VERSION 5.8 ;
BUSBITCHARS "[]" ;
DIVIDERCHAR "/" ;
UNITS
    DATABASE MICRONS 1000 ;
END UNITS

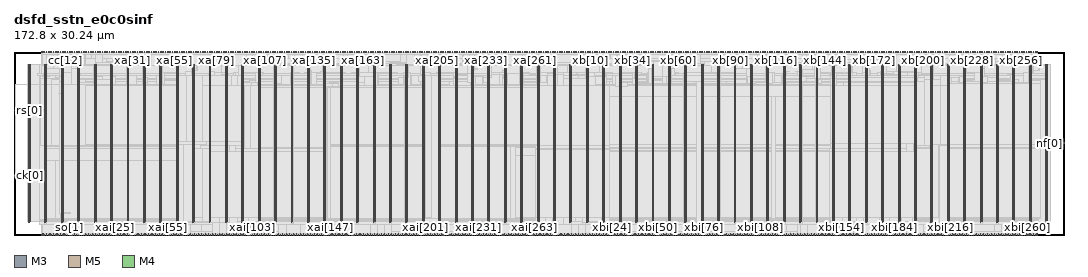
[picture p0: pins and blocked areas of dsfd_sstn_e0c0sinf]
MACRO dsfd_sstn_e0c0sinf
  FOREIGN dsfd_sstn_e0c0sinf 0 0 ;
  CLASS BLOCK ;
  SIZE 172.8 BY 30.24 ;
  PIN c0[0]
    DIRECTION INPUT ;
    USE SIGNAL ;
    PORT
      LAYER M3 ;
        RECT  4.464 30.096 4.482 30.24 ;
    END
  END c0[0]
  PIN c0[1]
    DIRECTION INPUT ;
    USE SIGNAL ;
    PORT
      LAYER M5 ;
        RECT  4.752 30.048 4.776 30.24 ;
    END
  END c0[1]
  PIN cc[0]
    DIRECTION OUTPUT ;
    USE SIGNAL ;
    PORT
      LAYER M3 ;
        RECT  5.04 30.096 5.058 30.24 ;
    END
  END cc[0]
  PIN cc[10]
    DIRECTION OUTPUT ;
    USE SIGNAL ;
    PORT
      LAYER M3 ;
        RECT  7.92 30.096 7.938 30.24 ;
    END
  END cc[10]
  PIN cc[11]
    DIRECTION OUTPUT ;
    USE SIGNAL ;
    PORT
      LAYER M5 ;
        RECT  8.208 30.048 8.232 30.24 ;
    END
  END cc[11]
  PIN cc[12]
    DIRECTION OUTPUT ;
    USE SIGNAL ;
    PORT
      LAYER M3 ;
        RECT  8.496 30.096 8.514 30.24 ;
    END
  END cc[12]
  PIN cc[13]
    DIRECTION OUTPUT ;
    USE SIGNAL ;
    PORT
      LAYER M5 ;
        RECT  8.784 30.048 8.808 30.24 ;
    END
  END cc[13]
  PIN cc[14]
    DIRECTION OUTPUT ;
    USE SIGNAL ;
    PORT
      LAYER M3 ;
        RECT  9.072 30.096 9.09 30.24 ;
    END
  END cc[14]
  PIN cc[1]
    DIRECTION OUTPUT ;
    USE SIGNAL ;
    PORT
      LAYER M5 ;
        RECT  5.328 30.048 5.352 30.24 ;
    END
  END cc[1]
  PIN cc[2]
    DIRECTION OUTPUT ;
    USE SIGNAL ;
    PORT
      LAYER M3 ;
        RECT  5.616 30.096 5.634 30.24 ;
    END
  END cc[2]
  PIN cc[3]
    DIRECTION OUTPUT ;
    USE SIGNAL ;
    PORT
      LAYER M5 ;
        RECT  5.904 30.048 5.928 30.24 ;
    END
  END cc[3]
  PIN cc[4]
    DIRECTION OUTPUT ;
    USE SIGNAL ;
    PORT
      LAYER M3 ;
        RECT  6.192 30.096 6.21 30.24 ;
    END
  END cc[4]
  PIN cc[5]
    DIRECTION OUTPUT ;
    USE SIGNAL ;
    PORT
      LAYER M5 ;
        RECT  6.48 30.048 6.504 30.24 ;
    END
  END cc[5]
  PIN cc[6]
    DIRECTION OUTPUT ;
    USE SIGNAL ;
    PORT
      LAYER M3 ;
        RECT  6.768 30.096 6.786 30.24 ;
    END
  END cc[6]
  PIN cc[7]
    DIRECTION OUTPUT ;
    USE SIGNAL ;
    PORT
      LAYER M5 ;
        RECT  7.056 30.048 7.08 30.24 ;
    END
  END cc[7]
  PIN cc[8]
    DIRECTION OUTPUT ;
    USE SIGNAL ;
    PORT
      LAYER M3 ;
        RECT  7.344 30.096 7.362 30.24 ;
    END
  END cc[8]
  PIN cc[9]
    DIRECTION OUTPUT ;
    USE SIGNAL ;
    PORT
      LAYER M5 ;
        RECT  7.632 30.048 7.656 30.24 ;
    END
  END cc[9]
  PIN cci[0]
    DIRECTION INPUT ;
    USE SIGNAL ;
    PORT
      LAYER M3 ;
        RECT  4.464 0 4.482 0.144 ;
    END
  END cci[0]
  PIN cci[10]
    DIRECTION INPUT ;
    USE SIGNAL ;
    PORT
      LAYER M3 ;
        RECT  7.344 0 7.362 0.144 ;
    END
  END cci[10]
  PIN cci[11]
    DIRECTION INPUT ;
    USE SIGNAL ;
    PORT
      LAYER M5 ;
        RECT  7.632 0 7.656 0.192 ;
    END
  END cci[11]
  PIN cci[12]
    DIRECTION INPUT ;
    USE SIGNAL ;
    PORT
      LAYER M3 ;
        RECT  7.92 0 7.938 0.144 ;
    END
  END cci[12]
  PIN cci[13]
    DIRECTION INPUT ;
    USE SIGNAL ;
    PORT
      LAYER M5 ;
        RECT  8.208 0 8.232 0.192 ;
    END
  END cci[13]
  PIN cci[14]
    DIRECTION INPUT ;
    USE SIGNAL ;
    PORT
      LAYER M3 ;
        RECT  8.532 0 8.55 0.144 ;
    END
  END cci[14]
  PIN cci[1]
    DIRECTION INPUT ;
    USE SIGNAL ;
    PORT
      LAYER M5 ;
        RECT  4.752 0 4.776 0.192 ;
    END
  END cci[1]
  PIN cci[2]
    DIRECTION INPUT ;
    USE SIGNAL ;
    PORT
      LAYER M3 ;
        RECT  5.04 0 5.058 0.144 ;
    END
  END cci[2]
  PIN cci[3]
    DIRECTION INPUT ;
    USE SIGNAL ;
    PORT
      LAYER M5 ;
        RECT  5.328 0 5.352 0.192 ;
    END
  END cci[3]
  PIN cci[4]
    DIRECTION INPUT ;
    USE SIGNAL ;
    PORT
      LAYER M3 ;
        RECT  5.616 0 5.634 0.144 ;
    END
  END cci[4]
  PIN cci[5]
    DIRECTION INPUT ;
    USE SIGNAL ;
    PORT
      LAYER M5 ;
        RECT  5.904 0 5.928 0.192 ;
    END
  END cci[5]
  PIN cci[6]
    DIRECTION INPUT ;
    USE SIGNAL ;
    PORT
      LAYER M3 ;
        RECT  6.192 0 6.21 0.144 ;
    END
  END cci[6]
  PIN cci[7]
    DIRECTION INPUT ;
    USE SIGNAL ;
    PORT
      LAYER M5 ;
        RECT  6.48 0 6.504 0.192 ;
    END
  END cci[7]
  PIN cci[8]
    DIRECTION INPUT ;
    USE SIGNAL ;
    PORT
      LAYER M3 ;
        RECT  6.768 0 6.786 0.144 ;
    END
  END cci[8]
  PIN cci[9]
    DIRECTION INPUT ;
    USE SIGNAL ;
    PORT
      LAYER M5 ;
        RECT  7.056 0 7.08 0.192 ;
    END
  END cci[9]
  PIN ck[0]
    DIRECTION INPUT ;
    USE SIGNAL ;
    PORT
      LAYER M4 ;
        RECT  0 9.744 0.192 9.768 ;
    END
    PORT
      LAYER M4 ;
        RECT  0.156 9.744 0.275 9.768 ;
    END
  END ck[0]
  PIN e0[0]
    DIRECTION INPUT ;
    USE SIGNAL ;
    PORT
      LAYER M5 ;
        RECT  9.36 30.048 9.384 30.24 ;
    END
  END e0[0]
  PIN e0[1]
    DIRECTION INPUT ;
    USE SIGNAL ;
    PORT
      LAYER M3 ;
        RECT  9.648 30.096 9.666 30.24 ;
    END
  END e0[1]
  PIN nf[0]
    DIRECTION INPUT ;
    USE SIGNAL ;
    PORT
      LAYER M4 ;
        RECT  172.608 15.12 172.8 15.144 ;
    END
    PORT
      LAYER M4 ;
        RECT  170.104 15.12 172.62 15.144 ;
    END
  END nf[0]
  PIN rs[0]
    DIRECTION INPUT ;
    USE SIGNAL ;
    PORT
      LAYER M4 ;
        RECT  0 20.544 0.192 20.568 ;
    END
    PORT
      LAYER M4 ;
        RECT  0.156 20.544 2.408 20.568 ;
    END
  END rs[0]
  PIN si[0]
    DIRECTION INPUT ;
    USE SIGNAL ;
    PORT
      LAYER M5 ;
        RECT  9.936 30.048 9.96 30.24 ;
    END
  END si[0]
  PIN si[1]
    DIRECTION INPUT ;
    USE SIGNAL ;
    PORT
      LAYER M3 ;
        RECT  10.224 30.096 10.242 30.24 ;
    END
  END si[1]
  PIN so[0]
    DIRECTION OUTPUT ;
    USE SIGNAL ;
    PORT
      LAYER M5 ;
        RECT  8.784 0 8.808 0.192 ;
    END
  END so[0]
  PIN so[1]
    DIRECTION OUTPUT ;
    USE SIGNAL ;
    PORT
      LAYER M3 ;
        RECT  9.108 0 9.126 0.144 ;
    END
  END so[1]
  PIN xa[0]
    DIRECTION OUTPUT ;
    USE SIGNAL ;
    PORT
      LAYER M5 ;
        RECT  10.512 30.048 10.536 30.24 ;
    END
  END xa[0]
  PIN xa[100]
    DIRECTION OUTPUT ;
    USE SIGNAL ;
    PORT
      LAYER M5 ;
        RECT  39.312 30.048 39.336 30.24 ;
    END
  END xa[100]
  PIN xa[101]
    DIRECTION OUTPUT ;
    USE SIGNAL ;
    PORT
      LAYER M3 ;
        RECT  39.6 30.096 39.618 30.24 ;
    END
  END xa[101]
  PIN xa[102]
    DIRECTION OUTPUT ;
    USE SIGNAL ;
    PORT
      LAYER M5 ;
        RECT  39.888 30.048 39.912 30.24 ;
    END
  END xa[102]
  PIN xa[103]
    DIRECTION OUTPUT ;
    USE SIGNAL ;
    PORT
      LAYER M3 ;
        RECT  40.176 30.096 40.194 30.24 ;
    END
  END xa[103]
  PIN xa[104]
    DIRECTION OUTPUT ;
    USE SIGNAL ;
    PORT
      LAYER M5 ;
        RECT  40.464 30.048 40.488 30.24 ;
    END
  END xa[104]
  PIN xa[105]
    DIRECTION OUTPUT ;
    USE SIGNAL ;
    PORT
      LAYER M3 ;
        RECT  40.752 30.096 40.77 30.24 ;
    END
  END xa[105]
  PIN xa[106]
    DIRECTION OUTPUT ;
    USE SIGNAL ;
    PORT
      LAYER M5 ;
        RECT  41.04 30.048 41.064 30.24 ;
    END
  END xa[106]
  PIN xa[107]
    DIRECTION OUTPUT ;
    USE SIGNAL ;
    PORT
      LAYER M3 ;
        RECT  41.328 30.096 41.346 30.24 ;
    END
  END xa[107]
  PIN xa[108]
    DIRECTION OUTPUT ;
    USE SIGNAL ;
    PORT
      LAYER M5 ;
        RECT  41.616 30.048 41.64 30.24 ;
    END
  END xa[108]
  PIN xa[109]
    DIRECTION OUTPUT ;
    USE SIGNAL ;
    PORT
      LAYER M3 ;
        RECT  41.904 30.096 41.922 30.24 ;
    END
  END xa[109]
  PIN xa[10]
    DIRECTION OUTPUT ;
    USE SIGNAL ;
    PORT
      LAYER M5 ;
        RECT  13.392 30.048 13.416 30.24 ;
    END
  END xa[10]
  PIN xa[110]
    DIRECTION OUTPUT ;
    USE SIGNAL ;
    PORT
      LAYER M5 ;
        RECT  42.192 30.048 42.216 30.24 ;
    END
  END xa[110]
  PIN xa[111]
    DIRECTION OUTPUT ;
    USE SIGNAL ;
    PORT
      LAYER M3 ;
        RECT  42.48 30.096 42.498 30.24 ;
    END
  END xa[111]
  PIN xa[112]
    DIRECTION OUTPUT ;
    USE SIGNAL ;
    PORT
      LAYER M5 ;
        RECT  42.768 30.048 42.792 30.24 ;
    END
  END xa[112]
  PIN xa[113]
    DIRECTION OUTPUT ;
    USE SIGNAL ;
    PORT
      LAYER M3 ;
        RECT  43.056 30.096 43.074 30.24 ;
    END
  END xa[113]
  PIN xa[114]
    DIRECTION OUTPUT ;
    USE SIGNAL ;
    PORT
      LAYER M5 ;
        RECT  43.344 30.048 43.368 30.24 ;
    END
  END xa[114]
  PIN xa[115]
    DIRECTION OUTPUT ;
    USE SIGNAL ;
    PORT
      LAYER M3 ;
        RECT  43.632 30.096 43.65 30.24 ;
    END
  END xa[115]
  PIN xa[116]
    DIRECTION OUTPUT ;
    USE SIGNAL ;
    PORT
      LAYER M5 ;
        RECT  43.92 30.048 43.944 30.24 ;
    END
  END xa[116]
  PIN xa[117]
    DIRECTION OUTPUT ;
    USE SIGNAL ;
    PORT
      LAYER M3 ;
        RECT  44.208 30.096 44.226 30.24 ;
    END
  END xa[117]
  PIN xa[118]
    DIRECTION OUTPUT ;
    USE SIGNAL ;
    PORT
      LAYER M5 ;
        RECT  44.496 30.048 44.52 30.24 ;
    END
  END xa[118]
  PIN xa[119]
    DIRECTION OUTPUT ;
    USE SIGNAL ;
    PORT
      LAYER M3 ;
        RECT  44.784 30.096 44.802 30.24 ;
    END
  END xa[119]
  PIN xa[11]
    DIRECTION OUTPUT ;
    USE SIGNAL ;
    PORT
      LAYER M3 ;
        RECT  13.68 30.096 13.698 30.24 ;
    END
  END xa[11]
  PIN xa[120]
    DIRECTION OUTPUT ;
    USE SIGNAL ;
    PORT
      LAYER M5 ;
        RECT  45.072 30.048 45.096 30.24 ;
    END
  END xa[120]
  PIN xa[121]
    DIRECTION OUTPUT ;
    USE SIGNAL ;
    PORT
      LAYER M3 ;
        RECT  45.36 30.096 45.378 30.24 ;
    END
  END xa[121]
  PIN xa[122]
    DIRECTION OUTPUT ;
    USE SIGNAL ;
    PORT
      LAYER M5 ;
        RECT  45.648 30.048 45.672 30.24 ;
    END
  END xa[122]
  PIN xa[123]
    DIRECTION OUTPUT ;
    USE SIGNAL ;
    PORT
      LAYER M3 ;
        RECT  45.936 30.096 45.954 30.24 ;
    END
  END xa[123]
  PIN xa[124]
    DIRECTION OUTPUT ;
    USE SIGNAL ;
    PORT
      LAYER M5 ;
        RECT  46.224 30.048 46.248 30.24 ;
    END
  END xa[124]
  PIN xa[125]
    DIRECTION OUTPUT ;
    USE SIGNAL ;
    PORT
      LAYER M3 ;
        RECT  46.512 30.096 46.53 30.24 ;
    END
  END xa[125]
  PIN xa[126]
    DIRECTION OUTPUT ;
    USE SIGNAL ;
    PORT
      LAYER M5 ;
        RECT  46.8 30.048 46.824 30.24 ;
    END
  END xa[126]
  PIN xa[127]
    DIRECTION OUTPUT ;
    USE SIGNAL ;
    PORT
      LAYER M3 ;
        RECT  47.088 30.096 47.106 30.24 ;
    END
  END xa[127]
  PIN xa[128]
    DIRECTION OUTPUT ;
    USE SIGNAL ;
    PORT
      LAYER M5 ;
        RECT  47.376 30.048 47.4 30.24 ;
    END
  END xa[128]
  PIN xa[129]
    DIRECTION OUTPUT ;
    USE SIGNAL ;
    PORT
      LAYER M3 ;
        RECT  47.664 30.096 47.682 30.24 ;
    END
  END xa[129]
  PIN xa[12]
    DIRECTION OUTPUT ;
    USE SIGNAL ;
    PORT
      LAYER M5 ;
        RECT  13.968 30.048 13.992 30.24 ;
    END
  END xa[12]
  PIN xa[130]
    DIRECTION OUTPUT ;
    USE SIGNAL ;
    PORT
      LAYER M5 ;
        RECT  47.952 30.048 47.976 30.24 ;
    END
  END xa[130]
  PIN xa[131]
    DIRECTION OUTPUT ;
    USE SIGNAL ;
    PORT
      LAYER M3 ;
        RECT  48.24 30.096 48.258 30.24 ;
    END
  END xa[131]
  PIN xa[132]
    DIRECTION OUTPUT ;
    USE SIGNAL ;
    PORT
      LAYER M5 ;
        RECT  48.528 30.048 48.552 30.24 ;
    END
  END xa[132]
  PIN xa[133]
    DIRECTION OUTPUT ;
    USE SIGNAL ;
    PORT
      LAYER M3 ;
        RECT  48.816 30.096 48.834 30.24 ;
    END
  END xa[133]
  PIN xa[134]
    DIRECTION OUTPUT ;
    USE SIGNAL ;
    PORT
      LAYER M5 ;
        RECT  49.104 30.048 49.128 30.24 ;
    END
  END xa[134]
  PIN xa[135]
    DIRECTION OUTPUT ;
    USE SIGNAL ;
    PORT
      LAYER M3 ;
        RECT  49.392 30.096 49.41 30.24 ;
    END
  END xa[135]
  PIN xa[136]
    DIRECTION OUTPUT ;
    USE SIGNAL ;
    PORT
      LAYER M5 ;
        RECT  49.68 30.048 49.704 30.24 ;
    END
  END xa[136]
  PIN xa[137]
    DIRECTION OUTPUT ;
    USE SIGNAL ;
    PORT
      LAYER M3 ;
        RECT  49.968 30.096 49.986 30.24 ;
    END
  END xa[137]
  PIN xa[138]
    DIRECTION OUTPUT ;
    USE SIGNAL ;
    PORT
      LAYER M5 ;
        RECT  50.256 30.048 50.28 30.24 ;
    END
  END xa[138]
  PIN xa[139]
    DIRECTION OUTPUT ;
    USE SIGNAL ;
    PORT
      LAYER M3 ;
        RECT  50.544 30.096 50.562 30.24 ;
    END
  END xa[139]
  PIN xa[13]
    DIRECTION OUTPUT ;
    USE SIGNAL ;
    PORT
      LAYER M3 ;
        RECT  14.256 30.096 14.274 30.24 ;
    END
  END xa[13]
  PIN xa[140]
    DIRECTION OUTPUT ;
    USE SIGNAL ;
    PORT
      LAYER M5 ;
        RECT  50.832 30.048 50.856 30.24 ;
    END
  END xa[140]
  PIN xa[141]
    DIRECTION OUTPUT ;
    USE SIGNAL ;
    PORT
      LAYER M3 ;
        RECT  51.12 30.096 51.138 30.24 ;
    END
  END xa[141]
  PIN xa[142]
    DIRECTION OUTPUT ;
    USE SIGNAL ;
    PORT
      LAYER M5 ;
        RECT  51.408 30.048 51.432 30.24 ;
    END
  END xa[142]
  PIN xa[143]
    DIRECTION OUTPUT ;
    USE SIGNAL ;
    PORT
      LAYER M3 ;
        RECT  51.696 30.096 51.714 30.24 ;
    END
  END xa[143]
  PIN xa[144]
    DIRECTION OUTPUT ;
    USE SIGNAL ;
    PORT
      LAYER M5 ;
        RECT  51.984 30.048 52.008 30.24 ;
    END
  END xa[144]
  PIN xa[145]
    DIRECTION OUTPUT ;
    USE SIGNAL ;
    PORT
      LAYER M3 ;
        RECT  52.272 30.096 52.29 30.24 ;
    END
  END xa[145]
  PIN xa[146]
    DIRECTION OUTPUT ;
    USE SIGNAL ;
    PORT
      LAYER M5 ;
        RECT  52.56 30.048 52.584 30.24 ;
    END
  END xa[146]
  PIN xa[147]
    DIRECTION OUTPUT ;
    USE SIGNAL ;
    PORT
      LAYER M3 ;
        RECT  52.848 30.096 52.866 30.24 ;
    END
  END xa[147]
  PIN xa[148]
    DIRECTION OUTPUT ;
    USE SIGNAL ;
    PORT
      LAYER M5 ;
        RECT  53.136 30.048 53.16 30.24 ;
    END
  END xa[148]
  PIN xa[149]
    DIRECTION OUTPUT ;
    USE SIGNAL ;
    PORT
      LAYER M3 ;
        RECT  53.424 30.096 53.442 30.24 ;
    END
  END xa[149]
  PIN xa[14]
    DIRECTION OUTPUT ;
    USE SIGNAL ;
    PORT
      LAYER M5 ;
        RECT  14.544 30.048 14.568 30.24 ;
    END
  END xa[14]
  PIN xa[150]
    DIRECTION OUTPUT ;
    USE SIGNAL ;
    PORT
      LAYER M5 ;
        RECT  53.712 30.048 53.736 30.24 ;
    END
  END xa[150]
  PIN xa[151]
    DIRECTION OUTPUT ;
    USE SIGNAL ;
    PORT
      LAYER M3 ;
        RECT  54 30.096 54.018 30.24 ;
    END
  END xa[151]
  PIN xa[152]
    DIRECTION OUTPUT ;
    USE SIGNAL ;
    PORT
      LAYER M5 ;
        RECT  54.288 30.048 54.312 30.24 ;
    END
  END xa[152]
  PIN xa[153]
    DIRECTION OUTPUT ;
    USE SIGNAL ;
    PORT
      LAYER M3 ;
        RECT  54.576 30.096 54.594 30.24 ;
    END
  END xa[153]
  PIN xa[154]
    DIRECTION OUTPUT ;
    USE SIGNAL ;
    PORT
      LAYER M5 ;
        RECT  54.864 30.048 54.888 30.24 ;
    END
  END xa[154]
  PIN xa[155]
    DIRECTION OUTPUT ;
    USE SIGNAL ;
    PORT
      LAYER M3 ;
        RECT  55.152 30.096 55.17 30.24 ;
    END
  END xa[155]
  PIN xa[156]
    DIRECTION OUTPUT ;
    USE SIGNAL ;
    PORT
      LAYER M5 ;
        RECT  55.44 30.048 55.464 30.24 ;
    END
  END xa[156]
  PIN xa[157]
    DIRECTION OUTPUT ;
    USE SIGNAL ;
    PORT
      LAYER M3 ;
        RECT  55.728 30.096 55.746 30.24 ;
    END
  END xa[157]
  PIN xa[158]
    DIRECTION OUTPUT ;
    USE SIGNAL ;
    PORT
      LAYER M5 ;
        RECT  56.016 30.048 56.04 30.24 ;
    END
  END xa[158]
  PIN xa[159]
    DIRECTION OUTPUT ;
    USE SIGNAL ;
    PORT
      LAYER M3 ;
        RECT  56.304 30.096 56.322 30.24 ;
    END
  END xa[159]
  PIN xa[15]
    DIRECTION OUTPUT ;
    USE SIGNAL ;
    PORT
      LAYER M3 ;
        RECT  14.832 30.096 14.85 30.24 ;
    END
  END xa[15]
  PIN xa[160]
    DIRECTION OUTPUT ;
    USE SIGNAL ;
    PORT
      LAYER M5 ;
        RECT  56.592 30.048 56.616 30.24 ;
    END
  END xa[160]
  PIN xa[161]
    DIRECTION OUTPUT ;
    USE SIGNAL ;
    PORT
      LAYER M3 ;
        RECT  56.88 30.096 56.898 30.24 ;
    END
  END xa[161]
  PIN xa[162]
    DIRECTION OUTPUT ;
    USE SIGNAL ;
    PORT
      LAYER M5 ;
        RECT  57.168 30.048 57.192 30.24 ;
    END
  END xa[162]
  PIN xa[163]
    DIRECTION OUTPUT ;
    USE SIGNAL ;
    PORT
      LAYER M3 ;
        RECT  57.456 30.096 57.474 30.24 ;
    END
  END xa[163]
  PIN xa[164]
    DIRECTION OUTPUT ;
    USE SIGNAL ;
    PORT
      LAYER M5 ;
        RECT  57.744 30.048 57.768 30.24 ;
    END
  END xa[164]
  PIN xa[165]
    DIRECTION OUTPUT ;
    USE SIGNAL ;
    PORT
      LAYER M3 ;
        RECT  58.032 30.096 58.05 30.24 ;
    END
  END xa[165]
  PIN xa[166]
    DIRECTION OUTPUT ;
    USE SIGNAL ;
    PORT
      LAYER M5 ;
        RECT  58.32 30.048 58.344 30.24 ;
    END
  END xa[166]
  PIN xa[167]
    DIRECTION OUTPUT ;
    USE SIGNAL ;
    PORT
      LAYER M3 ;
        RECT  58.608 30.096 58.626 30.24 ;
    END
  END xa[167]
  PIN xa[168]
    DIRECTION OUTPUT ;
    USE SIGNAL ;
    PORT
      LAYER M5 ;
        RECT  58.896 30.048 58.92 30.24 ;
    END
  END xa[168]
  PIN xa[169]
    DIRECTION OUTPUT ;
    USE SIGNAL ;
    PORT
      LAYER M3 ;
        RECT  59.184 30.096 59.202 30.24 ;
    END
  END xa[169]
  PIN xa[16]
    DIRECTION OUTPUT ;
    USE SIGNAL ;
    PORT
      LAYER M5 ;
        RECT  15.12 30.048 15.144 30.24 ;
    END
  END xa[16]
  PIN xa[170]
    DIRECTION OUTPUT ;
    USE SIGNAL ;
    PORT
      LAYER M5 ;
        RECT  59.472 30.048 59.496 30.24 ;
    END
  END xa[170]
  PIN xa[171]
    DIRECTION OUTPUT ;
    USE SIGNAL ;
    PORT
      LAYER M3 ;
        RECT  59.76 30.096 59.778 30.24 ;
    END
  END xa[171]
  PIN xa[172]
    DIRECTION OUTPUT ;
    USE SIGNAL ;
    PORT
      LAYER M5 ;
        RECT  60.048 30.048 60.072 30.24 ;
    END
  END xa[172]
  PIN xa[173]
    DIRECTION OUTPUT ;
    USE SIGNAL ;
    PORT
      LAYER M3 ;
        RECT  60.336 30.096 60.354 30.24 ;
    END
  END xa[173]
  PIN xa[174]
    DIRECTION OUTPUT ;
    USE SIGNAL ;
    PORT
      LAYER M5 ;
        RECT  60.624 30.048 60.648 30.24 ;
    END
  END xa[174]
  PIN xa[175]
    DIRECTION OUTPUT ;
    USE SIGNAL ;
    PORT
      LAYER M3 ;
        RECT  60.912 30.096 60.93 30.24 ;
    END
  END xa[175]
  PIN xa[176]
    DIRECTION OUTPUT ;
    USE SIGNAL ;
    PORT
      LAYER M5 ;
        RECT  61.2 30.048 61.224 30.24 ;
    END
  END xa[176]
  PIN xa[177]
    DIRECTION OUTPUT ;
    USE SIGNAL ;
    PORT
      LAYER M3 ;
        RECT  61.488 30.096 61.506 30.24 ;
    END
  END xa[177]
  PIN xa[178]
    DIRECTION OUTPUT ;
    USE SIGNAL ;
    PORT
      LAYER M5 ;
        RECT  61.776 30.048 61.8 30.24 ;
    END
  END xa[178]
  PIN xa[179]
    DIRECTION OUTPUT ;
    USE SIGNAL ;
    PORT
      LAYER M3 ;
        RECT  62.064 30.096 62.082 30.24 ;
    END
  END xa[179]
  PIN xa[17]
    DIRECTION OUTPUT ;
    USE SIGNAL ;
    PORT
      LAYER M3 ;
        RECT  15.408 30.096 15.426 30.24 ;
    END
  END xa[17]
  PIN xa[180]
    DIRECTION OUTPUT ;
    USE SIGNAL ;
    PORT
      LAYER M5 ;
        RECT  62.352 30.048 62.376 30.24 ;
    END
  END xa[180]
  PIN xa[181]
    DIRECTION OUTPUT ;
    USE SIGNAL ;
    PORT
      LAYER M3 ;
        RECT  62.64 30.096 62.658 30.24 ;
    END
  END xa[181]
  PIN xa[182]
    DIRECTION OUTPUT ;
    USE SIGNAL ;
    PORT
      LAYER M5 ;
        RECT  62.928 30.048 62.952 30.24 ;
    END
  END xa[182]
  PIN xa[183]
    DIRECTION OUTPUT ;
    USE SIGNAL ;
    PORT
      LAYER M3 ;
        RECT  63.216 30.096 63.234 30.24 ;
    END
  END xa[183]
  PIN xa[184]
    DIRECTION OUTPUT ;
    USE SIGNAL ;
    PORT
      LAYER M5 ;
        RECT  63.504 30.048 63.528 30.24 ;
    END
  END xa[184]
  PIN xa[185]
    DIRECTION OUTPUT ;
    USE SIGNAL ;
    PORT
      LAYER M3 ;
        RECT  63.792 30.096 63.81 30.24 ;
    END
  END xa[185]
  PIN xa[186]
    DIRECTION OUTPUT ;
    USE SIGNAL ;
    PORT
      LAYER M5 ;
        RECT  64.08 30.048 64.104 30.24 ;
    END
  END xa[186]
  PIN xa[187]
    DIRECTION OUTPUT ;
    USE SIGNAL ;
    PORT
      LAYER M3 ;
        RECT  64.368 30.096 64.386 30.24 ;
    END
  END xa[187]
  PIN xa[188]
    DIRECTION OUTPUT ;
    USE SIGNAL ;
    PORT
      LAYER M5 ;
        RECT  64.656 30.048 64.68 30.24 ;
    END
  END xa[188]
  PIN xa[189]
    DIRECTION OUTPUT ;
    USE SIGNAL ;
    PORT
      LAYER M3 ;
        RECT  64.944 30.096 64.962 30.24 ;
    END
  END xa[189]
  PIN xa[18]
    DIRECTION OUTPUT ;
    USE SIGNAL ;
    PORT
      LAYER M5 ;
        RECT  15.696 30.048 15.72 30.24 ;
    END
  END xa[18]
  PIN xa[190]
    DIRECTION OUTPUT ;
    USE SIGNAL ;
    PORT
      LAYER M5 ;
        RECT  65.232 30.048 65.256 30.24 ;
    END
  END xa[190]
  PIN xa[191]
    DIRECTION OUTPUT ;
    USE SIGNAL ;
    PORT
      LAYER M3 ;
        RECT  65.52 30.096 65.538 30.24 ;
    END
  END xa[191]
  PIN xa[192]
    DIRECTION OUTPUT ;
    USE SIGNAL ;
    PORT
      LAYER M5 ;
        RECT  65.808 30.048 65.832 30.24 ;
    END
  END xa[192]
  PIN xa[193]
    DIRECTION OUTPUT ;
    USE SIGNAL ;
    PORT
      LAYER M3 ;
        RECT  66.096 30.096 66.114 30.24 ;
    END
  END xa[193]
  PIN xa[194]
    DIRECTION OUTPUT ;
    USE SIGNAL ;
    PORT
      LAYER M5 ;
        RECT  66.384 30.048 66.408 30.24 ;
    END
  END xa[194]
  PIN xa[195]
    DIRECTION OUTPUT ;
    USE SIGNAL ;
    PORT
      LAYER M3 ;
        RECT  66.672 30.096 66.69 30.24 ;
    END
  END xa[195]
  PIN xa[196]
    DIRECTION OUTPUT ;
    USE SIGNAL ;
    PORT
      LAYER M5 ;
        RECT  66.96 30.048 66.984 30.24 ;
    END
  END xa[196]
  PIN xa[197]
    DIRECTION OUTPUT ;
    USE SIGNAL ;
    PORT
      LAYER M3 ;
        RECT  67.248 30.096 67.266 30.24 ;
    END
  END xa[197]
  PIN xa[198]
    DIRECTION OUTPUT ;
    USE SIGNAL ;
    PORT
      LAYER M5 ;
        RECT  67.536 30.048 67.56 30.24 ;
    END
  END xa[198]
  PIN xa[199]
    DIRECTION OUTPUT ;
    USE SIGNAL ;
    PORT
      LAYER M3 ;
        RECT  67.824 30.096 67.842 30.24 ;
    END
  END xa[199]
  PIN xa[19]
    DIRECTION OUTPUT ;
    USE SIGNAL ;
    PORT
      LAYER M3 ;
        RECT  15.984 30.096 16.002 30.24 ;
    END
  END xa[19]
  PIN xa[1]
    DIRECTION OUTPUT ;
    USE SIGNAL ;
    PORT
      LAYER M3 ;
        RECT  10.8 30.096 10.818 30.24 ;
    END
  END xa[1]
  PIN xa[200]
    DIRECTION OUTPUT ;
    USE SIGNAL ;
    PORT
      LAYER M5 ;
        RECT  68.112 30.048 68.136 30.24 ;
    END
  END xa[200]
  PIN xa[201]
    DIRECTION OUTPUT ;
    USE SIGNAL ;
    PORT
      LAYER M3 ;
        RECT  68.4 30.096 68.418 30.24 ;
    END
  END xa[201]
  PIN xa[202]
    DIRECTION OUTPUT ;
    USE SIGNAL ;
    PORT
      LAYER M5 ;
        RECT  68.688 30.048 68.712 30.24 ;
    END
  END xa[202]
  PIN xa[203]
    DIRECTION OUTPUT ;
    USE SIGNAL ;
    PORT
      LAYER M3 ;
        RECT  68.976 30.096 68.994 30.24 ;
    END
  END xa[203]
  PIN xa[204]
    DIRECTION OUTPUT ;
    USE SIGNAL ;
    PORT
      LAYER M5 ;
        RECT  69.264 30.048 69.288 30.24 ;
    END
  END xa[204]
  PIN xa[205]
    DIRECTION OUTPUT ;
    USE SIGNAL ;
    PORT
      LAYER M3 ;
        RECT  69.552 30.096 69.57 30.24 ;
    END
  END xa[205]
  PIN xa[206]
    DIRECTION OUTPUT ;
    USE SIGNAL ;
    PORT
      LAYER M5 ;
        RECT  69.84 30.048 69.864 30.24 ;
    END
  END xa[206]
  PIN xa[207]
    DIRECTION OUTPUT ;
    USE SIGNAL ;
    PORT
      LAYER M3 ;
        RECT  70.128 30.096 70.146 30.24 ;
    END
  END xa[207]
  PIN xa[208]
    DIRECTION OUTPUT ;
    USE SIGNAL ;
    PORT
      LAYER M5 ;
        RECT  70.416 30.048 70.44 30.24 ;
    END
  END xa[208]
  PIN xa[209]
    DIRECTION OUTPUT ;
    USE SIGNAL ;
    PORT
      LAYER M3 ;
        RECT  70.704 30.096 70.722 30.24 ;
    END
  END xa[209]
  PIN xa[20]
    DIRECTION OUTPUT ;
    USE SIGNAL ;
    PORT
      LAYER M5 ;
        RECT  16.272 30.048 16.296 30.24 ;
    END
  END xa[20]
  PIN xa[210]
    DIRECTION OUTPUT ;
    USE SIGNAL ;
    PORT
      LAYER M5 ;
        RECT  70.992 30.048 71.016 30.24 ;
    END
  END xa[210]
  PIN xa[211]
    DIRECTION OUTPUT ;
    USE SIGNAL ;
    PORT
      LAYER M3 ;
        RECT  71.28 30.096 71.298 30.24 ;
    END
  END xa[211]
  PIN xa[212]
    DIRECTION OUTPUT ;
    USE SIGNAL ;
    PORT
      LAYER M5 ;
        RECT  71.568 30.048 71.592 30.24 ;
    END
  END xa[212]
  PIN xa[213]
    DIRECTION OUTPUT ;
    USE SIGNAL ;
    PORT
      LAYER M3 ;
        RECT  71.856 30.096 71.874 30.24 ;
    END
  END xa[213]
  PIN xa[214]
    DIRECTION OUTPUT ;
    USE SIGNAL ;
    PORT
      LAYER M5 ;
        RECT  72.144 30.048 72.168 30.24 ;
    END
  END xa[214]
  PIN xa[215]
    DIRECTION OUTPUT ;
    USE SIGNAL ;
    PORT
      LAYER M3 ;
        RECT  72.432 30.096 72.45 30.24 ;
    END
  END xa[215]
  PIN xa[216]
    DIRECTION OUTPUT ;
    USE SIGNAL ;
    PORT
      LAYER M5 ;
        RECT  72.72 30.048 72.744 30.24 ;
    END
  END xa[216]
  PIN xa[217]
    DIRECTION OUTPUT ;
    USE SIGNAL ;
    PORT
      LAYER M3 ;
        RECT  73.008 30.096 73.026 30.24 ;
    END
  END xa[217]
  PIN xa[218]
    DIRECTION OUTPUT ;
    USE SIGNAL ;
    PORT
      LAYER M5 ;
        RECT  73.296 30.048 73.32 30.24 ;
    END
  END xa[218]
  PIN xa[219]
    DIRECTION OUTPUT ;
    USE SIGNAL ;
    PORT
      LAYER M3 ;
        RECT  73.584 30.096 73.602 30.24 ;
    END
  END xa[219]
  PIN xa[21]
    DIRECTION OUTPUT ;
    USE SIGNAL ;
    PORT
      LAYER M3 ;
        RECT  16.56 30.096 16.578 30.24 ;
    END
  END xa[21]
  PIN xa[220]
    DIRECTION OUTPUT ;
    USE SIGNAL ;
    PORT
      LAYER M5 ;
        RECT  73.872 30.048 73.896 30.24 ;
    END
  END xa[220]
  PIN xa[221]
    DIRECTION OUTPUT ;
    USE SIGNAL ;
    PORT
      LAYER M3 ;
        RECT  74.16 30.096 74.178 30.24 ;
    END
  END xa[221]
  PIN xa[222]
    DIRECTION OUTPUT ;
    USE SIGNAL ;
    PORT
      LAYER M5 ;
        RECT  74.448 30.048 74.472 30.24 ;
    END
  END xa[222]
  PIN xa[223]
    DIRECTION OUTPUT ;
    USE SIGNAL ;
    PORT
      LAYER M3 ;
        RECT  74.736 30.096 74.754 30.24 ;
    END
  END xa[223]
  PIN xa[224]
    DIRECTION OUTPUT ;
    USE SIGNAL ;
    PORT
      LAYER M5 ;
        RECT  75.024 30.048 75.048 30.24 ;
    END
  END xa[224]
  PIN xa[225]
    DIRECTION OUTPUT ;
    USE SIGNAL ;
    PORT
      LAYER M3 ;
        RECT  75.312 30.096 75.33 30.24 ;
    END
  END xa[225]
  PIN xa[226]
    DIRECTION OUTPUT ;
    USE SIGNAL ;
    PORT
      LAYER M5 ;
        RECT  75.6 30.048 75.624 30.24 ;
    END
  END xa[226]
  PIN xa[227]
    DIRECTION OUTPUT ;
    USE SIGNAL ;
    PORT
      LAYER M3 ;
        RECT  75.888 30.096 75.906 30.24 ;
    END
  END xa[227]
  PIN xa[228]
    DIRECTION OUTPUT ;
    USE SIGNAL ;
    PORT
      LAYER M5 ;
        RECT  76.176 30.048 76.2 30.24 ;
    END
  END xa[228]
  PIN xa[229]
    DIRECTION OUTPUT ;
    USE SIGNAL ;
    PORT
      LAYER M3 ;
        RECT  76.464 30.096 76.482 30.24 ;
    END
  END xa[229]
  PIN xa[22]
    DIRECTION OUTPUT ;
    USE SIGNAL ;
    PORT
      LAYER M5 ;
        RECT  16.848 30.048 16.872 30.24 ;
    END
  END xa[22]
  PIN xa[230]
    DIRECTION OUTPUT ;
    USE SIGNAL ;
    PORT
      LAYER M5 ;
        RECT  76.752 30.048 76.776 30.24 ;
    END
  END xa[230]
  PIN xa[231]
    DIRECTION OUTPUT ;
    USE SIGNAL ;
    PORT
      LAYER M3 ;
        RECT  77.04 30.096 77.058 30.24 ;
    END
  END xa[231]
  PIN xa[232]
    DIRECTION OUTPUT ;
    USE SIGNAL ;
    PORT
      LAYER M5 ;
        RECT  77.328 30.048 77.352 30.24 ;
    END
  END xa[232]
  PIN xa[233]
    DIRECTION OUTPUT ;
    USE SIGNAL ;
    PORT
      LAYER M3 ;
        RECT  77.616 30.096 77.634 30.24 ;
    END
  END xa[233]
  PIN xa[234]
    DIRECTION OUTPUT ;
    USE SIGNAL ;
    PORT
      LAYER M5 ;
        RECT  77.904 30.048 77.928 30.24 ;
    END
  END xa[234]
  PIN xa[235]
    DIRECTION OUTPUT ;
    USE SIGNAL ;
    PORT
      LAYER M3 ;
        RECT  78.192 30.096 78.21 30.24 ;
    END
  END xa[235]
  PIN xa[236]
    DIRECTION OUTPUT ;
    USE SIGNAL ;
    PORT
      LAYER M5 ;
        RECT  78.48 30.048 78.504 30.24 ;
    END
  END xa[236]
  PIN xa[237]
    DIRECTION OUTPUT ;
    USE SIGNAL ;
    PORT
      LAYER M3 ;
        RECT  78.768 30.096 78.786 30.24 ;
    END
  END xa[237]
  PIN xa[238]
    DIRECTION OUTPUT ;
    USE SIGNAL ;
    PORT
      LAYER M5 ;
        RECT  79.056 30.048 79.08 30.24 ;
    END
  END xa[238]
  PIN xa[239]
    DIRECTION OUTPUT ;
    USE SIGNAL ;
    PORT
      LAYER M3 ;
        RECT  79.344 30.096 79.362 30.24 ;
    END
  END xa[239]
  PIN xa[23]
    DIRECTION OUTPUT ;
    USE SIGNAL ;
    PORT
      LAYER M3 ;
        RECT  17.136 30.096 17.154 30.24 ;
    END
  END xa[23]
  PIN xa[240]
    DIRECTION OUTPUT ;
    USE SIGNAL ;
    PORT
      LAYER M5 ;
        RECT  79.632 30.048 79.656 30.24 ;
    END
  END xa[240]
  PIN xa[241]
    DIRECTION OUTPUT ;
    USE SIGNAL ;
    PORT
      LAYER M3 ;
        RECT  79.92 30.096 79.938 30.24 ;
    END
  END xa[241]
  PIN xa[242]
    DIRECTION OUTPUT ;
    USE SIGNAL ;
    PORT
      LAYER M5 ;
        RECT  80.208 30.048 80.232 30.24 ;
    END
  END xa[242]
  PIN xa[243]
    DIRECTION OUTPUT ;
    USE SIGNAL ;
    PORT
      LAYER M3 ;
        RECT  80.496 30.096 80.514 30.24 ;
    END
  END xa[243]
  PIN xa[244]
    DIRECTION OUTPUT ;
    USE SIGNAL ;
    PORT
      LAYER M5 ;
        RECT  80.784 30.048 80.808 30.24 ;
    END
  END xa[244]
  PIN xa[245]
    DIRECTION OUTPUT ;
    USE SIGNAL ;
    PORT
      LAYER M3 ;
        RECT  81.072 30.096 81.09 30.24 ;
    END
  END xa[245]
  PIN xa[246]
    DIRECTION OUTPUT ;
    USE SIGNAL ;
    PORT
      LAYER M5 ;
        RECT  81.36 30.048 81.384 30.24 ;
    END
  END xa[246]
  PIN xa[247]
    DIRECTION OUTPUT ;
    USE SIGNAL ;
    PORT
      LAYER M3 ;
        RECT  81.648 30.096 81.666 30.24 ;
    END
  END xa[247]
  PIN xa[248]
    DIRECTION OUTPUT ;
    USE SIGNAL ;
    PORT
      LAYER M5 ;
        RECT  81.936 30.048 81.96 30.24 ;
    END
  END xa[248]
  PIN xa[249]
    DIRECTION OUTPUT ;
    USE SIGNAL ;
    PORT
      LAYER M3 ;
        RECT  82.224 30.096 82.242 30.24 ;
    END
  END xa[249]
  PIN xa[24]
    DIRECTION OUTPUT ;
    USE SIGNAL ;
    PORT
      LAYER M5 ;
        RECT  17.424 30.048 17.448 30.24 ;
    END
  END xa[24]
  PIN xa[250]
    DIRECTION OUTPUT ;
    USE SIGNAL ;
    PORT
      LAYER M5 ;
        RECT  82.512 30.048 82.536 30.24 ;
    END
  END xa[250]
  PIN xa[251]
    DIRECTION OUTPUT ;
    USE SIGNAL ;
    PORT
      LAYER M3 ;
        RECT  82.8 30.096 82.818 30.24 ;
    END
  END xa[251]
  PIN xa[252]
    DIRECTION OUTPUT ;
    USE SIGNAL ;
    PORT
      LAYER M5 ;
        RECT  83.088 30.048 83.112 30.24 ;
    END
  END xa[252]
  PIN xa[253]
    DIRECTION OUTPUT ;
    USE SIGNAL ;
    PORT
      LAYER M3 ;
        RECT  83.376 30.096 83.394 30.24 ;
    END
  END xa[253]
  PIN xa[254]
    DIRECTION OUTPUT ;
    USE SIGNAL ;
    PORT
      LAYER M5 ;
        RECT  83.664 30.048 83.688 30.24 ;
    END
  END xa[254]
  PIN xa[255]
    DIRECTION OUTPUT ;
    USE SIGNAL ;
    PORT
      LAYER M3 ;
        RECT  83.952 30.096 83.97 30.24 ;
    END
  END xa[255]
  PIN xa[256]
    DIRECTION OUTPUT ;
    USE SIGNAL ;
    PORT
      LAYER M5 ;
        RECT  84.24 30.048 84.264 30.24 ;
    END
  END xa[256]
  PIN xa[257]
    DIRECTION OUTPUT ;
    USE SIGNAL ;
    PORT
      LAYER M3 ;
        RECT  84.528 30.096 84.546 30.24 ;
    END
  END xa[257]
  PIN xa[258]
    DIRECTION OUTPUT ;
    USE SIGNAL ;
    PORT
      LAYER M5 ;
        RECT  84.816 30.048 84.84 30.24 ;
    END
  END xa[258]
  PIN xa[259]
    DIRECTION OUTPUT ;
    USE SIGNAL ;
    PORT
      LAYER M3 ;
        RECT  85.104 30.096 85.122 30.24 ;
    END
  END xa[259]
  PIN xa[25]
    DIRECTION OUTPUT ;
    USE SIGNAL ;
    PORT
      LAYER M3 ;
        RECT  17.712 30.096 17.73 30.24 ;
    END
  END xa[25]
  PIN xa[260]
    DIRECTION OUTPUT ;
    USE SIGNAL ;
    PORT
      LAYER M5 ;
        RECT  85.392 30.048 85.416 30.24 ;
    END
  END xa[260]
  PIN xa[261]
    DIRECTION OUTPUT ;
    USE SIGNAL ;
    PORT
      LAYER M3 ;
        RECT  85.68 30.096 85.698 30.24 ;
    END
  END xa[261]
  PIN xa[262]
    DIRECTION OUTPUT ;
    USE SIGNAL ;
    PORT
      LAYER M5 ;
        RECT  85.968 30.048 85.992 30.24 ;
    END
  END xa[262]
  PIN xa[263]
    DIRECTION OUTPUT ;
    USE SIGNAL ;
    PORT
      LAYER M3 ;
        RECT  86.256 30.096 86.274 30.24 ;
    END
  END xa[263]
  PIN xa[264]
    DIRECTION OUTPUT ;
    USE SIGNAL ;
    PORT
      LAYER M5 ;
        RECT  86.544 30.048 86.568 30.24 ;
    END
  END xa[264]
  PIN xa[265]
    DIRECTION OUTPUT ;
    USE SIGNAL ;
    PORT
      LAYER M3 ;
        RECT  86.832 30.096 86.85 30.24 ;
    END
  END xa[265]
  PIN xa[266]
    DIRECTION OUTPUT ;
    USE SIGNAL ;
    PORT
      LAYER M5 ;
        RECT  87.12 30.048 87.144 30.24 ;
    END
  END xa[266]
  PIN xa[267]
    DIRECTION OUTPUT ;
    USE SIGNAL ;
    PORT
      LAYER M3 ;
        RECT  87.408 30.096 87.426 30.24 ;
    END
  END xa[267]
  PIN xa[268]
    DIRECTION OUTPUT ;
    USE SIGNAL ;
    PORT
      LAYER M5 ;
        RECT  87.696 30.048 87.72 30.24 ;
    END
  END xa[268]
  PIN xa[269]
    DIRECTION OUTPUT ;
    USE SIGNAL ;
    PORT
      LAYER M3 ;
        RECT  87.984 30.096 88.002 30.24 ;
    END
  END xa[269]
  PIN xa[26]
    DIRECTION OUTPUT ;
    USE SIGNAL ;
    PORT
      LAYER M5 ;
        RECT  18 30.048 18.024 30.24 ;
    END
  END xa[26]
  PIN xa[270]
    DIRECTION OUTPUT ;
    USE SIGNAL ;
    PORT
      LAYER M5 ;
        RECT  88.272 30.048 88.296 30.24 ;
    END
  END xa[270]
  PIN xa[271]
    DIRECTION OUTPUT ;
    USE SIGNAL ;
    PORT
      LAYER M3 ;
        RECT  88.56 30.096 88.578 30.24 ;
    END
  END xa[271]
  PIN xa[272]
    DIRECTION OUTPUT ;
    USE SIGNAL ;
    PORT
      LAYER M5 ;
        RECT  88.848 30.048 88.872 30.24 ;
    END
  END xa[272]
  PIN xa[273]
    DIRECTION OUTPUT ;
    USE SIGNAL ;
    PORT
      LAYER M3 ;
        RECT  89.136 30.096 89.154 30.24 ;
    END
  END xa[273]
  PIN xa[274]
    DIRECTION OUTPUT ;
    USE SIGNAL ;
    PORT
      LAYER M5 ;
        RECT  89.424 30.048 89.448 30.24 ;
    END
  END xa[274]
  PIN xa[275]
    DIRECTION OUTPUT ;
    USE SIGNAL ;
    PORT
      LAYER M3 ;
        RECT  89.712 30.096 89.73 30.24 ;
    END
  END xa[275]
  PIN xa[276]
    DIRECTION OUTPUT ;
    USE SIGNAL ;
    PORT
      LAYER M5 ;
        RECT  90 30.048 90.024 30.24 ;
    END
  END xa[276]
  PIN xa[277]
    DIRECTION OUTPUT ;
    USE SIGNAL ;
    PORT
      LAYER M3 ;
        RECT  90.288 30.096 90.306 30.24 ;
    END
  END xa[277]
  PIN xa[278]
    DIRECTION OUTPUT ;
    USE SIGNAL ;
    PORT
      LAYER M5 ;
        RECT  90.576 30.048 90.6 30.24 ;
    END
  END xa[278]
  PIN xa[279]
    DIRECTION OUTPUT ;
    USE SIGNAL ;
    PORT
      LAYER M3 ;
        RECT  90.864 30.096 90.882 30.24 ;
    END
  END xa[279]
  PIN xa[27]
    DIRECTION OUTPUT ;
    USE SIGNAL ;
    PORT
      LAYER M3 ;
        RECT  18.288 30.096 18.306 30.24 ;
    END
  END xa[27]
  PIN xa[280]
    DIRECTION OUTPUT ;
    USE SIGNAL ;
    PORT
      LAYER M5 ;
        RECT  91.152 30.048 91.176 30.24 ;
    END
  END xa[280]
  PIN xa[281]
    DIRECTION OUTPUT ;
    USE SIGNAL ;
    PORT
      LAYER M3 ;
        RECT  91.44 30.096 91.458 30.24 ;
    END
  END xa[281]
  PIN xa[282]
    DIRECTION OUTPUT ;
    USE SIGNAL ;
    PORT
      LAYER M5 ;
        RECT  91.728 30.048 91.752 30.24 ;
    END
  END xa[282]
  PIN xa[28]
    DIRECTION OUTPUT ;
    USE SIGNAL ;
    PORT
      LAYER M5 ;
        RECT  18.576 30.048 18.6 30.24 ;
    END
  END xa[28]
  PIN xa[29]
    DIRECTION OUTPUT ;
    USE SIGNAL ;
    PORT
      LAYER M3 ;
        RECT  18.864 30.096 18.882 30.24 ;
    END
  END xa[29]
  PIN xa[2]
    DIRECTION OUTPUT ;
    USE SIGNAL ;
    PORT
      LAYER M5 ;
        RECT  11.088 30.048 11.112 30.24 ;
    END
  END xa[2]
  PIN xa[30]
    DIRECTION OUTPUT ;
    USE SIGNAL ;
    PORT
      LAYER M5 ;
        RECT  19.152 30.048 19.176 30.24 ;
    END
  END xa[30]
  PIN xa[31]
    DIRECTION OUTPUT ;
    USE SIGNAL ;
    PORT
      LAYER M3 ;
        RECT  19.44 30.096 19.458 30.24 ;
    END
  END xa[31]
  PIN xa[32]
    DIRECTION OUTPUT ;
    USE SIGNAL ;
    PORT
      LAYER M5 ;
        RECT  19.728 30.048 19.752 30.24 ;
    END
  END xa[32]
  PIN xa[33]
    DIRECTION OUTPUT ;
    USE SIGNAL ;
    PORT
      LAYER M3 ;
        RECT  20.016 30.096 20.034 30.24 ;
    END
  END xa[33]
  PIN xa[34]
    DIRECTION OUTPUT ;
    USE SIGNAL ;
    PORT
      LAYER M5 ;
        RECT  20.304 30.048 20.328 30.24 ;
    END
  END xa[34]
  PIN xa[35]
    DIRECTION OUTPUT ;
    USE SIGNAL ;
    PORT
      LAYER M3 ;
        RECT  20.592 30.096 20.61 30.24 ;
    END
  END xa[35]
  PIN xa[36]
    DIRECTION OUTPUT ;
    USE SIGNAL ;
    PORT
      LAYER M5 ;
        RECT  20.88 30.048 20.904 30.24 ;
    END
  END xa[36]
  PIN xa[37]
    DIRECTION OUTPUT ;
    USE SIGNAL ;
    PORT
      LAYER M3 ;
        RECT  21.168 30.096 21.186 30.24 ;
    END
  END xa[37]
  PIN xa[38]
    DIRECTION OUTPUT ;
    USE SIGNAL ;
    PORT
      LAYER M5 ;
        RECT  21.456 30.048 21.48 30.24 ;
    END
  END xa[38]
  PIN xa[39]
    DIRECTION OUTPUT ;
    USE SIGNAL ;
    PORT
      LAYER M3 ;
        RECT  21.744 30.096 21.762 30.24 ;
    END
  END xa[39]
  PIN xa[3]
    DIRECTION OUTPUT ;
    USE SIGNAL ;
    PORT
      LAYER M3 ;
        RECT  11.376 30.096 11.394 30.24 ;
    END
  END xa[3]
  PIN xa[40]
    DIRECTION OUTPUT ;
    USE SIGNAL ;
    PORT
      LAYER M5 ;
        RECT  22.032 30.048 22.056 30.24 ;
    END
  END xa[40]
  PIN xa[41]
    DIRECTION OUTPUT ;
    USE SIGNAL ;
    PORT
      LAYER M3 ;
        RECT  22.32 30.096 22.338 30.24 ;
    END
  END xa[41]
  PIN xa[42]
    DIRECTION OUTPUT ;
    USE SIGNAL ;
    PORT
      LAYER M5 ;
        RECT  22.608 30.048 22.632 30.24 ;
    END
  END xa[42]
  PIN xa[43]
    DIRECTION OUTPUT ;
    USE SIGNAL ;
    PORT
      LAYER M3 ;
        RECT  22.896 30.096 22.914 30.24 ;
    END
  END xa[43]
  PIN xa[44]
    DIRECTION OUTPUT ;
    USE SIGNAL ;
    PORT
      LAYER M5 ;
        RECT  23.184 30.048 23.208 30.24 ;
    END
  END xa[44]
  PIN xa[45]
    DIRECTION OUTPUT ;
    USE SIGNAL ;
    PORT
      LAYER M3 ;
        RECT  23.472 30.096 23.49 30.24 ;
    END
  END xa[45]
  PIN xa[46]
    DIRECTION OUTPUT ;
    USE SIGNAL ;
    PORT
      LAYER M5 ;
        RECT  23.76 30.048 23.784 30.24 ;
    END
  END xa[46]
  PIN xa[47]
    DIRECTION OUTPUT ;
    USE SIGNAL ;
    PORT
      LAYER M3 ;
        RECT  24.048 30.096 24.066 30.24 ;
    END
  END xa[47]
  PIN xa[48]
    DIRECTION OUTPUT ;
    USE SIGNAL ;
    PORT
      LAYER M5 ;
        RECT  24.336 30.048 24.36 30.24 ;
    END
  END xa[48]
  PIN xa[49]
    DIRECTION OUTPUT ;
    USE SIGNAL ;
    PORT
      LAYER M3 ;
        RECT  24.624 30.096 24.642 30.24 ;
    END
  END xa[49]
  PIN xa[4]
    DIRECTION OUTPUT ;
    USE SIGNAL ;
    PORT
      LAYER M5 ;
        RECT  11.664 30.048 11.688 30.24 ;
    END
  END xa[4]
  PIN xa[50]
    DIRECTION OUTPUT ;
    USE SIGNAL ;
    PORT
      LAYER M5 ;
        RECT  24.912 30.048 24.936 30.24 ;
    END
  END xa[50]
  PIN xa[51]
    DIRECTION OUTPUT ;
    USE SIGNAL ;
    PORT
      LAYER M3 ;
        RECT  25.2 30.096 25.218 30.24 ;
    END
  END xa[51]
  PIN xa[52]
    DIRECTION OUTPUT ;
    USE SIGNAL ;
    PORT
      LAYER M5 ;
        RECT  25.488 30.048 25.512 30.24 ;
    END
  END xa[52]
  PIN xa[53]
    DIRECTION OUTPUT ;
    USE SIGNAL ;
    PORT
      LAYER M3 ;
        RECT  25.776 30.096 25.794 30.24 ;
    END
  END xa[53]
  PIN xa[54]
    DIRECTION OUTPUT ;
    USE SIGNAL ;
    PORT
      LAYER M5 ;
        RECT  26.064 30.048 26.088 30.24 ;
    END
  END xa[54]
  PIN xa[55]
    DIRECTION OUTPUT ;
    USE SIGNAL ;
    PORT
      LAYER M3 ;
        RECT  26.352 30.096 26.37 30.24 ;
    END
  END xa[55]
  PIN xa[56]
    DIRECTION OUTPUT ;
    USE SIGNAL ;
    PORT
      LAYER M5 ;
        RECT  26.64 30.048 26.664 30.24 ;
    END
  END xa[56]
  PIN xa[57]
    DIRECTION OUTPUT ;
    USE SIGNAL ;
    PORT
      LAYER M3 ;
        RECT  26.928 30.096 26.946 30.24 ;
    END
  END xa[57]
  PIN xa[58]
    DIRECTION OUTPUT ;
    USE SIGNAL ;
    PORT
      LAYER M5 ;
        RECT  27.216 30.048 27.24 30.24 ;
    END
  END xa[58]
  PIN xa[59]
    DIRECTION OUTPUT ;
    USE SIGNAL ;
    PORT
      LAYER M3 ;
        RECT  27.504 30.096 27.522 30.24 ;
    END
  END xa[59]
  PIN xa[5]
    DIRECTION OUTPUT ;
    USE SIGNAL ;
    PORT
      LAYER M3 ;
        RECT  11.952 30.096 11.97 30.24 ;
    END
  END xa[5]
  PIN xa[60]
    DIRECTION OUTPUT ;
    USE SIGNAL ;
    PORT
      LAYER M5 ;
        RECT  27.792 30.048 27.816 30.24 ;
    END
  END xa[60]
  PIN xa[61]
    DIRECTION OUTPUT ;
    USE SIGNAL ;
    PORT
      LAYER M3 ;
        RECT  28.08 30.096 28.098 30.24 ;
    END
  END xa[61]
  PIN xa[62]
    DIRECTION OUTPUT ;
    USE SIGNAL ;
    PORT
      LAYER M5 ;
        RECT  28.368 30.048 28.392 30.24 ;
    END
  END xa[62]
  PIN xa[63]
    DIRECTION OUTPUT ;
    USE SIGNAL ;
    PORT
      LAYER M3 ;
        RECT  28.656 30.096 28.674 30.24 ;
    END
  END xa[63]
  PIN xa[64]
    DIRECTION OUTPUT ;
    USE SIGNAL ;
    PORT
      LAYER M5 ;
        RECT  28.944 30.048 28.968 30.24 ;
    END
  END xa[64]
  PIN xa[65]
    DIRECTION OUTPUT ;
    USE SIGNAL ;
    PORT
      LAYER M3 ;
        RECT  29.232 30.096 29.25 30.24 ;
    END
  END xa[65]
  PIN xa[66]
    DIRECTION OUTPUT ;
    USE SIGNAL ;
    PORT
      LAYER M5 ;
        RECT  29.52 30.048 29.544 30.24 ;
    END
  END xa[66]
  PIN xa[67]
    DIRECTION OUTPUT ;
    USE SIGNAL ;
    PORT
      LAYER M3 ;
        RECT  29.808 30.096 29.826 30.24 ;
    END
  END xa[67]
  PIN xa[68]
    DIRECTION OUTPUT ;
    USE SIGNAL ;
    PORT
      LAYER M5 ;
        RECT  30.096 30.048 30.12 30.24 ;
    END
  END xa[68]
  PIN xa[69]
    DIRECTION OUTPUT ;
    USE SIGNAL ;
    PORT
      LAYER M3 ;
        RECT  30.384 30.096 30.402 30.24 ;
    END
  END xa[69]
  PIN xa[6]
    DIRECTION OUTPUT ;
    USE SIGNAL ;
    PORT
      LAYER M5 ;
        RECT  12.24 30.048 12.264 30.24 ;
    END
  END xa[6]
  PIN xa[70]
    DIRECTION OUTPUT ;
    USE SIGNAL ;
    PORT
      LAYER M5 ;
        RECT  30.672 30.048 30.696 30.24 ;
    END
  END xa[70]
  PIN xa[71]
    DIRECTION OUTPUT ;
    USE SIGNAL ;
    PORT
      LAYER M3 ;
        RECT  30.96 30.096 30.978 30.24 ;
    END
  END xa[71]
  PIN xa[72]
    DIRECTION OUTPUT ;
    USE SIGNAL ;
    PORT
      LAYER M5 ;
        RECT  31.248 30.048 31.272 30.24 ;
    END
  END xa[72]
  PIN xa[73]
    DIRECTION OUTPUT ;
    USE SIGNAL ;
    PORT
      LAYER M3 ;
        RECT  31.536 30.096 31.554 30.24 ;
    END
  END xa[73]
  PIN xa[74]
    DIRECTION OUTPUT ;
    USE SIGNAL ;
    PORT
      LAYER M5 ;
        RECT  31.824 30.048 31.848 30.24 ;
    END
  END xa[74]
  PIN xa[75]
    DIRECTION OUTPUT ;
    USE SIGNAL ;
    PORT
      LAYER M3 ;
        RECT  32.112 30.096 32.13 30.24 ;
    END
  END xa[75]
  PIN xa[76]
    DIRECTION OUTPUT ;
    USE SIGNAL ;
    PORT
      LAYER M5 ;
        RECT  32.4 30.048 32.424 30.24 ;
    END
  END xa[76]
  PIN xa[77]
    DIRECTION OUTPUT ;
    USE SIGNAL ;
    PORT
      LAYER M3 ;
        RECT  32.688 30.096 32.706 30.24 ;
    END
  END xa[77]
  PIN xa[78]
    DIRECTION OUTPUT ;
    USE SIGNAL ;
    PORT
      LAYER M5 ;
        RECT  32.976 30.048 33 30.24 ;
    END
  END xa[78]
  PIN xa[79]
    DIRECTION OUTPUT ;
    USE SIGNAL ;
    PORT
      LAYER M3 ;
        RECT  33.264 30.096 33.282 30.24 ;
    END
  END xa[79]
  PIN xa[7]
    DIRECTION OUTPUT ;
    USE SIGNAL ;
    PORT
      LAYER M3 ;
        RECT  12.528 30.096 12.546 30.24 ;
    END
  END xa[7]
  PIN xa[80]
    DIRECTION OUTPUT ;
    USE SIGNAL ;
    PORT
      LAYER M5 ;
        RECT  33.552 30.048 33.576 30.24 ;
    END
  END xa[80]
  PIN xa[81]
    DIRECTION OUTPUT ;
    USE SIGNAL ;
    PORT
      LAYER M3 ;
        RECT  33.84 30.096 33.858 30.24 ;
    END
  END xa[81]
  PIN xa[82]
    DIRECTION OUTPUT ;
    USE SIGNAL ;
    PORT
      LAYER M5 ;
        RECT  34.128 30.048 34.152 30.24 ;
    END
  END xa[82]
  PIN xa[83]
    DIRECTION OUTPUT ;
    USE SIGNAL ;
    PORT
      LAYER M3 ;
        RECT  34.416 30.096 34.434 30.24 ;
    END
  END xa[83]
  PIN xa[84]
    DIRECTION OUTPUT ;
    USE SIGNAL ;
    PORT
      LAYER M5 ;
        RECT  34.704 30.048 34.728 30.24 ;
    END
  END xa[84]
  PIN xa[85]
    DIRECTION OUTPUT ;
    USE SIGNAL ;
    PORT
      LAYER M3 ;
        RECT  34.992 30.096 35.01 30.24 ;
    END
  END xa[85]
  PIN xa[86]
    DIRECTION OUTPUT ;
    USE SIGNAL ;
    PORT
      LAYER M5 ;
        RECT  35.28 30.048 35.304 30.24 ;
    END
  END xa[86]
  PIN xa[87]
    DIRECTION OUTPUT ;
    USE SIGNAL ;
    PORT
      LAYER M3 ;
        RECT  35.568 30.096 35.586 30.24 ;
    END
  END xa[87]
  PIN xa[88]
    DIRECTION OUTPUT ;
    USE SIGNAL ;
    PORT
      LAYER M5 ;
        RECT  35.856 30.048 35.88 30.24 ;
    END
  END xa[88]
  PIN xa[89]
    DIRECTION OUTPUT ;
    USE SIGNAL ;
    PORT
      LAYER M3 ;
        RECT  36.144 30.096 36.162 30.24 ;
    END
  END xa[89]
  PIN xa[8]
    DIRECTION OUTPUT ;
    USE SIGNAL ;
    PORT
      LAYER M5 ;
        RECT  12.816 30.048 12.84 30.24 ;
    END
  END xa[8]
  PIN xa[90]
    DIRECTION OUTPUT ;
    USE SIGNAL ;
    PORT
      LAYER M5 ;
        RECT  36.432 30.048 36.456 30.24 ;
    END
  END xa[90]
  PIN xa[91]
    DIRECTION OUTPUT ;
    USE SIGNAL ;
    PORT
      LAYER M3 ;
        RECT  36.72 30.096 36.738 30.24 ;
    END
  END xa[91]
  PIN xa[92]
    DIRECTION OUTPUT ;
    USE SIGNAL ;
    PORT
      LAYER M5 ;
        RECT  37.008 30.048 37.032 30.24 ;
    END
  END xa[92]
  PIN xa[93]
    DIRECTION OUTPUT ;
    USE SIGNAL ;
    PORT
      LAYER M3 ;
        RECT  37.296 30.096 37.314 30.24 ;
    END
  END xa[93]
  PIN xa[94]
    DIRECTION OUTPUT ;
    USE SIGNAL ;
    PORT
      LAYER M5 ;
        RECT  37.584 30.048 37.608 30.24 ;
    END
  END xa[94]
  PIN xa[95]
    DIRECTION OUTPUT ;
    USE SIGNAL ;
    PORT
      LAYER M3 ;
        RECT  37.872 30.096 37.89 30.24 ;
    END
  END xa[95]
  PIN xa[96]
    DIRECTION OUTPUT ;
    USE SIGNAL ;
    PORT
      LAYER M5 ;
        RECT  38.16 30.048 38.184 30.24 ;
    END
  END xa[96]
  PIN xa[97]
    DIRECTION OUTPUT ;
    USE SIGNAL ;
    PORT
      LAYER M3 ;
        RECT  38.448 30.096 38.466 30.24 ;
    END
  END xa[97]
  PIN xa[98]
    DIRECTION OUTPUT ;
    USE SIGNAL ;
    PORT
      LAYER M5 ;
        RECT  38.736 30.048 38.76 30.24 ;
    END
  END xa[98]
  PIN xa[99]
    DIRECTION OUTPUT ;
    USE SIGNAL ;
    PORT
      LAYER M3 ;
        RECT  39.024 30.096 39.042 30.24 ;
    END
  END xa[99]
  PIN xa[9]
    DIRECTION OUTPUT ;
    USE SIGNAL ;
    PORT
      LAYER M3 ;
        RECT  13.104 30.096 13.122 30.24 ;
    END
  END xa[9]
  PIN xai[0]
    DIRECTION INPUT ;
    USE SIGNAL ;
    PORT
      LAYER M5 ;
        RECT  9.36 0 9.384 0.192 ;
    END
  END xai[0]
  PIN xai[100]
    DIRECTION INPUT ;
    USE SIGNAL ;
    PORT
      LAYER M5 ;
        RECT  38.4 0 38.424 0.192 ;
    END
  END xai[100]
  PIN xai[101]
    DIRECTION INPUT ;
    USE SIGNAL ;
    PORT
      LAYER M3 ;
        RECT  38.664 0 38.682 0.144 ;
    END
  END xai[101]
  PIN xai[102]
    DIRECTION INPUT ;
    USE SIGNAL ;
    PORT
      LAYER M5 ;
        RECT  38.976 0 39 0.192 ;
    END
  END xai[102]
  PIN xai[103]
    DIRECTION INPUT ;
    USE SIGNAL ;
    PORT
      LAYER M3 ;
        RECT  39.276 0 39.294 0.144 ;
    END
  END xai[103]
  PIN xai[104]
    DIRECTION INPUT ;
    USE SIGNAL ;
    PORT
      LAYER M5 ;
        RECT  39.552 0 39.576 0.192 ;
    END
  END xai[104]
  PIN xai[105]
    DIRECTION INPUT ;
    USE SIGNAL ;
    PORT
      LAYER M3 ;
        RECT  39.852 0 39.87 0.144 ;
    END
  END xai[105]
  PIN xai[106]
    DIRECTION INPUT ;
    USE SIGNAL ;
    PORT
      LAYER M5 ;
        RECT  40.128 0 40.152 0.192 ;
    END
  END xai[106]
  PIN xai[107]
    DIRECTION INPUT ;
    USE SIGNAL ;
    PORT
      LAYER M3 ;
        RECT  40.428 0 40.446 0.144 ;
    END
  END xai[107]
  PIN xai[108]
    DIRECTION INPUT ;
    USE SIGNAL ;
    PORT
      LAYER M5 ;
        RECT  40.704 0 40.728 0.192 ;
    END
  END xai[108]
  PIN xai[109]
    DIRECTION INPUT ;
    USE SIGNAL ;
    PORT
      LAYER M3 ;
        RECT  41.004 0 41.022 0.144 ;
    END
  END xai[109]
  PIN xai[10]
    DIRECTION INPUT ;
    USE SIGNAL ;
    PORT
      LAYER M5 ;
        RECT  12.288 0 12.312 0.192 ;
    END
  END xai[10]
  PIN xai[110]
    DIRECTION INPUT ;
    USE SIGNAL ;
    PORT
      LAYER M5 ;
        RECT  41.28 0 41.304 0.192 ;
    END
  END xai[110]
  PIN xai[111]
    DIRECTION INPUT ;
    USE SIGNAL ;
    PORT
      LAYER M3 ;
        RECT  41.58 0 41.598 0.144 ;
    END
  END xai[111]
  PIN xai[112]
    DIRECTION INPUT ;
    USE SIGNAL ;
    PORT
      LAYER M5 ;
        RECT  41.856 0 41.88 0.192 ;
    END
  END xai[112]
  PIN xai[113]
    DIRECTION INPUT ;
    USE SIGNAL ;
    PORT
      LAYER M3 ;
        RECT  42.156 0 42.174 0.144 ;
    END
  END xai[113]
  PIN xai[114]
    DIRECTION INPUT ;
    USE SIGNAL ;
    PORT
      LAYER M5 ;
        RECT  42.432 0 42.456 0.192 ;
    END
  END xai[114]
  PIN xai[115]
    DIRECTION INPUT ;
    USE SIGNAL ;
    PORT
      LAYER M3 ;
        RECT  42.732 0 42.75 0.144 ;
    END
  END xai[115]
  PIN xai[116]
    DIRECTION INPUT ;
    USE SIGNAL ;
    PORT
      LAYER M5 ;
        RECT  43.008 0 43.032 0.192 ;
    END
  END xai[116]
  PIN xai[117]
    DIRECTION INPUT ;
    USE SIGNAL ;
    PORT
      LAYER M3 ;
        RECT  43.308 0 43.326 0.144 ;
    END
  END xai[117]
  PIN xai[118]
    DIRECTION INPUT ;
    USE SIGNAL ;
    PORT
      LAYER M5 ;
        RECT  43.584 0 43.608 0.192 ;
    END
  END xai[118]
  PIN xai[119]
    DIRECTION INPUT ;
    USE SIGNAL ;
    PORT
      LAYER M3 ;
        RECT  43.884 0 43.902 0.144 ;
    END
  END xai[119]
  PIN xai[11]
    DIRECTION INPUT ;
    USE SIGNAL ;
    PORT
      LAYER M3 ;
        RECT  12.564 0 12.582 0.144 ;
    END
  END xai[11]
  PIN xai[120]
    DIRECTION INPUT ;
    USE SIGNAL ;
    PORT
      LAYER M5 ;
        RECT  44.208 0 44.232 0.192 ;
    END
  END xai[120]
  PIN xai[121]
    DIRECTION INPUT ;
    USE SIGNAL ;
    PORT
      LAYER M3 ;
        RECT  44.496 0 44.514 0.144 ;
    END
  END xai[121]
  PIN xai[122]
    DIRECTION INPUT ;
    USE SIGNAL ;
    PORT
      LAYER M5 ;
        RECT  44.784 0 44.808 0.192 ;
    END
  END xai[122]
  PIN xai[123]
    DIRECTION INPUT ;
    USE SIGNAL ;
    PORT
      LAYER M3 ;
        RECT  45.072 0 45.09 0.144 ;
    END
  END xai[123]
  PIN xai[124]
    DIRECTION INPUT ;
    USE SIGNAL ;
    PORT
      LAYER M5 ;
        RECT  45.36 0 45.384 0.192 ;
    END
  END xai[124]
  PIN xai[125]
    DIRECTION INPUT ;
    USE SIGNAL ;
    PORT
      LAYER M3 ;
        RECT  45.648 0 45.666 0.144 ;
    END
  END xai[125]
  PIN xai[126]
    DIRECTION INPUT ;
    USE SIGNAL ;
    PORT
      LAYER M5 ;
        RECT  45.936 0 45.96 0.192 ;
    END
  END xai[126]
  PIN xai[127]
    DIRECTION INPUT ;
    USE SIGNAL ;
    PORT
      LAYER M3 ;
        RECT  46.224 0 46.242 0.144 ;
    END
  END xai[127]
  PIN xai[128]
    DIRECTION INPUT ;
    USE SIGNAL ;
    PORT
      LAYER M5 ;
        RECT  46.512 0 46.536 0.192 ;
    END
  END xai[128]
  PIN xai[129]
    DIRECTION INPUT ;
    USE SIGNAL ;
    PORT
      LAYER M3 ;
        RECT  46.8 0 46.818 0.144 ;
    END
  END xai[129]
  PIN xai[12]
    DIRECTION INPUT ;
    USE SIGNAL ;
    PORT
      LAYER M5 ;
        RECT  12.864 0 12.888 0.192 ;
    END
  END xai[12]
  PIN xai[130]
    DIRECTION INPUT ;
    USE SIGNAL ;
    PORT
      LAYER M5 ;
        RECT  47.088 0 47.112 0.192 ;
    END
  END xai[130]
  PIN xai[131]
    DIRECTION INPUT ;
    USE SIGNAL ;
    PORT
      LAYER M3 ;
        RECT  47.376 0 47.394 0.144 ;
    END
  END xai[131]
  PIN xai[132]
    DIRECTION INPUT ;
    USE SIGNAL ;
    PORT
      LAYER M5 ;
        RECT  47.664 0 47.688 0.192 ;
    END
  END xai[132]
  PIN xai[133]
    DIRECTION INPUT ;
    USE SIGNAL ;
    PORT
      LAYER M3 ;
        RECT  47.952 0 47.97 0.144 ;
    END
  END xai[133]
  PIN xai[134]
    DIRECTION INPUT ;
    USE SIGNAL ;
    PORT
      LAYER M5 ;
        RECT  48.24 0 48.264 0.192 ;
    END
  END xai[134]
  PIN xai[135]
    DIRECTION INPUT ;
    USE SIGNAL ;
    PORT
      LAYER M3 ;
        RECT  48.528 0 48.546 0.144 ;
    END
  END xai[135]
  PIN xai[136]
    DIRECTION INPUT ;
    USE SIGNAL ;
    PORT
      LAYER M5 ;
        RECT  48.816 0 48.84 0.192 ;
    END
  END xai[136]
  PIN xai[137]
    DIRECTION INPUT ;
    USE SIGNAL ;
    PORT
      LAYER M3 ;
        RECT  49.104 0 49.122 0.144 ;
    END
  END xai[137]
  PIN xai[138]
    DIRECTION INPUT ;
    USE SIGNAL ;
    PORT
      LAYER M5 ;
        RECT  49.392 0 49.416 0.192 ;
    END
  END xai[138]
  PIN xai[139]
    DIRECTION INPUT ;
    USE SIGNAL ;
    PORT
      LAYER M3 ;
        RECT  49.716 0 49.734 0.144 ;
    END
  END xai[139]
  PIN xai[13]
    DIRECTION INPUT ;
    USE SIGNAL ;
    PORT
      LAYER M3 ;
        RECT  13.14 0 13.158 0.144 ;
    END
  END xai[13]
  PIN xai[140]
    DIRECTION INPUT ;
    USE SIGNAL ;
    PORT
      LAYER M5 ;
        RECT  49.968 0 49.992 0.192 ;
    END
  END xai[140]
  PIN xai[141]
    DIRECTION INPUT ;
    USE SIGNAL ;
    PORT
      LAYER M3 ;
        RECT  50.292 0 50.31 0.144 ;
    END
  END xai[141]
  PIN xai[142]
    DIRECTION INPUT ;
    USE SIGNAL ;
    PORT
      LAYER M5 ;
        RECT  50.592 0 50.616 0.192 ;
    END
  END xai[142]
  PIN xai[143]
    DIRECTION INPUT ;
    USE SIGNAL ;
    PORT
      LAYER M3 ;
        RECT  50.868 0 50.886 0.144 ;
    END
  END xai[143]
  PIN xai[144]
    DIRECTION INPUT ;
    USE SIGNAL ;
    PORT
      LAYER M5 ;
        RECT  51.168 0 51.192 0.192 ;
    END
  END xai[144]
  PIN xai[145]
    DIRECTION INPUT ;
    USE SIGNAL ;
    PORT
      LAYER M3 ;
        RECT  51.444 0 51.462 0.144 ;
    END
  END xai[145]
  PIN xai[146]
    DIRECTION INPUT ;
    USE SIGNAL ;
    PORT
      LAYER M5 ;
        RECT  51.744 0 51.768 0.192 ;
    END
  END xai[146]
  PIN xai[147]
    DIRECTION INPUT ;
    USE SIGNAL ;
    PORT
      LAYER M3 ;
        RECT  52.02 0 52.038 0.144 ;
    END
  END xai[147]
  PIN xai[148]
    DIRECTION INPUT ;
    USE SIGNAL ;
    PORT
      LAYER M5 ;
        RECT  52.32 0 52.344 0.192 ;
    END
  END xai[148]
  PIN xai[149]
    DIRECTION INPUT ;
    USE SIGNAL ;
    PORT
      LAYER M3 ;
        RECT  52.596 0 52.614 0.144 ;
    END
  END xai[149]
  PIN xai[14]
    DIRECTION INPUT ;
    USE SIGNAL ;
    PORT
      LAYER M5 ;
        RECT  13.44 0 13.464 0.192 ;
    END
  END xai[14]
  PIN xai[150]
    DIRECTION INPUT ;
    USE SIGNAL ;
    PORT
      LAYER M5 ;
        RECT  52.896 0 52.92 0.192 ;
    END
  END xai[150]
  PIN xai[151]
    DIRECTION INPUT ;
    USE SIGNAL ;
    PORT
      LAYER M3 ;
        RECT  53.172 0 53.19 0.144 ;
    END
  END xai[151]
  PIN xai[152]
    DIRECTION INPUT ;
    USE SIGNAL ;
    PORT
      LAYER M5 ;
        RECT  53.472 0 53.496 0.192 ;
    END
  END xai[152]
  PIN xai[153]
    DIRECTION INPUT ;
    USE SIGNAL ;
    PORT
      LAYER M3 ;
        RECT  53.748 0 53.766 0.144 ;
    END
  END xai[153]
  PIN xai[154]
    DIRECTION INPUT ;
    USE SIGNAL ;
    PORT
      LAYER M5 ;
        RECT  54.048 0 54.072 0.192 ;
    END
  END xai[154]
  PIN xai[155]
    DIRECTION INPUT ;
    USE SIGNAL ;
    PORT
      LAYER M3 ;
        RECT  54.36 0 54.378 0.144 ;
    END
  END xai[155]
  PIN xai[156]
    DIRECTION INPUT ;
    USE SIGNAL ;
    PORT
      LAYER M5 ;
        RECT  54.624 0 54.648 0.192 ;
    END
  END xai[156]
  PIN xai[157]
    DIRECTION INPUT ;
    USE SIGNAL ;
    PORT
      LAYER M3 ;
        RECT  54.936 0 54.954 0.144 ;
    END
  END xai[157]
  PIN xai[158]
    DIRECTION INPUT ;
    USE SIGNAL ;
    PORT
      LAYER M5 ;
        RECT  55.2 0 55.224 0.192 ;
    END
  END xai[158]
  PIN xai[159]
    DIRECTION INPUT ;
    USE SIGNAL ;
    PORT
      LAYER M3 ;
        RECT  55.512 0 55.53 0.144 ;
    END
  END xai[159]
  PIN xai[15]
    DIRECTION INPUT ;
    USE SIGNAL ;
    PORT
      LAYER M3 ;
        RECT  13.752 0 13.77 0.144 ;
    END
  END xai[15]
  PIN xai[160]
    DIRECTION INPUT ;
    USE SIGNAL ;
    PORT
      LAYER M5 ;
        RECT  55.776 0 55.8 0.192 ;
    END
  END xai[160]
  PIN xai[161]
    DIRECTION INPUT ;
    USE SIGNAL ;
    PORT
      LAYER M3 ;
        RECT  56.088 0 56.106 0.144 ;
    END
  END xai[161]
  PIN xai[162]
    DIRECTION INPUT ;
    USE SIGNAL ;
    PORT
      LAYER M5 ;
        RECT  56.352 0 56.376 0.192 ;
    END
  END xai[162]
  PIN xai[163]
    DIRECTION INPUT ;
    USE SIGNAL ;
    PORT
      LAYER M3 ;
        RECT  56.664 0 56.682 0.144 ;
    END
  END xai[163]
  PIN xai[164]
    DIRECTION INPUT ;
    USE SIGNAL ;
    PORT
      LAYER M5 ;
        RECT  56.928 0 56.952 0.192 ;
    END
  END xai[164]
  PIN xai[165]
    DIRECTION INPUT ;
    USE SIGNAL ;
    PORT
      LAYER M3 ;
        RECT  57.24 0 57.258 0.144 ;
    END
  END xai[165]
  PIN xai[166]
    DIRECTION INPUT ;
    USE SIGNAL ;
    PORT
      LAYER M5 ;
        RECT  57.552 0 57.576 0.192 ;
    END
  END xai[166]
  PIN xai[167]
    DIRECTION INPUT ;
    USE SIGNAL ;
    PORT
      LAYER M3 ;
        RECT  57.816 0 57.834 0.144 ;
    END
  END xai[167]
  PIN xai[168]
    DIRECTION INPUT ;
    USE SIGNAL ;
    PORT
      LAYER M5 ;
        RECT  58.128 0 58.152 0.192 ;
    END
  END xai[168]
  PIN xai[169]
    DIRECTION INPUT ;
    USE SIGNAL ;
    PORT
      LAYER M3 ;
        RECT  58.392 0 58.41 0.144 ;
    END
  END xai[169]
  PIN xai[16]
    DIRECTION INPUT ;
    USE SIGNAL ;
    PORT
      LAYER M5 ;
        RECT  14.016 0 14.04 0.192 ;
    END
  END xai[16]
  PIN xai[170]
    DIRECTION INPUT ;
    USE SIGNAL ;
    PORT
      LAYER M5 ;
        RECT  58.704 0 58.728 0.192 ;
    END
  END xai[170]
  PIN xai[171]
    DIRECTION INPUT ;
    USE SIGNAL ;
    PORT
      LAYER M3 ;
        RECT  58.968 0 58.986 0.144 ;
    END
  END xai[171]
  PIN xai[172]
    DIRECTION INPUT ;
    USE SIGNAL ;
    PORT
      LAYER M5 ;
        RECT  59.28 0 59.304 0.192 ;
    END
  END xai[172]
  PIN xai[173]
    DIRECTION INPUT ;
    USE SIGNAL ;
    PORT
      LAYER M3 ;
        RECT  59.58 0 59.598 0.144 ;
    END
  END xai[173]
  PIN xai[174]
    DIRECTION INPUT ;
    USE SIGNAL ;
    PORT
      LAYER M5 ;
        RECT  59.856 0 59.88 0.192 ;
    END
  END xai[174]
  PIN xai[175]
    DIRECTION INPUT ;
    USE SIGNAL ;
    PORT
      LAYER M3 ;
        RECT  60.156 0 60.174 0.144 ;
    END
  END xai[175]
  PIN xai[176]
    DIRECTION INPUT ;
    USE SIGNAL ;
    PORT
      LAYER M5 ;
        RECT  60.432 0 60.456 0.192 ;
    END
  END xai[176]
  PIN xai[177]
    DIRECTION INPUT ;
    USE SIGNAL ;
    PORT
      LAYER M3 ;
        RECT  60.732 0 60.75 0.144 ;
    END
  END xai[177]
  PIN xai[178]
    DIRECTION INPUT ;
    USE SIGNAL ;
    PORT
      LAYER M5 ;
        RECT  61.008 0 61.032 0.192 ;
    END
  END xai[178]
  PIN xai[179]
    DIRECTION INPUT ;
    USE SIGNAL ;
    PORT
      LAYER M3 ;
        RECT  61.308 0 61.326 0.144 ;
    END
  END xai[179]
  PIN xai[17]
    DIRECTION INPUT ;
    USE SIGNAL ;
    PORT
      LAYER M3 ;
        RECT  14.328 0 14.346 0.144 ;
    END
  END xai[17]
  PIN xai[180]
    DIRECTION INPUT ;
    USE SIGNAL ;
    PORT
      LAYER M5 ;
        RECT  61.584 0 61.608 0.192 ;
    END
  END xai[180]
  PIN xai[181]
    DIRECTION INPUT ;
    USE SIGNAL ;
    PORT
      LAYER M3 ;
        RECT  61.884 0 61.902 0.144 ;
    END
  END xai[181]
  PIN xai[182]
    DIRECTION INPUT ;
    USE SIGNAL ;
    PORT
      LAYER M5 ;
        RECT  62.16 0 62.184 0.192 ;
    END
  END xai[182]
  PIN xai[183]
    DIRECTION INPUT ;
    USE SIGNAL ;
    PORT
      LAYER M3 ;
        RECT  62.46 0 62.478 0.144 ;
    END
  END xai[183]
  PIN xai[184]
    DIRECTION INPUT ;
    USE SIGNAL ;
    PORT
      LAYER M5 ;
        RECT  62.736 0 62.76 0.192 ;
    END
  END xai[184]
  PIN xai[185]
    DIRECTION INPUT ;
    USE SIGNAL ;
    PORT
      LAYER M3 ;
        RECT  63.036 0 63.054 0.144 ;
    END
  END xai[185]
  PIN xai[186]
    DIRECTION INPUT ;
    USE SIGNAL ;
    PORT
      LAYER M5 ;
        RECT  63.312 0 63.336 0.192 ;
    END
  END xai[186]
  PIN xai[187]
    DIRECTION INPUT ;
    USE SIGNAL ;
    PORT
      LAYER M3 ;
        RECT  63.612 0 63.63 0.144 ;
    END
  END xai[187]
  PIN xai[188]
    DIRECTION INPUT ;
    USE SIGNAL ;
    PORT
      LAYER M5 ;
        RECT  63.888 0 63.912 0.192 ;
    END
  END xai[188]
  PIN xai[189]
    DIRECTION INPUT ;
    USE SIGNAL ;
    PORT
      LAYER M3 ;
        RECT  64.188 0 64.206 0.144 ;
    END
  END xai[189]
  PIN xai[18]
    DIRECTION INPUT ;
    USE SIGNAL ;
    PORT
      LAYER M5 ;
        RECT  14.592 0 14.616 0.192 ;
    END
  END xai[18]
  PIN xai[190]
    DIRECTION INPUT ;
    USE SIGNAL ;
    PORT
      LAYER M5 ;
        RECT  64.512 0 64.536 0.192 ;
    END
  END xai[190]
  PIN xai[191]
    DIRECTION INPUT ;
    USE SIGNAL ;
    PORT
      LAYER M3 ;
        RECT  64.8 0 64.818 0.144 ;
    END
  END xai[191]
  PIN xai[192]
    DIRECTION INPUT ;
    USE SIGNAL ;
    PORT
      LAYER M5 ;
        RECT  65.088 0 65.112 0.192 ;
    END
  END xai[192]
  PIN xai[193]
    DIRECTION INPUT ;
    USE SIGNAL ;
    PORT
      LAYER M3 ;
        RECT  65.376 0 65.394 0.144 ;
    END
  END xai[193]
  PIN xai[194]
    DIRECTION INPUT ;
    USE SIGNAL ;
    PORT
      LAYER M5 ;
        RECT  65.664 0 65.688 0.192 ;
    END
  END xai[194]
  PIN xai[195]
    DIRECTION INPUT ;
    USE SIGNAL ;
    PORT
      LAYER M3 ;
        RECT  65.952 0 65.97 0.144 ;
    END
  END xai[195]
  PIN xai[196]
    DIRECTION INPUT ;
    USE SIGNAL ;
    PORT
      LAYER M5 ;
        RECT  66.24 0 66.264 0.192 ;
    END
  END xai[196]
  PIN xai[197]
    DIRECTION INPUT ;
    USE SIGNAL ;
    PORT
      LAYER M3 ;
        RECT  66.528 0 66.546 0.144 ;
    END
  END xai[197]
  PIN xai[198]
    DIRECTION INPUT ;
    USE SIGNAL ;
    PORT
      LAYER M5 ;
        RECT  66.816 0 66.84 0.192 ;
    END
  END xai[198]
  PIN xai[199]
    DIRECTION INPUT ;
    USE SIGNAL ;
    PORT
      LAYER M3 ;
        RECT  67.104 0 67.122 0.144 ;
    END
  END xai[199]
  PIN xai[19]
    DIRECTION INPUT ;
    USE SIGNAL ;
    PORT
      LAYER M3 ;
        RECT  14.904 0 14.922 0.144 ;
    END
  END xai[19]
  PIN xai[1]
    DIRECTION INPUT ;
    USE SIGNAL ;
    PORT
      LAYER M3 ;
        RECT  9.684 0 9.702 0.144 ;
    END
  END xai[1]
  PIN xai[200]
    DIRECTION INPUT ;
    USE SIGNAL ;
    PORT
      LAYER M5 ;
        RECT  67.392 0 67.416 0.192 ;
    END
  END xai[200]
  PIN xai[201]
    DIRECTION INPUT ;
    USE SIGNAL ;
    PORT
      LAYER M3 ;
        RECT  67.68 0 67.698 0.144 ;
    END
  END xai[201]
  PIN xai[202]
    DIRECTION INPUT ;
    USE SIGNAL ;
    PORT
      LAYER M5 ;
        RECT  67.968 0 67.992 0.192 ;
    END
  END xai[202]
  PIN xai[203]
    DIRECTION INPUT ;
    USE SIGNAL ;
    PORT
      LAYER M3 ;
        RECT  68.256 0 68.274 0.144 ;
    END
  END xai[203]
  PIN xai[204]
    DIRECTION INPUT ;
    USE SIGNAL ;
    PORT
      LAYER M5 ;
        RECT  68.544 0 68.568 0.192 ;
    END
  END xai[204]
  PIN xai[205]
    DIRECTION INPUT ;
    USE SIGNAL ;
    PORT
      LAYER M3 ;
        RECT  68.832 0 68.85 0.144 ;
    END
  END xai[205]
  PIN xai[206]
    DIRECTION INPUT ;
    USE SIGNAL ;
    PORT
      LAYER M5 ;
        RECT  69.12 0 69.144 0.192 ;
    END
  END xai[206]
  PIN xai[207]
    DIRECTION INPUT ;
    USE SIGNAL ;
    PORT
      LAYER M3 ;
        RECT  69.408 0 69.426 0.144 ;
    END
  END xai[207]
  PIN xai[208]
    DIRECTION INPUT ;
    USE SIGNAL ;
    PORT
      LAYER M5 ;
        RECT  69.696 0 69.72 0.192 ;
    END
  END xai[208]
  PIN xai[209]
    DIRECTION INPUT ;
    USE SIGNAL ;
    PORT
      LAYER M3 ;
        RECT  70.02 0 70.038 0.144 ;
    END
  END xai[209]
  PIN xai[20]
    DIRECTION INPUT ;
    USE SIGNAL ;
    PORT
      LAYER M5 ;
        RECT  15.168 0 15.192 0.192 ;
    END
  END xai[20]
  PIN xai[210]
    DIRECTION INPUT ;
    USE SIGNAL ;
    PORT
      LAYER M5 ;
        RECT  70.272 0 70.296 0.192 ;
    END
  END xai[210]
  PIN xai[211]
    DIRECTION INPUT ;
    USE SIGNAL ;
    PORT
      LAYER M3 ;
        RECT  70.596 0 70.614 0.144 ;
    END
  END xai[211]
  PIN xai[212]
    DIRECTION INPUT ;
    USE SIGNAL ;
    PORT
      LAYER M5 ;
        RECT  70.848 0 70.872 0.192 ;
    END
  END xai[212]
  PIN xai[213]
    DIRECTION INPUT ;
    USE SIGNAL ;
    PORT
      LAYER M3 ;
        RECT  71.172 0 71.19 0.144 ;
    END
  END xai[213]
  PIN xai[214]
    DIRECTION INPUT ;
    USE SIGNAL ;
    PORT
      LAYER M5 ;
        RECT  71.472 0 71.496 0.192 ;
    END
  END xai[214]
  PIN xai[215]
    DIRECTION INPUT ;
    USE SIGNAL ;
    PORT
      LAYER M3 ;
        RECT  71.748 0 71.766 0.144 ;
    END
  END xai[215]
  PIN xai[216]
    DIRECTION INPUT ;
    USE SIGNAL ;
    PORT
      LAYER M5 ;
        RECT  72.048 0 72.072 0.192 ;
    END
  END xai[216]
  PIN xai[217]
    DIRECTION INPUT ;
    USE SIGNAL ;
    PORT
      LAYER M3 ;
        RECT  72.324 0 72.342 0.144 ;
    END
  END xai[217]
  PIN xai[218]
    DIRECTION INPUT ;
    USE SIGNAL ;
    PORT
      LAYER M5 ;
        RECT  72.624 0 72.648 0.192 ;
    END
  END xai[218]
  PIN xai[219]
    DIRECTION INPUT ;
    USE SIGNAL ;
    PORT
      LAYER M3 ;
        RECT  72.9 0 72.918 0.144 ;
    END
  END xai[219]
  PIN xai[21]
    DIRECTION INPUT ;
    USE SIGNAL ;
    PORT
      LAYER M3 ;
        RECT  15.48 0 15.498 0.144 ;
    END
  END xai[21]
  PIN xai[220]
    DIRECTION INPUT ;
    USE SIGNAL ;
    PORT
      LAYER M5 ;
        RECT  73.2 0 73.224 0.192 ;
    END
  END xai[220]
  PIN xai[221]
    DIRECTION INPUT ;
    USE SIGNAL ;
    PORT
      LAYER M3 ;
        RECT  73.476 0 73.494 0.144 ;
    END
  END xai[221]
  PIN xai[222]
    DIRECTION INPUT ;
    USE SIGNAL ;
    PORT
      LAYER M5 ;
        RECT  73.776 0 73.8 0.192 ;
    END
  END xai[222]
  PIN xai[223]
    DIRECTION INPUT ;
    USE SIGNAL ;
    PORT
      LAYER M3 ;
        RECT  74.052 0 74.07 0.144 ;
    END
  END xai[223]
  PIN xai[224]
    DIRECTION INPUT ;
    USE SIGNAL ;
    PORT
      LAYER M5 ;
        RECT  74.352 0 74.376 0.192 ;
    END
  END xai[224]
  PIN xai[225]
    DIRECTION INPUT ;
    USE SIGNAL ;
    PORT
      LAYER M3 ;
        RECT  74.628 0 74.646 0.144 ;
    END
  END xai[225]
  PIN xai[226]
    DIRECTION INPUT ;
    USE SIGNAL ;
    PORT
      LAYER M5 ;
        RECT  74.928 0 74.952 0.192 ;
    END
  END xai[226]
  PIN xai[227]
    DIRECTION INPUT ;
    USE SIGNAL ;
    PORT
      LAYER M3 ;
        RECT  75.24 0 75.258 0.144 ;
    END
  END xai[227]
  PIN xai[228]
    DIRECTION INPUT ;
    USE SIGNAL ;
    PORT
      LAYER M5 ;
        RECT  75.504 0 75.528 0.192 ;
    END
  END xai[228]
  PIN xai[229]
    DIRECTION INPUT ;
    USE SIGNAL ;
    PORT
      LAYER M3 ;
        RECT  75.816 0 75.834 0.144 ;
    END
  END xai[229]
  PIN xai[22]
    DIRECTION INPUT ;
    USE SIGNAL ;
    PORT
      LAYER M5 ;
        RECT  15.744 0 15.768 0.192 ;
    END
  END xai[22]
  PIN xai[230]
    DIRECTION INPUT ;
    USE SIGNAL ;
    PORT
      LAYER M5 ;
        RECT  76.08 0 76.104 0.192 ;
    END
  END xai[230]
  PIN xai[231]
    DIRECTION INPUT ;
    USE SIGNAL ;
    PORT
      LAYER M3 ;
        RECT  76.392 0 76.41 0.144 ;
    END
  END xai[231]
  PIN xai[232]
    DIRECTION INPUT ;
    USE SIGNAL ;
    PORT
      LAYER M5 ;
        RECT  76.656 0 76.68 0.192 ;
    END
  END xai[232]
  PIN xai[233]
    DIRECTION INPUT ;
    USE SIGNAL ;
    PORT
      LAYER M3 ;
        RECT  76.968 0 76.986 0.144 ;
    END
  END xai[233]
  PIN xai[234]
    DIRECTION INPUT ;
    USE SIGNAL ;
    PORT
      LAYER M5 ;
        RECT  77.232 0 77.256 0.192 ;
    END
  END xai[234]
  PIN xai[235]
    DIRECTION INPUT ;
    USE SIGNAL ;
    PORT
      LAYER M3 ;
        RECT  77.544 0 77.562 0.144 ;
    END
  END xai[235]
  PIN xai[236]
    DIRECTION INPUT ;
    USE SIGNAL ;
    PORT
      LAYER M5 ;
        RECT  77.808 0 77.832 0.192 ;
    END
  END xai[236]
  PIN xai[237]
    DIRECTION INPUT ;
    USE SIGNAL ;
    PORT
      LAYER M3 ;
        RECT  78.12 0 78.138 0.144 ;
    END
  END xai[237]
  PIN xai[238]
    DIRECTION INPUT ;
    USE SIGNAL ;
    PORT
      LAYER M5 ;
        RECT  78.432 0 78.456 0.192 ;
    END
  END xai[238]
  PIN xai[239]
    DIRECTION INPUT ;
    USE SIGNAL ;
    PORT
      LAYER M3 ;
        RECT  78.696 0 78.714 0.144 ;
    END
  END xai[239]
  PIN xai[23]
    DIRECTION INPUT ;
    USE SIGNAL ;
    PORT
      LAYER M3 ;
        RECT  16.056 0 16.074 0.144 ;
    END
  END xai[23]
  PIN xai[240]
    DIRECTION INPUT ;
    USE SIGNAL ;
    PORT
      LAYER M5 ;
        RECT  79.008 0 79.032 0.192 ;
    END
  END xai[240]
  PIN xai[241]
    DIRECTION INPUT ;
    USE SIGNAL ;
    PORT
      LAYER M3 ;
        RECT  79.272 0 79.29 0.144 ;
    END
  END xai[241]
  PIN xai[242]
    DIRECTION INPUT ;
    USE SIGNAL ;
    PORT
      LAYER M5 ;
        RECT  79.584 0 79.608 0.192 ;
    END
  END xai[242]
  PIN xai[243]
    DIRECTION INPUT ;
    USE SIGNAL ;
    PORT
      LAYER M3 ;
        RECT  79.848 0 79.866 0.144 ;
    END
  END xai[243]
  PIN xai[244]
    DIRECTION INPUT ;
    USE SIGNAL ;
    PORT
      LAYER M5 ;
        RECT  80.16 0 80.184 0.192 ;
    END
  END xai[244]
  PIN xai[245]
    DIRECTION INPUT ;
    USE SIGNAL ;
    PORT
      LAYER M3 ;
        RECT  80.46 0 80.478 0.144 ;
    END
  END xai[245]
  PIN xai[246]
    DIRECTION INPUT ;
    USE SIGNAL ;
    PORT
      LAYER M5 ;
        RECT  80.736 0 80.76 0.192 ;
    END
  END xai[246]
  PIN xai[247]
    DIRECTION INPUT ;
    USE SIGNAL ;
    PORT
      LAYER M3 ;
        RECT  81.036 0 81.054 0.144 ;
    END
  END xai[247]
  PIN xai[248]
    DIRECTION INPUT ;
    USE SIGNAL ;
    PORT
      LAYER M5 ;
        RECT  81.312 0 81.336 0.192 ;
    END
  END xai[248]
  PIN xai[249]
    DIRECTION INPUT ;
    USE SIGNAL ;
    PORT
      LAYER M3 ;
        RECT  81.612 0 81.63 0.144 ;
    END
  END xai[249]
  PIN xai[24]
    DIRECTION INPUT ;
    USE SIGNAL ;
    PORT
      LAYER M5 ;
        RECT  16.368 0 16.392 0.192 ;
    END
  END xai[24]
  PIN xai[250]
    DIRECTION INPUT ;
    USE SIGNAL ;
    PORT
      LAYER M5 ;
        RECT  81.888 0 81.912 0.192 ;
    END
  END xai[250]
  PIN xai[251]
    DIRECTION INPUT ;
    USE SIGNAL ;
    PORT
      LAYER M3 ;
        RECT  82.188 0 82.206 0.144 ;
    END
  END xai[251]
  PIN xai[252]
    DIRECTION INPUT ;
    USE SIGNAL ;
    PORT
      LAYER M5 ;
        RECT  82.464 0 82.488 0.192 ;
    END
  END xai[252]
  PIN xai[253]
    DIRECTION INPUT ;
    USE SIGNAL ;
    PORT
      LAYER M3 ;
        RECT  82.764 0 82.782 0.144 ;
    END
  END xai[253]
  PIN xai[254]
    DIRECTION INPUT ;
    USE SIGNAL ;
    PORT
      LAYER M5 ;
        RECT  83.04 0 83.064 0.192 ;
    END
  END xai[254]
  PIN xai[255]
    DIRECTION INPUT ;
    USE SIGNAL ;
    PORT
      LAYER M3 ;
        RECT  83.34 0 83.358 0.144 ;
    END
  END xai[255]
  PIN xai[256]
    DIRECTION INPUT ;
    USE SIGNAL ;
    PORT
      LAYER M5 ;
        RECT  83.616 0 83.64 0.192 ;
    END
  END xai[256]
  PIN xai[257]
    DIRECTION INPUT ;
    USE SIGNAL ;
    PORT
      LAYER M3 ;
        RECT  83.916 0 83.934 0.144 ;
    END
  END xai[257]
  PIN xai[258]
    DIRECTION INPUT ;
    USE SIGNAL ;
    PORT
      LAYER M5 ;
        RECT  84.192 0 84.216 0.192 ;
    END
  END xai[258]
  PIN xai[259]
    DIRECTION INPUT ;
    USE SIGNAL ;
    PORT
      LAYER M3 ;
        RECT  84.492 0 84.51 0.144 ;
    END
  END xai[259]
  PIN xai[25]
    DIRECTION INPUT ;
    USE SIGNAL ;
    PORT
      LAYER M3 ;
        RECT  16.632 0 16.65 0.144 ;
    END
  END xai[25]
  PIN xai[260]
    DIRECTION INPUT ;
    USE SIGNAL ;
    PORT
      LAYER M5 ;
        RECT  84.816 0 84.84 0.192 ;
    END
  END xai[260]
  PIN xai[261]
    DIRECTION INPUT ;
    USE SIGNAL ;
    PORT
      LAYER M3 ;
        RECT  85.068 0 85.086 0.144 ;
    END
  END xai[261]
  PIN xai[262]
    DIRECTION INPUT ;
    USE SIGNAL ;
    PORT
      LAYER M5 ;
        RECT  85.392 0 85.416 0.192 ;
    END
  END xai[262]
  PIN xai[263]
    DIRECTION INPUT ;
    USE SIGNAL ;
    PORT
      LAYER M3 ;
        RECT  85.68 0 85.698 0.144 ;
    END
  END xai[263]
  PIN xai[264]
    DIRECTION INPUT ;
    USE SIGNAL ;
    PORT
      LAYER M5 ;
        RECT  85.968 0 85.992 0.192 ;
    END
  END xai[264]
  PIN xai[265]
    DIRECTION INPUT ;
    USE SIGNAL ;
    PORT
      LAYER M3 ;
        RECT  86.256 0 86.274 0.144 ;
    END
  END xai[265]
  PIN xai[266]
    DIRECTION INPUT ;
    USE SIGNAL ;
    PORT
      LAYER M5 ;
        RECT  86.544 0 86.568 0.192 ;
    END
  END xai[266]
  PIN xai[267]
    DIRECTION INPUT ;
    USE SIGNAL ;
    PORT
      LAYER M3 ;
        RECT  86.832 0 86.85 0.144 ;
    END
  END xai[267]
  PIN xai[268]
    DIRECTION INPUT ;
    USE SIGNAL ;
    PORT
      LAYER M5 ;
        RECT  87.12 0 87.144 0.192 ;
    END
  END xai[268]
  PIN xai[269]
    DIRECTION INPUT ;
    USE SIGNAL ;
    PORT
      LAYER M3 ;
        RECT  87.408 0 87.426 0.144 ;
    END
  END xai[269]
  PIN xai[26]
    DIRECTION INPUT ;
    USE SIGNAL ;
    PORT
      LAYER M5 ;
        RECT  16.944 0 16.968 0.192 ;
    END
  END xai[26]
  PIN xai[270]
    DIRECTION INPUT ;
    USE SIGNAL ;
    PORT
      LAYER M5 ;
        RECT  87.696 0 87.72 0.192 ;
    END
  END xai[270]
  PIN xai[271]
    DIRECTION INPUT ;
    USE SIGNAL ;
    PORT
      LAYER M3 ;
        RECT  87.984 0 88.002 0.144 ;
    END
  END xai[271]
  PIN xai[272]
    DIRECTION INPUT ;
    USE SIGNAL ;
    PORT
      LAYER M5 ;
        RECT  88.272 0 88.296 0.192 ;
    END
  END xai[272]
  PIN xai[273]
    DIRECTION INPUT ;
    USE SIGNAL ;
    PORT
      LAYER M3 ;
        RECT  88.56 0 88.578 0.144 ;
    END
  END xai[273]
  PIN xai[274]
    DIRECTION INPUT ;
    USE SIGNAL ;
    PORT
      LAYER M5 ;
        RECT  88.848 0 88.872 0.192 ;
    END
  END xai[274]
  PIN xai[275]
    DIRECTION INPUT ;
    USE SIGNAL ;
    PORT
      LAYER M3 ;
        RECT  89.136 0 89.154 0.144 ;
    END
  END xai[275]
  PIN xai[276]
    DIRECTION INPUT ;
    USE SIGNAL ;
    PORT
      LAYER M5 ;
        RECT  89.424 0 89.448 0.192 ;
    END
  END xai[276]
  PIN xai[277]
    DIRECTION INPUT ;
    USE SIGNAL ;
    PORT
      LAYER M3 ;
        RECT  89.712 0 89.73 0.144 ;
    END
  END xai[277]
  PIN xai[278]
    DIRECTION INPUT ;
    USE SIGNAL ;
    PORT
      LAYER M5 ;
        RECT  90 0 90.024 0.192 ;
    END
  END xai[278]
  PIN xai[279]
    DIRECTION INPUT ;
    USE SIGNAL ;
    PORT
      LAYER M3 ;
        RECT  90.324 0 90.342 0.144 ;
    END
  END xai[279]
  PIN xai[27]
    DIRECTION INPUT ;
    USE SIGNAL ;
    PORT
      LAYER M3 ;
        RECT  17.208 0 17.226 0.144 ;
    END
  END xai[27]
  PIN xai[280]
    DIRECTION INPUT ;
    USE SIGNAL ;
    PORT
      LAYER M5 ;
        RECT  90.576 0 90.6 0.192 ;
    END
  END xai[280]
  PIN xai[281]
    DIRECTION INPUT ;
    USE SIGNAL ;
    PORT
      LAYER M3 ;
        RECT  90.9 0 90.918 0.144 ;
    END
  END xai[281]
  PIN xai[282]
    DIRECTION INPUT ;
    USE SIGNAL ;
    PORT
      LAYER M5 ;
        RECT  91.152 0 91.176 0.192 ;
    END
  END xai[282]
  PIN xai[28]
    DIRECTION INPUT ;
    USE SIGNAL ;
    PORT
      LAYER M5 ;
        RECT  17.52 0 17.544 0.192 ;
    END
  END xai[28]
  PIN xai[29]
    DIRECTION INPUT ;
    USE SIGNAL ;
    PORT
      LAYER M3 ;
        RECT  17.784 0 17.802 0.144 ;
    END
  END xai[29]
  PIN xai[2]
    DIRECTION INPUT ;
    USE SIGNAL ;
    PORT
      LAYER M5 ;
        RECT  9.984 0 10.008 0.192 ;
    END
  END xai[2]
  PIN xai[30]
    DIRECTION INPUT ;
    USE SIGNAL ;
    PORT
      LAYER M5 ;
        RECT  18.096 0 18.12 0.192 ;
    END
  END xai[30]
  PIN xai[31]
    DIRECTION INPUT ;
    USE SIGNAL ;
    PORT
      LAYER M3 ;
        RECT  18.36 0 18.378 0.144 ;
    END
  END xai[31]
  PIN xai[32]
    DIRECTION INPUT ;
    USE SIGNAL ;
    PORT
      LAYER M5 ;
        RECT  18.672 0 18.696 0.192 ;
    END
  END xai[32]
  PIN xai[33]
    DIRECTION INPUT ;
    USE SIGNAL ;
    PORT
      LAYER M3 ;
        RECT  18.972 0 18.99 0.144 ;
    END
  END xai[33]
  PIN xai[34]
    DIRECTION INPUT ;
    USE SIGNAL ;
    PORT
      LAYER M5 ;
        RECT  19.248 0 19.272 0.192 ;
    END
  END xai[34]
  PIN xai[35]
    DIRECTION INPUT ;
    USE SIGNAL ;
    PORT
      LAYER M3 ;
        RECT  19.548 0 19.566 0.144 ;
    END
  END xai[35]
  PIN xai[36]
    DIRECTION INPUT ;
    USE SIGNAL ;
    PORT
      LAYER M5 ;
        RECT  19.824 0 19.848 0.192 ;
    END
  END xai[36]
  PIN xai[37]
    DIRECTION INPUT ;
    USE SIGNAL ;
    PORT
      LAYER M3 ;
        RECT  20.124 0 20.142 0.144 ;
    END
  END xai[37]
  PIN xai[38]
    DIRECTION INPUT ;
    USE SIGNAL ;
    PORT
      LAYER M5 ;
        RECT  20.4 0 20.424 0.192 ;
    END
  END xai[38]
  PIN xai[39]
    DIRECTION INPUT ;
    USE SIGNAL ;
    PORT
      LAYER M3 ;
        RECT  20.7 0 20.718 0.144 ;
    END
  END xai[39]
  PIN xai[3]
    DIRECTION INPUT ;
    USE SIGNAL ;
    PORT
      LAYER M3 ;
        RECT  10.26 0 10.278 0.144 ;
    END
  END xai[3]
  PIN xai[40]
    DIRECTION INPUT ;
    USE SIGNAL ;
    PORT
      LAYER M5 ;
        RECT  20.976 0 21 0.192 ;
    END
  END xai[40]
  PIN xai[41]
    DIRECTION INPUT ;
    USE SIGNAL ;
    PORT
      LAYER M3 ;
        RECT  21.276 0 21.294 0.144 ;
    END
  END xai[41]
  PIN xai[42]
    DIRECTION INPUT ;
    USE SIGNAL ;
    PORT
      LAYER M5 ;
        RECT  21.552 0 21.576 0.192 ;
    END
  END xai[42]
  PIN xai[43]
    DIRECTION INPUT ;
    USE SIGNAL ;
    PORT
      LAYER M3 ;
        RECT  21.852 0 21.87 0.144 ;
    END
  END xai[43]
  PIN xai[44]
    DIRECTION INPUT ;
    USE SIGNAL ;
    PORT
      LAYER M5 ;
        RECT  22.128 0 22.152 0.192 ;
    END
  END xai[44]
  PIN xai[45]
    DIRECTION INPUT ;
    USE SIGNAL ;
    PORT
      LAYER M3 ;
        RECT  22.428 0 22.446 0.144 ;
    END
  END xai[45]
  PIN xai[46]
    DIRECTION INPUT ;
    USE SIGNAL ;
    PORT
      LAYER M5 ;
        RECT  22.704 0 22.728 0.192 ;
    END
  END xai[46]
  PIN xai[47]
    DIRECTION INPUT ;
    USE SIGNAL ;
    PORT
      LAYER M3 ;
        RECT  23.004 0 23.022 0.144 ;
    END
  END xai[47]
  PIN xai[48]
    DIRECTION INPUT ;
    USE SIGNAL ;
    PORT
      LAYER M5 ;
        RECT  23.328 0 23.352 0.192 ;
    END
  END xai[48]
  PIN xai[49]
    DIRECTION INPUT ;
    USE SIGNAL ;
    PORT
      LAYER M3 ;
        RECT  23.616 0 23.634 0.144 ;
    END
  END xai[49]
  PIN xai[4]
    DIRECTION INPUT ;
    USE SIGNAL ;
    PORT
      LAYER M5 ;
        RECT  10.56 0 10.584 0.192 ;
    END
  END xai[4]
  PIN xai[50]
    DIRECTION INPUT ;
    USE SIGNAL ;
    PORT
      LAYER M5 ;
        RECT  23.904 0 23.928 0.192 ;
    END
  END xai[50]
  PIN xai[51]
    DIRECTION INPUT ;
    USE SIGNAL ;
    PORT
      LAYER M3 ;
        RECT  24.192 0 24.21 0.144 ;
    END
  END xai[51]
  PIN xai[52]
    DIRECTION INPUT ;
    USE SIGNAL ;
    PORT
      LAYER M5 ;
        RECT  24.48 0 24.504 0.192 ;
    END
  END xai[52]
  PIN xai[53]
    DIRECTION INPUT ;
    USE SIGNAL ;
    PORT
      LAYER M3 ;
        RECT  24.768 0 24.786 0.144 ;
    END
  END xai[53]
  PIN xai[54]
    DIRECTION INPUT ;
    USE SIGNAL ;
    PORT
      LAYER M5 ;
        RECT  25.056 0 25.08 0.192 ;
    END
  END xai[54]
  PIN xai[55]
    DIRECTION INPUT ;
    USE SIGNAL ;
    PORT
      LAYER M3 ;
        RECT  25.344 0 25.362 0.144 ;
    END
  END xai[55]
  PIN xai[56]
    DIRECTION INPUT ;
    USE SIGNAL ;
    PORT
      LAYER M5 ;
        RECT  25.632 0 25.656 0.192 ;
    END
  END xai[56]
  PIN xai[57]
    DIRECTION INPUT ;
    USE SIGNAL ;
    PORT
      LAYER M3 ;
        RECT  25.92 0 25.938 0.144 ;
    END
  END xai[57]
  PIN xai[58]
    DIRECTION INPUT ;
    USE SIGNAL ;
    PORT
      LAYER M5 ;
        RECT  26.208 0 26.232 0.192 ;
    END
  END xai[58]
  PIN xai[59]
    DIRECTION INPUT ;
    USE SIGNAL ;
    PORT
      LAYER M3 ;
        RECT  26.496 0 26.514 0.144 ;
    END
  END xai[59]
  PIN xai[5]
    DIRECTION INPUT ;
    USE SIGNAL ;
    PORT
      LAYER M3 ;
        RECT  10.836 0 10.854 0.144 ;
    END
  END xai[5]
  PIN xai[60]
    DIRECTION INPUT ;
    USE SIGNAL ;
    PORT
      LAYER M5 ;
        RECT  26.784 0 26.808 0.192 ;
    END
  END xai[60]
  PIN xai[61]
    DIRECTION INPUT ;
    USE SIGNAL ;
    PORT
      LAYER M3 ;
        RECT  27.072 0 27.09 0.144 ;
    END
  END xai[61]
  PIN xai[62]
    DIRECTION INPUT ;
    USE SIGNAL ;
    PORT
      LAYER M5 ;
        RECT  27.36 0 27.384 0.192 ;
    END
  END xai[62]
  PIN xai[63]
    DIRECTION INPUT ;
    USE SIGNAL ;
    PORT
      LAYER M3 ;
        RECT  27.648 0 27.666 0.144 ;
    END
  END xai[63]
  PIN xai[64]
    DIRECTION INPUT ;
    USE SIGNAL ;
    PORT
      LAYER M5 ;
        RECT  27.936 0 27.96 0.192 ;
    END
  END xai[64]
  PIN xai[65]
    DIRECTION INPUT ;
    USE SIGNAL ;
    PORT
      LAYER M3 ;
        RECT  28.224 0 28.242 0.144 ;
    END
  END xai[65]
  PIN xai[66]
    DIRECTION INPUT ;
    USE SIGNAL ;
    PORT
      LAYER M5 ;
        RECT  28.512 0 28.536 0.192 ;
    END
  END xai[66]
  PIN xai[67]
    DIRECTION INPUT ;
    USE SIGNAL ;
    PORT
      LAYER M3 ;
        RECT  28.836 0 28.854 0.144 ;
    END
  END xai[67]
  PIN xai[68]
    DIRECTION INPUT ;
    USE SIGNAL ;
    PORT
      LAYER M5 ;
        RECT  29.088 0 29.112 0.192 ;
    END
  END xai[68]
  PIN xai[69]
    DIRECTION INPUT ;
    USE SIGNAL ;
    PORT
      LAYER M3 ;
        RECT  29.412 0 29.43 0.144 ;
    END
  END xai[69]
  PIN xai[6]
    DIRECTION INPUT ;
    USE SIGNAL ;
    PORT
      LAYER M5 ;
        RECT  11.136 0 11.16 0.192 ;
    END
  END xai[6]
  PIN xai[70]
    DIRECTION INPUT ;
    USE SIGNAL ;
    PORT
      LAYER M5 ;
        RECT  29.664 0 29.688 0.192 ;
    END
  END xai[70]
  PIN xai[71]
    DIRECTION INPUT ;
    USE SIGNAL ;
    PORT
      LAYER M3 ;
        RECT  29.988 0 30.006 0.144 ;
    END
  END xai[71]
  PIN xai[72]
    DIRECTION INPUT ;
    USE SIGNAL ;
    PORT
      LAYER M5 ;
        RECT  30.288 0 30.312 0.192 ;
    END
  END xai[72]
  PIN xai[73]
    DIRECTION INPUT ;
    USE SIGNAL ;
    PORT
      LAYER M3 ;
        RECT  30.564 0 30.582 0.144 ;
    END
  END xai[73]
  PIN xai[74]
    DIRECTION INPUT ;
    USE SIGNAL ;
    PORT
      LAYER M5 ;
        RECT  30.864 0 30.888 0.192 ;
    END
  END xai[74]
  PIN xai[75]
    DIRECTION INPUT ;
    USE SIGNAL ;
    PORT
      LAYER M3 ;
        RECT  31.14 0 31.158 0.144 ;
    END
  END xai[75]
  PIN xai[76]
    DIRECTION INPUT ;
    USE SIGNAL ;
    PORT
      LAYER M5 ;
        RECT  31.44 0 31.464 0.192 ;
    END
  END xai[76]
  PIN xai[77]
    DIRECTION INPUT ;
    USE SIGNAL ;
    PORT
      LAYER M3 ;
        RECT  31.716 0 31.734 0.144 ;
    END
  END xai[77]
  PIN xai[78]
    DIRECTION INPUT ;
    USE SIGNAL ;
    PORT
      LAYER M5 ;
        RECT  32.016 0 32.04 0.192 ;
    END
  END xai[78]
  PIN xai[79]
    DIRECTION INPUT ;
    USE SIGNAL ;
    PORT
      LAYER M3 ;
        RECT  32.292 0 32.31 0.144 ;
    END
  END xai[79]
  PIN xai[7]
    DIRECTION INPUT ;
    USE SIGNAL ;
    PORT
      LAYER M3 ;
        RECT  11.412 0 11.43 0.144 ;
    END
  END xai[7]
  PIN xai[80]
    DIRECTION INPUT ;
    USE SIGNAL ;
    PORT
      LAYER M5 ;
        RECT  32.592 0 32.616 0.192 ;
    END
  END xai[80]
  PIN xai[81]
    DIRECTION INPUT ;
    USE SIGNAL ;
    PORT
      LAYER M3 ;
        RECT  32.868 0 32.886 0.144 ;
    END
  END xai[81]
  PIN xai[82]
    DIRECTION INPUT ;
    USE SIGNAL ;
    PORT
      LAYER M5 ;
        RECT  33.168 0 33.192 0.192 ;
    END
  END xai[82]
  PIN xai[83]
    DIRECTION INPUT ;
    USE SIGNAL ;
    PORT
      LAYER M3 ;
        RECT  33.444 0 33.462 0.144 ;
    END
  END xai[83]
  PIN xai[84]
    DIRECTION INPUT ;
    USE SIGNAL ;
    PORT
      LAYER M5 ;
        RECT  33.744 0 33.768 0.192 ;
    END
  END xai[84]
  PIN xai[85]
    DIRECTION INPUT ;
    USE SIGNAL ;
    PORT
      LAYER M3 ;
        RECT  34.056 0 34.074 0.144 ;
    END
  END xai[85]
  PIN xai[86]
    DIRECTION INPUT ;
    USE SIGNAL ;
    PORT
      LAYER M5 ;
        RECT  34.32 0 34.344 0.192 ;
    END
  END xai[86]
  PIN xai[87]
    DIRECTION INPUT ;
    USE SIGNAL ;
    PORT
      LAYER M3 ;
        RECT  34.632 0 34.65 0.144 ;
    END
  END xai[87]
  PIN xai[88]
    DIRECTION INPUT ;
    USE SIGNAL ;
    PORT
      LAYER M5 ;
        RECT  34.896 0 34.92 0.192 ;
    END
  END xai[88]
  PIN xai[89]
    DIRECTION INPUT ;
    USE SIGNAL ;
    PORT
      LAYER M3 ;
        RECT  35.208 0 35.226 0.144 ;
    END
  END xai[89]
  PIN xai[8]
    DIRECTION INPUT ;
    USE SIGNAL ;
    PORT
      LAYER M5 ;
        RECT  11.712 0 11.736 0.192 ;
    END
  END xai[8]
  PIN xai[90]
    DIRECTION INPUT ;
    USE SIGNAL ;
    PORT
      LAYER M5 ;
        RECT  35.472 0 35.496 0.192 ;
    END
  END xai[90]
  PIN xai[91]
    DIRECTION INPUT ;
    USE SIGNAL ;
    PORT
      LAYER M3 ;
        RECT  35.784 0 35.802 0.144 ;
    END
  END xai[91]
  PIN xai[92]
    DIRECTION INPUT ;
    USE SIGNAL ;
    PORT
      LAYER M5 ;
        RECT  36.048 0 36.072 0.192 ;
    END
  END xai[92]
  PIN xai[93]
    DIRECTION INPUT ;
    USE SIGNAL ;
    PORT
      LAYER M3 ;
        RECT  36.36 0 36.378 0.144 ;
    END
  END xai[93]
  PIN xai[94]
    DIRECTION INPUT ;
    USE SIGNAL ;
    PORT
      LAYER M5 ;
        RECT  36.624 0 36.648 0.192 ;
    END
  END xai[94]
  PIN xai[95]
    DIRECTION INPUT ;
    USE SIGNAL ;
    PORT
      LAYER M3 ;
        RECT  36.936 0 36.954 0.144 ;
    END
  END xai[95]
  PIN xai[96]
    DIRECTION INPUT ;
    USE SIGNAL ;
    PORT
      LAYER M5 ;
        RECT  37.248 0 37.272 0.192 ;
    END
  END xai[96]
  PIN xai[97]
    DIRECTION INPUT ;
    USE SIGNAL ;
    PORT
      LAYER M3 ;
        RECT  37.512 0 37.53 0.144 ;
    END
  END xai[97]
  PIN xai[98]
    DIRECTION INPUT ;
    USE SIGNAL ;
    PORT
      LAYER M5 ;
        RECT  37.824 0 37.848 0.192 ;
    END
  END xai[98]
  PIN xai[99]
    DIRECTION INPUT ;
    USE SIGNAL ;
    PORT
      LAYER M3 ;
        RECT  38.088 0 38.106 0.144 ;
    END
  END xai[99]
  PIN xai[9]
    DIRECTION INPUT ;
    USE SIGNAL ;
    PORT
      LAYER M3 ;
        RECT  11.988 0 12.006 0.144 ;
    END
  END xai[9]
  PIN xb[0]
    DIRECTION OUTPUT ;
    USE SIGNAL ;
    PORT
      LAYER M3 ;
        RECT  92.016 30.096 92.034 30.24 ;
    END
  END xb[0]
  PIN xb[100]
    DIRECTION OUTPUT ;
    USE SIGNAL ;
    PORT
      LAYER M3 ;
        RECT  120.816 30.096 120.834 30.24 ;
    END
  END xb[100]
  PIN xb[101]
    DIRECTION OUTPUT ;
    USE SIGNAL ;
    PORT
      LAYER M5 ;
        RECT  121.104 30.048 121.128 30.24 ;
    END
  END xb[101]
  PIN xb[102]
    DIRECTION OUTPUT ;
    USE SIGNAL ;
    PORT
      LAYER M3 ;
        RECT  121.392 30.096 121.41 30.24 ;
    END
  END xb[102]
  PIN xb[103]
    DIRECTION OUTPUT ;
    USE SIGNAL ;
    PORT
      LAYER M5 ;
        RECT  121.68 30.048 121.704 30.24 ;
    END
  END xb[103]
  PIN xb[104]
    DIRECTION OUTPUT ;
    USE SIGNAL ;
    PORT
      LAYER M3 ;
        RECT  121.968 30.096 121.986 30.24 ;
    END
  END xb[104]
  PIN xb[105]
    DIRECTION OUTPUT ;
    USE SIGNAL ;
    PORT
      LAYER M5 ;
        RECT  122.256 30.048 122.28 30.24 ;
    END
  END xb[105]
  PIN xb[106]
    DIRECTION OUTPUT ;
    USE SIGNAL ;
    PORT
      LAYER M3 ;
        RECT  122.544 30.096 122.562 30.24 ;
    END
  END xb[106]
  PIN xb[107]
    DIRECTION OUTPUT ;
    USE SIGNAL ;
    PORT
      LAYER M5 ;
        RECT  122.832 30.048 122.856 30.24 ;
    END
  END xb[107]
  PIN xb[108]
    DIRECTION OUTPUT ;
    USE SIGNAL ;
    PORT
      LAYER M3 ;
        RECT  123.12 30.096 123.138 30.24 ;
    END
  END xb[108]
  PIN xb[109]
    DIRECTION OUTPUT ;
    USE SIGNAL ;
    PORT
      LAYER M5 ;
        RECT  123.408 30.048 123.432 30.24 ;
    END
  END xb[109]
  PIN xb[10]
    DIRECTION OUTPUT ;
    USE SIGNAL ;
    PORT
      LAYER M3 ;
        RECT  94.896 30.096 94.914 30.24 ;
    END
  END xb[10]
  PIN xb[110]
    DIRECTION OUTPUT ;
    USE SIGNAL ;
    PORT
      LAYER M3 ;
        RECT  123.696 30.096 123.714 30.24 ;
    END
  END xb[110]
  PIN xb[111]
    DIRECTION OUTPUT ;
    USE SIGNAL ;
    PORT
      LAYER M5 ;
        RECT  123.984 30.048 124.008 30.24 ;
    END
  END xb[111]
  PIN xb[112]
    DIRECTION OUTPUT ;
    USE SIGNAL ;
    PORT
      LAYER M3 ;
        RECT  124.272 30.096 124.29 30.24 ;
    END
  END xb[112]
  PIN xb[113]
    DIRECTION OUTPUT ;
    USE SIGNAL ;
    PORT
      LAYER M5 ;
        RECT  124.56 30.048 124.584 30.24 ;
    END
  END xb[113]
  PIN xb[114]
    DIRECTION OUTPUT ;
    USE SIGNAL ;
    PORT
      LAYER M3 ;
        RECT  124.848 30.096 124.866 30.24 ;
    END
  END xb[114]
  PIN xb[115]
    DIRECTION OUTPUT ;
    USE SIGNAL ;
    PORT
      LAYER M5 ;
        RECT  125.136 30.048 125.16 30.24 ;
    END
  END xb[115]
  PIN xb[116]
    DIRECTION OUTPUT ;
    USE SIGNAL ;
    PORT
      LAYER M3 ;
        RECT  125.424 30.096 125.442 30.24 ;
    END
  END xb[116]
  PIN xb[117]
    DIRECTION OUTPUT ;
    USE SIGNAL ;
    PORT
      LAYER M5 ;
        RECT  125.712 30.048 125.736 30.24 ;
    END
  END xb[117]
  PIN xb[118]
    DIRECTION OUTPUT ;
    USE SIGNAL ;
    PORT
      LAYER M3 ;
        RECT  126 30.096 126.018 30.24 ;
    END
  END xb[118]
  PIN xb[119]
    DIRECTION OUTPUT ;
    USE SIGNAL ;
    PORT
      LAYER M5 ;
        RECT  126.288 30.048 126.312 30.24 ;
    END
  END xb[119]
  PIN xb[11]
    DIRECTION OUTPUT ;
    USE SIGNAL ;
    PORT
      LAYER M5 ;
        RECT  95.184 30.048 95.208 30.24 ;
    END
  END xb[11]
  PIN xb[120]
    DIRECTION OUTPUT ;
    USE SIGNAL ;
    PORT
      LAYER M3 ;
        RECT  126.576 30.096 126.594 30.24 ;
    END
  END xb[120]
  PIN xb[121]
    DIRECTION OUTPUT ;
    USE SIGNAL ;
    PORT
      LAYER M5 ;
        RECT  126.864 30.048 126.888 30.24 ;
    END
  END xb[121]
  PIN xb[122]
    DIRECTION OUTPUT ;
    USE SIGNAL ;
    PORT
      LAYER M3 ;
        RECT  127.152 30.096 127.17 30.24 ;
    END
  END xb[122]
  PIN xb[123]
    DIRECTION OUTPUT ;
    USE SIGNAL ;
    PORT
      LAYER M5 ;
        RECT  127.44 30.048 127.464 30.24 ;
    END
  END xb[123]
  PIN xb[124]
    DIRECTION OUTPUT ;
    USE SIGNAL ;
    PORT
      LAYER M3 ;
        RECT  127.728 30.096 127.746 30.24 ;
    END
  END xb[124]
  PIN xb[125]
    DIRECTION OUTPUT ;
    USE SIGNAL ;
    PORT
      LAYER M5 ;
        RECT  128.016 30.048 128.04 30.24 ;
    END
  END xb[125]
  PIN xb[126]
    DIRECTION OUTPUT ;
    USE SIGNAL ;
    PORT
      LAYER M3 ;
        RECT  128.304 30.096 128.322 30.24 ;
    END
  END xb[126]
  PIN xb[127]
    DIRECTION OUTPUT ;
    USE SIGNAL ;
    PORT
      LAYER M5 ;
        RECT  128.592 30.048 128.616 30.24 ;
    END
  END xb[127]
  PIN xb[128]
    DIRECTION OUTPUT ;
    USE SIGNAL ;
    PORT
      LAYER M3 ;
        RECT  128.88 30.096 128.898 30.24 ;
    END
  END xb[128]
  PIN xb[129]
    DIRECTION OUTPUT ;
    USE SIGNAL ;
    PORT
      LAYER M5 ;
        RECT  129.168 30.048 129.192 30.24 ;
    END
  END xb[129]
  PIN xb[12]
    DIRECTION OUTPUT ;
    USE SIGNAL ;
    PORT
      LAYER M3 ;
        RECT  95.472 30.096 95.49 30.24 ;
    END
  END xb[12]
  PIN xb[130]
    DIRECTION OUTPUT ;
    USE SIGNAL ;
    PORT
      LAYER M3 ;
        RECT  129.456 30.096 129.474 30.24 ;
    END
  END xb[130]
  PIN xb[131]
    DIRECTION OUTPUT ;
    USE SIGNAL ;
    PORT
      LAYER M5 ;
        RECT  129.744 30.048 129.768 30.24 ;
    END
  END xb[131]
  PIN xb[132]
    DIRECTION OUTPUT ;
    USE SIGNAL ;
    PORT
      LAYER M3 ;
        RECT  130.032 30.096 130.05 30.24 ;
    END
  END xb[132]
  PIN xb[133]
    DIRECTION OUTPUT ;
    USE SIGNAL ;
    PORT
      LAYER M5 ;
        RECT  130.32 30.048 130.344 30.24 ;
    END
  END xb[133]
  PIN xb[134]
    DIRECTION OUTPUT ;
    USE SIGNAL ;
    PORT
      LAYER M3 ;
        RECT  130.608 30.096 130.626 30.24 ;
    END
  END xb[134]
  PIN xb[135]
    DIRECTION OUTPUT ;
    USE SIGNAL ;
    PORT
      LAYER M5 ;
        RECT  130.896 30.048 130.92 30.24 ;
    END
  END xb[135]
  PIN xb[136]
    DIRECTION OUTPUT ;
    USE SIGNAL ;
    PORT
      LAYER M3 ;
        RECT  131.184 30.096 131.202 30.24 ;
    END
  END xb[136]
  PIN xb[137]
    DIRECTION OUTPUT ;
    USE SIGNAL ;
    PORT
      LAYER M5 ;
        RECT  131.472 30.048 131.496 30.24 ;
    END
  END xb[137]
  PIN xb[138]
    DIRECTION OUTPUT ;
    USE SIGNAL ;
    PORT
      LAYER M3 ;
        RECT  131.76 30.096 131.778 30.24 ;
    END
  END xb[138]
  PIN xb[139]
    DIRECTION OUTPUT ;
    USE SIGNAL ;
    PORT
      LAYER M5 ;
        RECT  132.048 30.048 132.072 30.24 ;
    END
  END xb[139]
  PIN xb[13]
    DIRECTION OUTPUT ;
    USE SIGNAL ;
    PORT
      LAYER M5 ;
        RECT  95.76 30.048 95.784 30.24 ;
    END
  END xb[13]
  PIN xb[140]
    DIRECTION OUTPUT ;
    USE SIGNAL ;
    PORT
      LAYER M3 ;
        RECT  132.336 30.096 132.354 30.24 ;
    END
  END xb[140]
  PIN xb[141]
    DIRECTION OUTPUT ;
    USE SIGNAL ;
    PORT
      LAYER M5 ;
        RECT  132.624 30.048 132.648 30.24 ;
    END
  END xb[141]
  PIN xb[142]
    DIRECTION OUTPUT ;
    USE SIGNAL ;
    PORT
      LAYER M3 ;
        RECT  132.912 30.096 132.93 30.24 ;
    END
  END xb[142]
  PIN xb[143]
    DIRECTION OUTPUT ;
    USE SIGNAL ;
    PORT
      LAYER M5 ;
        RECT  133.2 30.048 133.224 30.24 ;
    END
  END xb[143]
  PIN xb[144]
    DIRECTION OUTPUT ;
    USE SIGNAL ;
    PORT
      LAYER M3 ;
        RECT  133.488 30.096 133.506 30.24 ;
    END
  END xb[144]
  PIN xb[145]
    DIRECTION OUTPUT ;
    USE SIGNAL ;
    PORT
      LAYER M5 ;
        RECT  133.776 30.048 133.8 30.24 ;
    END
  END xb[145]
  PIN xb[146]
    DIRECTION OUTPUT ;
    USE SIGNAL ;
    PORT
      LAYER M3 ;
        RECT  134.064 30.096 134.082 30.24 ;
    END
  END xb[146]
  PIN xb[147]
    DIRECTION OUTPUT ;
    USE SIGNAL ;
    PORT
      LAYER M5 ;
        RECT  134.352 30.048 134.376 30.24 ;
    END
  END xb[147]
  PIN xb[148]
    DIRECTION OUTPUT ;
    USE SIGNAL ;
    PORT
      LAYER M3 ;
        RECT  134.64 30.096 134.658 30.24 ;
    END
  END xb[148]
  PIN xb[149]
    DIRECTION OUTPUT ;
    USE SIGNAL ;
    PORT
      LAYER M5 ;
        RECT  134.928 30.048 134.952 30.24 ;
    END
  END xb[149]
  PIN xb[14]
    DIRECTION OUTPUT ;
    USE SIGNAL ;
    PORT
      LAYER M3 ;
        RECT  96.048 30.096 96.066 30.24 ;
    END
  END xb[14]
  PIN xb[150]
    DIRECTION OUTPUT ;
    USE SIGNAL ;
    PORT
      LAYER M3 ;
        RECT  135.216 30.096 135.234 30.24 ;
    END
  END xb[150]
  PIN xb[151]
    DIRECTION OUTPUT ;
    USE SIGNAL ;
    PORT
      LAYER M5 ;
        RECT  135.504 30.048 135.528 30.24 ;
    END
  END xb[151]
  PIN xb[152]
    DIRECTION OUTPUT ;
    USE SIGNAL ;
    PORT
      LAYER M3 ;
        RECT  135.792 30.096 135.81 30.24 ;
    END
  END xb[152]
  PIN xb[153]
    DIRECTION OUTPUT ;
    USE SIGNAL ;
    PORT
      LAYER M5 ;
        RECT  136.08 30.048 136.104 30.24 ;
    END
  END xb[153]
  PIN xb[154]
    DIRECTION OUTPUT ;
    USE SIGNAL ;
    PORT
      LAYER M3 ;
        RECT  136.368 30.096 136.386 30.24 ;
    END
  END xb[154]
  PIN xb[155]
    DIRECTION OUTPUT ;
    USE SIGNAL ;
    PORT
      LAYER M5 ;
        RECT  136.656 30.048 136.68 30.24 ;
    END
  END xb[155]
  PIN xb[156]
    DIRECTION OUTPUT ;
    USE SIGNAL ;
    PORT
      LAYER M3 ;
        RECT  136.944 30.096 136.962 30.24 ;
    END
  END xb[156]
  PIN xb[157]
    DIRECTION OUTPUT ;
    USE SIGNAL ;
    PORT
      LAYER M5 ;
        RECT  137.232 30.048 137.256 30.24 ;
    END
  END xb[157]
  PIN xb[158]
    DIRECTION OUTPUT ;
    USE SIGNAL ;
    PORT
      LAYER M3 ;
        RECT  137.52 30.096 137.538 30.24 ;
    END
  END xb[158]
  PIN xb[159]
    DIRECTION OUTPUT ;
    USE SIGNAL ;
    PORT
      LAYER M5 ;
        RECT  137.808 30.048 137.832 30.24 ;
    END
  END xb[159]
  PIN xb[15]
    DIRECTION OUTPUT ;
    USE SIGNAL ;
    PORT
      LAYER M5 ;
        RECT  96.336 30.048 96.36 30.24 ;
    END
  END xb[15]
  PIN xb[160]
    DIRECTION OUTPUT ;
    USE SIGNAL ;
    PORT
      LAYER M3 ;
        RECT  138.096 30.096 138.114 30.24 ;
    END
  END xb[160]
  PIN xb[161]
    DIRECTION OUTPUT ;
    USE SIGNAL ;
    PORT
      LAYER M5 ;
        RECT  138.384 30.048 138.408 30.24 ;
    END
  END xb[161]
  PIN xb[162]
    DIRECTION OUTPUT ;
    USE SIGNAL ;
    PORT
      LAYER M3 ;
        RECT  138.672 30.096 138.69 30.24 ;
    END
  END xb[162]
  PIN xb[163]
    DIRECTION OUTPUT ;
    USE SIGNAL ;
    PORT
      LAYER M5 ;
        RECT  138.96 30.048 138.984 30.24 ;
    END
  END xb[163]
  PIN xb[164]
    DIRECTION OUTPUT ;
    USE SIGNAL ;
    PORT
      LAYER M3 ;
        RECT  139.248 30.096 139.266 30.24 ;
    END
  END xb[164]
  PIN xb[165]
    DIRECTION OUTPUT ;
    USE SIGNAL ;
    PORT
      LAYER M5 ;
        RECT  139.536 30.048 139.56 30.24 ;
    END
  END xb[165]
  PIN xb[166]
    DIRECTION OUTPUT ;
    USE SIGNAL ;
    PORT
      LAYER M3 ;
        RECT  139.824 30.096 139.842 30.24 ;
    END
  END xb[166]
  PIN xb[167]
    DIRECTION OUTPUT ;
    USE SIGNAL ;
    PORT
      LAYER M5 ;
        RECT  140.112 30.048 140.136 30.24 ;
    END
  END xb[167]
  PIN xb[168]
    DIRECTION OUTPUT ;
    USE SIGNAL ;
    PORT
      LAYER M3 ;
        RECT  140.4 30.096 140.418 30.24 ;
    END
  END xb[168]
  PIN xb[169]
    DIRECTION OUTPUT ;
    USE SIGNAL ;
    PORT
      LAYER M5 ;
        RECT  140.688 30.048 140.712 30.24 ;
    END
  END xb[169]
  PIN xb[16]
    DIRECTION OUTPUT ;
    USE SIGNAL ;
    PORT
      LAYER M3 ;
        RECT  96.624 30.096 96.642 30.24 ;
    END
  END xb[16]
  PIN xb[170]
    DIRECTION OUTPUT ;
    USE SIGNAL ;
    PORT
      LAYER M3 ;
        RECT  140.976 30.096 140.994 30.24 ;
    END
  END xb[170]
  PIN xb[171]
    DIRECTION OUTPUT ;
    USE SIGNAL ;
    PORT
      LAYER M5 ;
        RECT  141.264 30.048 141.288 30.24 ;
    END
  END xb[171]
  PIN xb[172]
    DIRECTION OUTPUT ;
    USE SIGNAL ;
    PORT
      LAYER M3 ;
        RECT  141.552 30.096 141.57 30.24 ;
    END
  END xb[172]
  PIN xb[173]
    DIRECTION OUTPUT ;
    USE SIGNAL ;
    PORT
      LAYER M5 ;
        RECT  141.84 30.048 141.864 30.24 ;
    END
  END xb[173]
  PIN xb[174]
    DIRECTION OUTPUT ;
    USE SIGNAL ;
    PORT
      LAYER M3 ;
        RECT  142.128 30.096 142.146 30.24 ;
    END
  END xb[174]
  PIN xb[175]
    DIRECTION OUTPUT ;
    USE SIGNAL ;
    PORT
      LAYER M5 ;
        RECT  142.416 30.048 142.44 30.24 ;
    END
  END xb[175]
  PIN xb[176]
    DIRECTION OUTPUT ;
    USE SIGNAL ;
    PORT
      LAYER M3 ;
        RECT  142.704 30.096 142.722 30.24 ;
    END
  END xb[176]
  PIN xb[177]
    DIRECTION OUTPUT ;
    USE SIGNAL ;
    PORT
      LAYER M5 ;
        RECT  142.992 30.048 143.016 30.24 ;
    END
  END xb[177]
  PIN xb[178]
    DIRECTION OUTPUT ;
    USE SIGNAL ;
    PORT
      LAYER M3 ;
        RECT  143.28 30.096 143.298 30.24 ;
    END
  END xb[178]
  PIN xb[179]
    DIRECTION OUTPUT ;
    USE SIGNAL ;
    PORT
      LAYER M5 ;
        RECT  143.568 30.048 143.592 30.24 ;
    END
  END xb[179]
  PIN xb[17]
    DIRECTION OUTPUT ;
    USE SIGNAL ;
    PORT
      LAYER M5 ;
        RECT  96.912 30.048 96.936 30.24 ;
    END
  END xb[17]
  PIN xb[180]
    DIRECTION OUTPUT ;
    USE SIGNAL ;
    PORT
      LAYER M3 ;
        RECT  143.856 30.096 143.874 30.24 ;
    END
  END xb[180]
  PIN xb[181]
    DIRECTION OUTPUT ;
    USE SIGNAL ;
    PORT
      LAYER M5 ;
        RECT  144.144 30.048 144.168 30.24 ;
    END
  END xb[181]
  PIN xb[182]
    DIRECTION OUTPUT ;
    USE SIGNAL ;
    PORT
      LAYER M3 ;
        RECT  144.432 30.096 144.45 30.24 ;
    END
  END xb[182]
  PIN xb[183]
    DIRECTION OUTPUT ;
    USE SIGNAL ;
    PORT
      LAYER M5 ;
        RECT  144.72 30.048 144.744 30.24 ;
    END
  END xb[183]
  PIN xb[184]
    DIRECTION OUTPUT ;
    USE SIGNAL ;
    PORT
      LAYER M3 ;
        RECT  145.008 30.096 145.026 30.24 ;
    END
  END xb[184]
  PIN xb[185]
    DIRECTION OUTPUT ;
    USE SIGNAL ;
    PORT
      LAYER M5 ;
        RECT  145.296 30.048 145.32 30.24 ;
    END
  END xb[185]
  PIN xb[186]
    DIRECTION OUTPUT ;
    USE SIGNAL ;
    PORT
      LAYER M3 ;
        RECT  145.584 30.096 145.602 30.24 ;
    END
  END xb[186]
  PIN xb[187]
    DIRECTION OUTPUT ;
    USE SIGNAL ;
    PORT
      LAYER M5 ;
        RECT  145.872 30.048 145.896 30.24 ;
    END
  END xb[187]
  PIN xb[188]
    DIRECTION OUTPUT ;
    USE SIGNAL ;
    PORT
      LAYER M3 ;
        RECT  146.16 30.096 146.178 30.24 ;
    END
  END xb[188]
  PIN xb[189]
    DIRECTION OUTPUT ;
    USE SIGNAL ;
    PORT
      LAYER M5 ;
        RECT  146.448 30.048 146.472 30.24 ;
    END
  END xb[189]
  PIN xb[18]
    DIRECTION OUTPUT ;
    USE SIGNAL ;
    PORT
      LAYER M3 ;
        RECT  97.2 30.096 97.218 30.24 ;
    END
  END xb[18]
  PIN xb[190]
    DIRECTION OUTPUT ;
    USE SIGNAL ;
    PORT
      LAYER M3 ;
        RECT  146.736 30.096 146.754 30.24 ;
    END
  END xb[190]
  PIN xb[191]
    DIRECTION OUTPUT ;
    USE SIGNAL ;
    PORT
      LAYER M5 ;
        RECT  147.024 30.048 147.048 30.24 ;
    END
  END xb[191]
  PIN xb[192]
    DIRECTION OUTPUT ;
    USE SIGNAL ;
    PORT
      LAYER M3 ;
        RECT  147.312 30.096 147.33 30.24 ;
    END
  END xb[192]
  PIN xb[193]
    DIRECTION OUTPUT ;
    USE SIGNAL ;
    PORT
      LAYER M5 ;
        RECT  147.6 30.048 147.624 30.24 ;
    END
  END xb[193]
  PIN xb[194]
    DIRECTION OUTPUT ;
    USE SIGNAL ;
    PORT
      LAYER M3 ;
        RECT  147.888 30.096 147.906 30.24 ;
    END
  END xb[194]
  PIN xb[195]
    DIRECTION OUTPUT ;
    USE SIGNAL ;
    PORT
      LAYER M5 ;
        RECT  148.176 30.048 148.2 30.24 ;
    END
  END xb[195]
  PIN xb[196]
    DIRECTION OUTPUT ;
    USE SIGNAL ;
    PORT
      LAYER M3 ;
        RECT  148.464 30.096 148.482 30.24 ;
    END
  END xb[196]
  PIN xb[197]
    DIRECTION OUTPUT ;
    USE SIGNAL ;
    PORT
      LAYER M5 ;
        RECT  148.752 30.048 148.776 30.24 ;
    END
  END xb[197]
  PIN xb[198]
    DIRECTION OUTPUT ;
    USE SIGNAL ;
    PORT
      LAYER M3 ;
        RECT  149.04 30.096 149.058 30.24 ;
    END
  END xb[198]
  PIN xb[199]
    DIRECTION OUTPUT ;
    USE SIGNAL ;
    PORT
      LAYER M5 ;
        RECT  149.328 30.048 149.352 30.24 ;
    END
  END xb[199]
  PIN xb[19]
    DIRECTION OUTPUT ;
    USE SIGNAL ;
    PORT
      LAYER M5 ;
        RECT  97.488 30.048 97.512 30.24 ;
    END
  END xb[19]
  PIN xb[1]
    DIRECTION OUTPUT ;
    USE SIGNAL ;
    PORT
      LAYER M5 ;
        RECT  92.304 30.048 92.328 30.24 ;
    END
  END xb[1]
  PIN xb[200]
    DIRECTION OUTPUT ;
    USE SIGNAL ;
    PORT
      LAYER M3 ;
        RECT  149.616 30.096 149.634 30.24 ;
    END
  END xb[200]
  PIN xb[201]
    DIRECTION OUTPUT ;
    USE SIGNAL ;
    PORT
      LAYER M5 ;
        RECT  149.904 30.048 149.928 30.24 ;
    END
  END xb[201]
  PIN xb[202]
    DIRECTION OUTPUT ;
    USE SIGNAL ;
    PORT
      LAYER M3 ;
        RECT  150.192 30.096 150.21 30.24 ;
    END
  END xb[202]
  PIN xb[203]
    DIRECTION OUTPUT ;
    USE SIGNAL ;
    PORT
      LAYER M5 ;
        RECT  150.48 30.048 150.504 30.24 ;
    END
  END xb[203]
  PIN xb[204]
    DIRECTION OUTPUT ;
    USE SIGNAL ;
    PORT
      LAYER M3 ;
        RECT  150.768 30.096 150.786 30.24 ;
    END
  END xb[204]
  PIN xb[205]
    DIRECTION OUTPUT ;
    USE SIGNAL ;
    PORT
      LAYER M5 ;
        RECT  151.056 30.048 151.08 30.24 ;
    END
  END xb[205]
  PIN xb[206]
    DIRECTION OUTPUT ;
    USE SIGNAL ;
    PORT
      LAYER M3 ;
        RECT  151.344 30.096 151.362 30.24 ;
    END
  END xb[206]
  PIN xb[207]
    DIRECTION OUTPUT ;
    USE SIGNAL ;
    PORT
      LAYER M5 ;
        RECT  151.632 30.048 151.656 30.24 ;
    END
  END xb[207]
  PIN xb[208]
    DIRECTION OUTPUT ;
    USE SIGNAL ;
    PORT
      LAYER M3 ;
        RECT  151.92 30.096 151.938 30.24 ;
    END
  END xb[208]
  PIN xb[209]
    DIRECTION OUTPUT ;
    USE SIGNAL ;
    PORT
      LAYER M5 ;
        RECT  152.208 30.048 152.232 30.24 ;
    END
  END xb[209]
  PIN xb[20]
    DIRECTION OUTPUT ;
    USE SIGNAL ;
    PORT
      LAYER M3 ;
        RECT  97.776 30.096 97.794 30.24 ;
    END
  END xb[20]
  PIN xb[210]
    DIRECTION OUTPUT ;
    USE SIGNAL ;
    PORT
      LAYER M3 ;
        RECT  152.496 30.096 152.514 30.24 ;
    END
  END xb[210]
  PIN xb[211]
    DIRECTION OUTPUT ;
    USE SIGNAL ;
    PORT
      LAYER M5 ;
        RECT  152.784 30.048 152.808 30.24 ;
    END
  END xb[211]
  PIN xb[212]
    DIRECTION OUTPUT ;
    USE SIGNAL ;
    PORT
      LAYER M3 ;
        RECT  153.072 30.096 153.09 30.24 ;
    END
  END xb[212]
  PIN xb[213]
    DIRECTION OUTPUT ;
    USE SIGNAL ;
    PORT
      LAYER M5 ;
        RECT  153.36 30.048 153.384 30.24 ;
    END
  END xb[213]
  PIN xb[214]
    DIRECTION OUTPUT ;
    USE SIGNAL ;
    PORT
      LAYER M3 ;
        RECT  153.648 30.096 153.666 30.24 ;
    END
  END xb[214]
  PIN xb[215]
    DIRECTION OUTPUT ;
    USE SIGNAL ;
    PORT
      LAYER M5 ;
        RECT  153.936 30.048 153.96 30.24 ;
    END
  END xb[215]
  PIN xb[216]
    DIRECTION OUTPUT ;
    USE SIGNAL ;
    PORT
      LAYER M3 ;
        RECT  154.224 30.096 154.242 30.24 ;
    END
  END xb[216]
  PIN xb[217]
    DIRECTION OUTPUT ;
    USE SIGNAL ;
    PORT
      LAYER M5 ;
        RECT  154.512 30.048 154.536 30.24 ;
    END
  END xb[217]
  PIN xb[218]
    DIRECTION OUTPUT ;
    USE SIGNAL ;
    PORT
      LAYER M3 ;
        RECT  154.8 30.096 154.818 30.24 ;
    END
  END xb[218]
  PIN xb[219]
    DIRECTION OUTPUT ;
    USE SIGNAL ;
    PORT
      LAYER M5 ;
        RECT  155.088 30.048 155.112 30.24 ;
    END
  END xb[219]
  PIN xb[21]
    DIRECTION OUTPUT ;
    USE SIGNAL ;
    PORT
      LAYER M5 ;
        RECT  98.064 30.048 98.088 30.24 ;
    END
  END xb[21]
  PIN xb[220]
    DIRECTION OUTPUT ;
    USE SIGNAL ;
    PORT
      LAYER M3 ;
        RECT  155.376 30.096 155.394 30.24 ;
    END
  END xb[220]
  PIN xb[221]
    DIRECTION OUTPUT ;
    USE SIGNAL ;
    PORT
      LAYER M5 ;
        RECT  155.664 30.048 155.688 30.24 ;
    END
  END xb[221]
  PIN xb[222]
    DIRECTION OUTPUT ;
    USE SIGNAL ;
    PORT
      LAYER M3 ;
        RECT  155.952 30.096 155.97 30.24 ;
    END
  END xb[222]
  PIN xb[223]
    DIRECTION OUTPUT ;
    USE SIGNAL ;
    PORT
      LAYER M5 ;
        RECT  156.24 30.048 156.264 30.24 ;
    END
  END xb[223]
  PIN xb[224]
    DIRECTION OUTPUT ;
    USE SIGNAL ;
    PORT
      LAYER M3 ;
        RECT  156.528 30.096 156.546 30.24 ;
    END
  END xb[224]
  PIN xb[225]
    DIRECTION OUTPUT ;
    USE SIGNAL ;
    PORT
      LAYER M5 ;
        RECT  156.816 30.048 156.84 30.24 ;
    END
  END xb[225]
  PIN xb[226]
    DIRECTION OUTPUT ;
    USE SIGNAL ;
    PORT
      LAYER M3 ;
        RECT  157.104 30.096 157.122 30.24 ;
    END
  END xb[226]
  PIN xb[227]
    DIRECTION OUTPUT ;
    USE SIGNAL ;
    PORT
      LAYER M5 ;
        RECT  157.392 30.048 157.416 30.24 ;
    END
  END xb[227]
  PIN xb[228]
    DIRECTION OUTPUT ;
    USE SIGNAL ;
    PORT
      LAYER M3 ;
        RECT  157.68 30.096 157.698 30.24 ;
    END
  END xb[228]
  PIN xb[229]
    DIRECTION OUTPUT ;
    USE SIGNAL ;
    PORT
      LAYER M5 ;
        RECT  157.968 30.048 157.992 30.24 ;
    END
  END xb[229]
  PIN xb[22]
    DIRECTION OUTPUT ;
    USE SIGNAL ;
    PORT
      LAYER M3 ;
        RECT  98.352 30.096 98.37 30.24 ;
    END
  END xb[22]
  PIN xb[230]
    DIRECTION OUTPUT ;
    USE SIGNAL ;
    PORT
      LAYER M3 ;
        RECT  158.256 30.096 158.274 30.24 ;
    END
  END xb[230]
  PIN xb[231]
    DIRECTION OUTPUT ;
    USE SIGNAL ;
    PORT
      LAYER M5 ;
        RECT  158.544 30.048 158.568 30.24 ;
    END
  END xb[231]
  PIN xb[232]
    DIRECTION OUTPUT ;
    USE SIGNAL ;
    PORT
      LAYER M3 ;
        RECT  158.832 30.096 158.85 30.24 ;
    END
  END xb[232]
  PIN xb[233]
    DIRECTION OUTPUT ;
    USE SIGNAL ;
    PORT
      LAYER M5 ;
        RECT  159.12 30.048 159.144 30.24 ;
    END
  END xb[233]
  PIN xb[234]
    DIRECTION OUTPUT ;
    USE SIGNAL ;
    PORT
      LAYER M3 ;
        RECT  159.408 30.096 159.426 30.24 ;
    END
  END xb[234]
  PIN xb[235]
    DIRECTION OUTPUT ;
    USE SIGNAL ;
    PORT
      LAYER M5 ;
        RECT  159.696 30.048 159.72 30.24 ;
    END
  END xb[235]
  PIN xb[236]
    DIRECTION OUTPUT ;
    USE SIGNAL ;
    PORT
      LAYER M3 ;
        RECT  159.984 30.096 160.002 30.24 ;
    END
  END xb[236]
  PIN xb[237]
    DIRECTION OUTPUT ;
    USE SIGNAL ;
    PORT
      LAYER M5 ;
        RECT  160.272 30.048 160.296 30.24 ;
    END
  END xb[237]
  PIN xb[238]
    DIRECTION OUTPUT ;
    USE SIGNAL ;
    PORT
      LAYER M3 ;
        RECT  160.56 30.096 160.578 30.24 ;
    END
  END xb[238]
  PIN xb[239]
    DIRECTION OUTPUT ;
    USE SIGNAL ;
    PORT
      LAYER M5 ;
        RECT  160.848 30.048 160.872 30.24 ;
    END
  END xb[239]
  PIN xb[23]
    DIRECTION OUTPUT ;
    USE SIGNAL ;
    PORT
      LAYER M5 ;
        RECT  98.64 30.048 98.664 30.24 ;
    END
  END xb[23]
  PIN xb[240]
    DIRECTION OUTPUT ;
    USE SIGNAL ;
    PORT
      LAYER M3 ;
        RECT  161.136 30.096 161.154 30.24 ;
    END
  END xb[240]
  PIN xb[241]
    DIRECTION OUTPUT ;
    USE SIGNAL ;
    PORT
      LAYER M5 ;
        RECT  161.424 30.048 161.448 30.24 ;
    END
  END xb[241]
  PIN xb[242]
    DIRECTION OUTPUT ;
    USE SIGNAL ;
    PORT
      LAYER M3 ;
        RECT  161.712 30.096 161.73 30.24 ;
    END
  END xb[242]
  PIN xb[243]
    DIRECTION OUTPUT ;
    USE SIGNAL ;
    PORT
      LAYER M5 ;
        RECT  162 30.048 162.024 30.24 ;
    END
  END xb[243]
  PIN xb[244]
    DIRECTION OUTPUT ;
    USE SIGNAL ;
    PORT
      LAYER M3 ;
        RECT  162.288 30.096 162.306 30.24 ;
    END
  END xb[244]
  PIN xb[245]
    DIRECTION OUTPUT ;
    USE SIGNAL ;
    PORT
      LAYER M5 ;
        RECT  162.576 30.048 162.6 30.24 ;
    END
  END xb[245]
  PIN xb[246]
    DIRECTION OUTPUT ;
    USE SIGNAL ;
    PORT
      LAYER M3 ;
        RECT  162.864 30.096 162.882 30.24 ;
    END
  END xb[246]
  PIN xb[247]
    DIRECTION OUTPUT ;
    USE SIGNAL ;
    PORT
      LAYER M5 ;
        RECT  163.152 30.048 163.176 30.24 ;
    END
  END xb[247]
  PIN xb[248]
    DIRECTION OUTPUT ;
    USE SIGNAL ;
    PORT
      LAYER M3 ;
        RECT  163.44 30.096 163.458 30.24 ;
    END
  END xb[248]
  PIN xb[249]
    DIRECTION OUTPUT ;
    USE SIGNAL ;
    PORT
      LAYER M5 ;
        RECT  163.728 30.048 163.752 30.24 ;
    END
  END xb[249]
  PIN xb[24]
    DIRECTION OUTPUT ;
    USE SIGNAL ;
    PORT
      LAYER M3 ;
        RECT  98.928 30.096 98.946 30.24 ;
    END
  END xb[24]
  PIN xb[250]
    DIRECTION OUTPUT ;
    USE SIGNAL ;
    PORT
      LAYER M3 ;
        RECT  164.016 30.096 164.034 30.24 ;
    END
  END xb[250]
  PIN xb[251]
    DIRECTION OUTPUT ;
    USE SIGNAL ;
    PORT
      LAYER M5 ;
        RECT  164.304 30.048 164.328 30.24 ;
    END
  END xb[251]
  PIN xb[252]
    DIRECTION OUTPUT ;
    USE SIGNAL ;
    PORT
      LAYER M3 ;
        RECT  164.592 30.096 164.61 30.24 ;
    END
  END xb[252]
  PIN xb[253]
    DIRECTION OUTPUT ;
    USE SIGNAL ;
    PORT
      LAYER M5 ;
        RECT  164.88 30.048 164.904 30.24 ;
    END
  END xb[253]
  PIN xb[254]
    DIRECTION OUTPUT ;
    USE SIGNAL ;
    PORT
      LAYER M3 ;
        RECT  165.168 30.096 165.186 30.24 ;
    END
  END xb[254]
  PIN xb[255]
    DIRECTION OUTPUT ;
    USE SIGNAL ;
    PORT
      LAYER M5 ;
        RECT  165.456 30.048 165.48 30.24 ;
    END
  END xb[255]
  PIN xb[256]
    DIRECTION OUTPUT ;
    USE SIGNAL ;
    PORT
      LAYER M3 ;
        RECT  165.744 30.096 165.762 30.24 ;
    END
  END xb[256]
  PIN xb[257]
    DIRECTION OUTPUT ;
    USE SIGNAL ;
    PORT
      LAYER M5 ;
        RECT  166.032 30.048 166.056 30.24 ;
    END
  END xb[257]
  PIN xb[258]
    DIRECTION OUTPUT ;
    USE SIGNAL ;
    PORT
      LAYER M3 ;
        RECT  166.32 30.096 166.338 30.24 ;
    END
  END xb[258]
  PIN xb[259]
    DIRECTION OUTPUT ;
    USE SIGNAL ;
    PORT
      LAYER M5 ;
        RECT  166.608 30.048 166.632 30.24 ;
    END
  END xb[259]
  PIN xb[25]
    DIRECTION OUTPUT ;
    USE SIGNAL ;
    PORT
      LAYER M5 ;
        RECT  99.216 30.048 99.24 30.24 ;
    END
  END xb[25]
  PIN xb[260]
    DIRECTION OUTPUT ;
    USE SIGNAL ;
    PORT
      LAYER M3 ;
        RECT  166.896 30.096 166.914 30.24 ;
    END
  END xb[260]
  PIN xb[261]
    DIRECTION OUTPUT ;
    USE SIGNAL ;
    PORT
      LAYER M5 ;
        RECT  167.184 30.048 167.208 30.24 ;
    END
  END xb[261]
  PIN xb[262]
    DIRECTION OUTPUT ;
    USE SIGNAL ;
    PORT
      LAYER M3 ;
        RECT  167.472 30.096 167.49 30.24 ;
    END
  END xb[262]
  PIN xb[263]
    DIRECTION OUTPUT ;
    USE SIGNAL ;
    PORT
      LAYER M5 ;
        RECT  167.76 30.048 167.784 30.24 ;
    END
  END xb[263]
  PIN xb[264]
    DIRECTION OUTPUT ;
    USE SIGNAL ;
    PORT
      LAYER M3 ;
        RECT  168.048 30.096 168.066 30.24 ;
    END
  END xb[264]
  PIN xb[265]
    DIRECTION OUTPUT ;
    USE SIGNAL ;
    PORT
      LAYER M5 ;
        RECT  168.336 30.048 168.36 30.24 ;
    END
  END xb[265]
  PIN xb[26]
    DIRECTION OUTPUT ;
    USE SIGNAL ;
    PORT
      LAYER M3 ;
        RECT  99.504 30.096 99.522 30.24 ;
    END
  END xb[26]
  PIN xb[27]
    DIRECTION OUTPUT ;
    USE SIGNAL ;
    PORT
      LAYER M5 ;
        RECT  99.792 30.048 99.816 30.24 ;
    END
  END xb[27]
  PIN xb[28]
    DIRECTION OUTPUT ;
    USE SIGNAL ;
    PORT
      LAYER M3 ;
        RECT  100.08 30.096 100.098 30.24 ;
    END
  END xb[28]
  PIN xb[29]
    DIRECTION OUTPUT ;
    USE SIGNAL ;
    PORT
      LAYER M5 ;
        RECT  100.368 30.048 100.392 30.24 ;
    END
  END xb[29]
  PIN xb[2]
    DIRECTION OUTPUT ;
    USE SIGNAL ;
    PORT
      LAYER M3 ;
        RECT  92.592 30.096 92.61 30.24 ;
    END
  END xb[2]
  PIN xb[30]
    DIRECTION OUTPUT ;
    USE SIGNAL ;
    PORT
      LAYER M3 ;
        RECT  100.656 30.096 100.674 30.24 ;
    END
  END xb[30]
  PIN xb[31]
    DIRECTION OUTPUT ;
    USE SIGNAL ;
    PORT
      LAYER M5 ;
        RECT  100.944 30.048 100.968 30.24 ;
    END
  END xb[31]
  PIN xb[32]
    DIRECTION OUTPUT ;
    USE SIGNAL ;
    PORT
      LAYER M3 ;
        RECT  101.232 30.096 101.25 30.24 ;
    END
  END xb[32]
  PIN xb[33]
    DIRECTION OUTPUT ;
    USE SIGNAL ;
    PORT
      LAYER M5 ;
        RECT  101.52 30.048 101.544 30.24 ;
    END
  END xb[33]
  PIN xb[34]
    DIRECTION OUTPUT ;
    USE SIGNAL ;
    PORT
      LAYER M3 ;
        RECT  101.808 30.096 101.826 30.24 ;
    END
  END xb[34]
  PIN xb[35]
    DIRECTION OUTPUT ;
    USE SIGNAL ;
    PORT
      LAYER M5 ;
        RECT  102.096 30.048 102.12 30.24 ;
    END
  END xb[35]
  PIN xb[36]
    DIRECTION OUTPUT ;
    USE SIGNAL ;
    PORT
      LAYER M3 ;
        RECT  102.384 30.096 102.402 30.24 ;
    END
  END xb[36]
  PIN xb[37]
    DIRECTION OUTPUT ;
    USE SIGNAL ;
    PORT
      LAYER M5 ;
        RECT  102.672 30.048 102.696 30.24 ;
    END
  END xb[37]
  PIN xb[38]
    DIRECTION OUTPUT ;
    USE SIGNAL ;
    PORT
      LAYER M3 ;
        RECT  102.96 30.096 102.978 30.24 ;
    END
  END xb[38]
  PIN xb[39]
    DIRECTION OUTPUT ;
    USE SIGNAL ;
    PORT
      LAYER M5 ;
        RECT  103.248 30.048 103.272 30.24 ;
    END
  END xb[39]
  PIN xb[3]
    DIRECTION OUTPUT ;
    USE SIGNAL ;
    PORT
      LAYER M5 ;
        RECT  92.88 30.048 92.904 30.24 ;
    END
  END xb[3]
  PIN xb[40]
    DIRECTION OUTPUT ;
    USE SIGNAL ;
    PORT
      LAYER M3 ;
        RECT  103.536 30.096 103.554 30.24 ;
    END
  END xb[40]
  PIN xb[41]
    DIRECTION OUTPUT ;
    USE SIGNAL ;
    PORT
      LAYER M5 ;
        RECT  103.824 30.048 103.848 30.24 ;
    END
  END xb[41]
  PIN xb[42]
    DIRECTION OUTPUT ;
    USE SIGNAL ;
    PORT
      LAYER M3 ;
        RECT  104.112 30.096 104.13 30.24 ;
    END
  END xb[42]
  PIN xb[43]
    DIRECTION OUTPUT ;
    USE SIGNAL ;
    PORT
      LAYER M5 ;
        RECT  104.4 30.048 104.424 30.24 ;
    END
  END xb[43]
  PIN xb[44]
    DIRECTION OUTPUT ;
    USE SIGNAL ;
    PORT
      LAYER M3 ;
        RECT  104.688 30.096 104.706 30.24 ;
    END
  END xb[44]
  PIN xb[45]
    DIRECTION OUTPUT ;
    USE SIGNAL ;
    PORT
      LAYER M5 ;
        RECT  104.976 30.048 105 30.24 ;
    END
  END xb[45]
  PIN xb[46]
    DIRECTION OUTPUT ;
    USE SIGNAL ;
    PORT
      LAYER M3 ;
        RECT  105.264 30.096 105.282 30.24 ;
    END
  END xb[46]
  PIN xb[47]
    DIRECTION OUTPUT ;
    USE SIGNAL ;
    PORT
      LAYER M5 ;
        RECT  105.552 30.048 105.576 30.24 ;
    END
  END xb[47]
  PIN xb[48]
    DIRECTION OUTPUT ;
    USE SIGNAL ;
    PORT
      LAYER M3 ;
        RECT  105.84 30.096 105.858 30.24 ;
    END
  END xb[48]
  PIN xb[49]
    DIRECTION OUTPUT ;
    USE SIGNAL ;
    PORT
      LAYER M5 ;
        RECT  106.128 30.048 106.152 30.24 ;
    END
  END xb[49]
  PIN xb[4]
    DIRECTION OUTPUT ;
    USE SIGNAL ;
    PORT
      LAYER M3 ;
        RECT  93.168 30.096 93.186 30.24 ;
    END
  END xb[4]
  PIN xb[50]
    DIRECTION OUTPUT ;
    USE SIGNAL ;
    PORT
      LAYER M3 ;
        RECT  106.416 30.096 106.434 30.24 ;
    END
  END xb[50]
  PIN xb[51]
    DIRECTION OUTPUT ;
    USE SIGNAL ;
    PORT
      LAYER M5 ;
        RECT  106.704 30.048 106.728 30.24 ;
    END
  END xb[51]
  PIN xb[52]
    DIRECTION OUTPUT ;
    USE SIGNAL ;
    PORT
      LAYER M3 ;
        RECT  106.992 30.096 107.01 30.24 ;
    END
  END xb[52]
  PIN xb[53]
    DIRECTION OUTPUT ;
    USE SIGNAL ;
    PORT
      LAYER M5 ;
        RECT  107.28 30.048 107.304 30.24 ;
    END
  END xb[53]
  PIN xb[54]
    DIRECTION OUTPUT ;
    USE SIGNAL ;
    PORT
      LAYER M3 ;
        RECT  107.568 30.096 107.586 30.24 ;
    END
  END xb[54]
  PIN xb[55]
    DIRECTION OUTPUT ;
    USE SIGNAL ;
    PORT
      LAYER M5 ;
        RECT  107.856 30.048 107.88 30.24 ;
    END
  END xb[55]
  PIN xb[56]
    DIRECTION OUTPUT ;
    USE SIGNAL ;
    PORT
      LAYER M3 ;
        RECT  108.144 30.096 108.162 30.24 ;
    END
  END xb[56]
  PIN xb[57]
    DIRECTION OUTPUT ;
    USE SIGNAL ;
    PORT
      LAYER M5 ;
        RECT  108.432 30.048 108.456 30.24 ;
    END
  END xb[57]
  PIN xb[58]
    DIRECTION OUTPUT ;
    USE SIGNAL ;
    PORT
      LAYER M3 ;
        RECT  108.72 30.096 108.738 30.24 ;
    END
  END xb[58]
  PIN xb[59]
    DIRECTION OUTPUT ;
    USE SIGNAL ;
    PORT
      LAYER M5 ;
        RECT  109.008 30.048 109.032 30.24 ;
    END
  END xb[59]
  PIN xb[5]
    DIRECTION OUTPUT ;
    USE SIGNAL ;
    PORT
      LAYER M5 ;
        RECT  93.456 30.048 93.48 30.24 ;
    END
  END xb[5]
  PIN xb[60]
    DIRECTION OUTPUT ;
    USE SIGNAL ;
    PORT
      LAYER M3 ;
        RECT  109.296 30.096 109.314 30.24 ;
    END
  END xb[60]
  PIN xb[61]
    DIRECTION OUTPUT ;
    USE SIGNAL ;
    PORT
      LAYER M5 ;
        RECT  109.584 30.048 109.608 30.24 ;
    END
  END xb[61]
  PIN xb[62]
    DIRECTION OUTPUT ;
    USE SIGNAL ;
    PORT
      LAYER M3 ;
        RECT  109.872 30.096 109.89 30.24 ;
    END
  END xb[62]
  PIN xb[63]
    DIRECTION OUTPUT ;
    USE SIGNAL ;
    PORT
      LAYER M5 ;
        RECT  110.16 30.048 110.184 30.24 ;
    END
  END xb[63]
  PIN xb[64]
    DIRECTION OUTPUT ;
    USE SIGNAL ;
    PORT
      LAYER M3 ;
        RECT  110.448 30.096 110.466 30.24 ;
    END
  END xb[64]
  PIN xb[65]
    DIRECTION OUTPUT ;
    USE SIGNAL ;
    PORT
      LAYER M5 ;
        RECT  110.736 30.048 110.76 30.24 ;
    END
  END xb[65]
  PIN xb[66]
    DIRECTION OUTPUT ;
    USE SIGNAL ;
    PORT
      LAYER M3 ;
        RECT  111.024 30.096 111.042 30.24 ;
    END
  END xb[66]
  PIN xb[67]
    DIRECTION OUTPUT ;
    USE SIGNAL ;
    PORT
      LAYER M5 ;
        RECT  111.312 30.048 111.336 30.24 ;
    END
  END xb[67]
  PIN xb[68]
    DIRECTION OUTPUT ;
    USE SIGNAL ;
    PORT
      LAYER M3 ;
        RECT  111.6 30.096 111.618 30.24 ;
    END
  END xb[68]
  PIN xb[69]
    DIRECTION OUTPUT ;
    USE SIGNAL ;
    PORT
      LAYER M5 ;
        RECT  111.888 30.048 111.912 30.24 ;
    END
  END xb[69]
  PIN xb[6]
    DIRECTION OUTPUT ;
    USE SIGNAL ;
    PORT
      LAYER M3 ;
        RECT  93.744 30.096 93.762 30.24 ;
    END
  END xb[6]
  PIN xb[70]
    DIRECTION OUTPUT ;
    USE SIGNAL ;
    PORT
      LAYER M3 ;
        RECT  112.176 30.096 112.194 30.24 ;
    END
  END xb[70]
  PIN xb[71]
    DIRECTION OUTPUT ;
    USE SIGNAL ;
    PORT
      LAYER M5 ;
        RECT  112.464 30.048 112.488 30.24 ;
    END
  END xb[71]
  PIN xb[72]
    DIRECTION OUTPUT ;
    USE SIGNAL ;
    PORT
      LAYER M3 ;
        RECT  112.752 30.096 112.77 30.24 ;
    END
  END xb[72]
  PIN xb[73]
    DIRECTION OUTPUT ;
    USE SIGNAL ;
    PORT
      LAYER M5 ;
        RECT  113.04 30.048 113.064 30.24 ;
    END
  END xb[73]
  PIN xb[74]
    DIRECTION OUTPUT ;
    USE SIGNAL ;
    PORT
      LAYER M3 ;
        RECT  113.328 30.096 113.346 30.24 ;
    END
  END xb[74]
  PIN xb[75]
    DIRECTION OUTPUT ;
    USE SIGNAL ;
    PORT
      LAYER M5 ;
        RECT  113.616 30.048 113.64 30.24 ;
    END
  END xb[75]
  PIN xb[76]
    DIRECTION OUTPUT ;
    USE SIGNAL ;
    PORT
      LAYER M3 ;
        RECT  113.904 30.096 113.922 30.24 ;
    END
  END xb[76]
  PIN xb[77]
    DIRECTION OUTPUT ;
    USE SIGNAL ;
    PORT
      LAYER M5 ;
        RECT  114.192 30.048 114.216 30.24 ;
    END
  END xb[77]
  PIN xb[78]
    DIRECTION OUTPUT ;
    USE SIGNAL ;
    PORT
      LAYER M3 ;
        RECT  114.48 30.096 114.498 30.24 ;
    END
  END xb[78]
  PIN xb[79]
    DIRECTION OUTPUT ;
    USE SIGNAL ;
    PORT
      LAYER M5 ;
        RECT  114.768 30.048 114.792 30.24 ;
    END
  END xb[79]
  PIN xb[7]
    DIRECTION OUTPUT ;
    USE SIGNAL ;
    PORT
      LAYER M5 ;
        RECT  94.032 30.048 94.056 30.24 ;
    END
  END xb[7]
  PIN xb[80]
    DIRECTION OUTPUT ;
    USE SIGNAL ;
    PORT
      LAYER M3 ;
        RECT  115.056 30.096 115.074 30.24 ;
    END
  END xb[80]
  PIN xb[81]
    DIRECTION OUTPUT ;
    USE SIGNAL ;
    PORT
      LAYER M5 ;
        RECT  115.344 30.048 115.368 30.24 ;
    END
  END xb[81]
  PIN xb[82]
    DIRECTION OUTPUT ;
    USE SIGNAL ;
    PORT
      LAYER M3 ;
        RECT  115.632 30.096 115.65 30.24 ;
    END
  END xb[82]
  PIN xb[83]
    DIRECTION OUTPUT ;
    USE SIGNAL ;
    PORT
      LAYER M5 ;
        RECT  115.92 30.048 115.944 30.24 ;
    END
  END xb[83]
  PIN xb[84]
    DIRECTION OUTPUT ;
    USE SIGNAL ;
    PORT
      LAYER M3 ;
        RECT  116.208 30.096 116.226 30.24 ;
    END
  END xb[84]
  PIN xb[85]
    DIRECTION OUTPUT ;
    USE SIGNAL ;
    PORT
      LAYER M5 ;
        RECT  116.496 30.048 116.52 30.24 ;
    END
  END xb[85]
  PIN xb[86]
    DIRECTION OUTPUT ;
    USE SIGNAL ;
    PORT
      LAYER M3 ;
        RECT  116.784 30.096 116.802 30.24 ;
    END
  END xb[86]
  PIN xb[87]
    DIRECTION OUTPUT ;
    USE SIGNAL ;
    PORT
      LAYER M5 ;
        RECT  117.072 30.048 117.096 30.24 ;
    END
  END xb[87]
  PIN xb[88]
    DIRECTION OUTPUT ;
    USE SIGNAL ;
    PORT
      LAYER M3 ;
        RECT  117.36 30.096 117.378 30.24 ;
    END
  END xb[88]
  PIN xb[89]
    DIRECTION OUTPUT ;
    USE SIGNAL ;
    PORT
      LAYER M5 ;
        RECT  117.648 30.048 117.672 30.24 ;
    END
  END xb[89]
  PIN xb[8]
    DIRECTION OUTPUT ;
    USE SIGNAL ;
    PORT
      LAYER M3 ;
        RECT  94.32 30.096 94.338 30.24 ;
    END
  END xb[8]
  PIN xb[90]
    DIRECTION OUTPUT ;
    USE SIGNAL ;
    PORT
      LAYER M3 ;
        RECT  117.936 30.096 117.954 30.24 ;
    END
  END xb[90]
  PIN xb[91]
    DIRECTION OUTPUT ;
    USE SIGNAL ;
    PORT
      LAYER M5 ;
        RECT  118.224 30.048 118.248 30.24 ;
    END
  END xb[91]
  PIN xb[92]
    DIRECTION OUTPUT ;
    USE SIGNAL ;
    PORT
      LAYER M3 ;
        RECT  118.512 30.096 118.53 30.24 ;
    END
  END xb[92]
  PIN xb[93]
    DIRECTION OUTPUT ;
    USE SIGNAL ;
    PORT
      LAYER M5 ;
        RECT  118.8 30.048 118.824 30.24 ;
    END
  END xb[93]
  PIN xb[94]
    DIRECTION OUTPUT ;
    USE SIGNAL ;
    PORT
      LAYER M3 ;
        RECT  119.088 30.096 119.106 30.24 ;
    END
  END xb[94]
  PIN xb[95]
    DIRECTION OUTPUT ;
    USE SIGNAL ;
    PORT
      LAYER M5 ;
        RECT  119.376 30.048 119.4 30.24 ;
    END
  END xb[95]
  PIN xb[96]
    DIRECTION OUTPUT ;
    USE SIGNAL ;
    PORT
      LAYER M3 ;
        RECT  119.664 30.096 119.682 30.24 ;
    END
  END xb[96]
  PIN xb[97]
    DIRECTION OUTPUT ;
    USE SIGNAL ;
    PORT
      LAYER M5 ;
        RECT  119.952 30.048 119.976 30.24 ;
    END
  END xb[97]
  PIN xb[98]
    DIRECTION OUTPUT ;
    USE SIGNAL ;
    PORT
      LAYER M3 ;
        RECT  120.24 30.096 120.258 30.24 ;
    END
  END xb[98]
  PIN xb[99]
    DIRECTION OUTPUT ;
    USE SIGNAL ;
    PORT
      LAYER M5 ;
        RECT  120.528 30.048 120.552 30.24 ;
    END
  END xb[99]
  PIN xb[9]
    DIRECTION OUTPUT ;
    USE SIGNAL ;
    PORT
      LAYER M5 ;
        RECT  94.608 30.048 94.632 30.24 ;
    END
  END xb[9]
  PIN xbi[0]
    DIRECTION INPUT ;
    USE SIGNAL ;
    PORT
      LAYER M3 ;
        RECT  91.476 0 91.494 0.144 ;
    END
  END xbi[0]
  PIN xbi[100]
    DIRECTION INPUT ;
    USE SIGNAL ;
    PORT
      LAYER M3 ;
        RECT  120.456 0 120.474 0.144 ;
    END
  END xbi[100]
  PIN xbi[101]
    DIRECTION INPUT ;
    USE SIGNAL ;
    PORT
      LAYER M5 ;
        RECT  120.768 0 120.792 0.192 ;
    END
  END xbi[101]
  PIN xbi[102]
    DIRECTION INPUT ;
    USE SIGNAL ;
    PORT
      LAYER M3 ;
        RECT  121.068 0 121.086 0.144 ;
    END
  END xbi[102]
  PIN xbi[103]
    DIRECTION INPUT ;
    USE SIGNAL ;
    PORT
      LAYER M5 ;
        RECT  121.344 0 121.368 0.192 ;
    END
  END xbi[103]
  PIN xbi[104]
    DIRECTION INPUT ;
    USE SIGNAL ;
    PORT
      LAYER M3 ;
        RECT  121.644 0 121.662 0.144 ;
    END
  END xbi[104]
  PIN xbi[105]
    DIRECTION INPUT ;
    USE SIGNAL ;
    PORT
      LAYER M5 ;
        RECT  121.92 0 121.944 0.192 ;
    END
  END xbi[105]
  PIN xbi[106]
    DIRECTION INPUT ;
    USE SIGNAL ;
    PORT
      LAYER M3 ;
        RECT  122.22 0 122.238 0.144 ;
    END
  END xbi[106]
  PIN xbi[107]
    DIRECTION INPUT ;
    USE SIGNAL ;
    PORT
      LAYER M5 ;
        RECT  122.496 0 122.52 0.192 ;
    END
  END xbi[107]
  PIN xbi[108]
    DIRECTION INPUT ;
    USE SIGNAL ;
    PORT
      LAYER M3 ;
        RECT  122.796 0 122.814 0.144 ;
    END
  END xbi[108]
  PIN xbi[109]
    DIRECTION INPUT ;
    USE SIGNAL ;
    PORT
      LAYER M5 ;
        RECT  123.072 0 123.096 0.192 ;
    END
  END xbi[109]
  PIN xbi[10]
    DIRECTION INPUT ;
    USE SIGNAL ;
    PORT
      LAYER M3 ;
        RECT  94.356 0 94.374 0.144 ;
    END
  END xbi[10]
  PIN xbi[110]
    DIRECTION INPUT ;
    USE SIGNAL ;
    PORT
      LAYER M3 ;
        RECT  123.372 0 123.39 0.144 ;
    END
  END xbi[110]
  PIN xbi[111]
    DIRECTION INPUT ;
    USE SIGNAL ;
    PORT
      LAYER M5 ;
        RECT  123.648 0 123.672 0.192 ;
    END
  END xbi[111]
  PIN xbi[112]
    DIRECTION INPUT ;
    USE SIGNAL ;
    PORT
      LAYER M3 ;
        RECT  123.948 0 123.966 0.144 ;
    END
  END xbi[112]
  PIN xbi[113]
    DIRECTION INPUT ;
    USE SIGNAL ;
    PORT
      LAYER M5 ;
        RECT  124.224 0 124.248 0.192 ;
    END
  END xbi[113]
  PIN xbi[114]
    DIRECTION INPUT ;
    USE SIGNAL ;
    PORT
      LAYER M3 ;
        RECT  124.524 0 124.542 0.144 ;
    END
  END xbi[114]
  PIN xbi[115]
    DIRECTION INPUT ;
    USE SIGNAL ;
    PORT
      LAYER M5 ;
        RECT  124.8 0 124.824 0.192 ;
    END
  END xbi[115]
  PIN xbi[116]
    DIRECTION INPUT ;
    USE SIGNAL ;
    PORT
      LAYER M3 ;
        RECT  125.1 0 125.118 0.144 ;
    END
  END xbi[116]
  PIN xbi[117]
    DIRECTION INPUT ;
    USE SIGNAL ;
    PORT
      LAYER M5 ;
        RECT  125.376 0 125.4 0.192 ;
    END
  END xbi[117]
  PIN xbi[118]
    DIRECTION INPUT ;
    USE SIGNAL ;
    PORT
      LAYER M3 ;
        RECT  125.676 0 125.694 0.144 ;
    END
  END xbi[118]
  PIN xbi[119]
    DIRECTION INPUT ;
    USE SIGNAL ;
    PORT
      LAYER M5 ;
        RECT  126 0 126.024 0.192 ;
    END
  END xbi[119]
  PIN xbi[11]
    DIRECTION INPUT ;
    USE SIGNAL ;
    PORT
      LAYER M5 ;
        RECT  94.656 0 94.68 0.192 ;
    END
  END xbi[11]
  PIN xbi[120]
    DIRECTION INPUT ;
    USE SIGNAL ;
    PORT
      LAYER M3 ;
        RECT  126.288 0 126.306 0.144 ;
    END
  END xbi[120]
  PIN xbi[121]
    DIRECTION INPUT ;
    USE SIGNAL ;
    PORT
      LAYER M5 ;
        RECT  126.576 0 126.6 0.192 ;
    END
  END xbi[121]
  PIN xbi[122]
    DIRECTION INPUT ;
    USE SIGNAL ;
    PORT
      LAYER M3 ;
        RECT  126.864 0 126.882 0.144 ;
    END
  END xbi[122]
  PIN xbi[123]
    DIRECTION INPUT ;
    USE SIGNAL ;
    PORT
      LAYER M5 ;
        RECT  127.152 0 127.176 0.192 ;
    END
  END xbi[123]
  PIN xbi[124]
    DIRECTION INPUT ;
    USE SIGNAL ;
    PORT
      LAYER M3 ;
        RECT  127.44 0 127.458 0.144 ;
    END
  END xbi[124]
  PIN xbi[125]
    DIRECTION INPUT ;
    USE SIGNAL ;
    PORT
      LAYER M5 ;
        RECT  127.728 0 127.752 0.192 ;
    END
  END xbi[125]
  PIN xbi[126]
    DIRECTION INPUT ;
    USE SIGNAL ;
    PORT
      LAYER M3 ;
        RECT  128.016 0 128.034 0.144 ;
    END
  END xbi[126]
  PIN xbi[127]
    DIRECTION INPUT ;
    USE SIGNAL ;
    PORT
      LAYER M5 ;
        RECT  128.304 0 128.328 0.192 ;
    END
  END xbi[127]
  PIN xbi[128]
    DIRECTION INPUT ;
    USE SIGNAL ;
    PORT
      LAYER M3 ;
        RECT  128.592 0 128.61 0.144 ;
    END
  END xbi[128]
  PIN xbi[129]
    DIRECTION INPUT ;
    USE SIGNAL ;
    PORT
      LAYER M5 ;
        RECT  128.88 0 128.904 0.192 ;
    END
  END xbi[129]
  PIN xbi[12]
    DIRECTION INPUT ;
    USE SIGNAL ;
    PORT
      LAYER M3 ;
        RECT  94.932 0 94.95 0.144 ;
    END
  END xbi[12]
  PIN xbi[130]
    DIRECTION INPUT ;
    USE SIGNAL ;
    PORT
      LAYER M3 ;
        RECT  129.168 0 129.186 0.144 ;
    END
  END xbi[130]
  PIN xbi[131]
    DIRECTION INPUT ;
    USE SIGNAL ;
    PORT
      LAYER M5 ;
        RECT  129.456 0 129.48 0.192 ;
    END
  END xbi[131]
  PIN xbi[132]
    DIRECTION INPUT ;
    USE SIGNAL ;
    PORT
      LAYER M3 ;
        RECT  129.744 0 129.762 0.144 ;
    END
  END xbi[132]
  PIN xbi[133]
    DIRECTION INPUT ;
    USE SIGNAL ;
    PORT
      LAYER M5 ;
        RECT  130.032 0 130.056 0.192 ;
    END
  END xbi[133]
  PIN xbi[134]
    DIRECTION INPUT ;
    USE SIGNAL ;
    PORT
      LAYER M3 ;
        RECT  130.32 0 130.338 0.144 ;
    END
  END xbi[134]
  PIN xbi[135]
    DIRECTION INPUT ;
    USE SIGNAL ;
    PORT
      LAYER M5 ;
        RECT  130.608 0 130.632 0.192 ;
    END
  END xbi[135]
  PIN xbi[136]
    DIRECTION INPUT ;
    USE SIGNAL ;
    PORT
      LAYER M3 ;
        RECT  130.896 0 130.914 0.144 ;
    END
  END xbi[136]
  PIN xbi[137]
    DIRECTION INPUT ;
    USE SIGNAL ;
    PORT
      LAYER M5 ;
        RECT  131.184 0 131.208 0.192 ;
    END
  END xbi[137]
  PIN xbi[138]
    DIRECTION INPUT ;
    USE SIGNAL ;
    PORT
      LAYER M3 ;
        RECT  131.508 0 131.526 0.144 ;
    END
  END xbi[138]
  PIN xbi[139]
    DIRECTION INPUT ;
    USE SIGNAL ;
    PORT
      LAYER M5 ;
        RECT  131.76 0 131.784 0.192 ;
    END
  END xbi[139]
  PIN xbi[13]
    DIRECTION INPUT ;
    USE SIGNAL ;
    PORT
      LAYER M5 ;
        RECT  95.232 0 95.256 0.192 ;
    END
  END xbi[13]
  PIN xbi[140]
    DIRECTION INPUT ;
    USE SIGNAL ;
    PORT
      LAYER M3 ;
        RECT  132.084 0 132.102 0.144 ;
    END
  END xbi[140]
  PIN xbi[141]
    DIRECTION INPUT ;
    USE SIGNAL ;
    PORT
      LAYER M5 ;
        RECT  132.336 0 132.36 0.192 ;
    END
  END xbi[141]
  PIN xbi[142]
    DIRECTION INPUT ;
    USE SIGNAL ;
    PORT
      LAYER M3 ;
        RECT  132.66 0 132.678 0.144 ;
    END
  END xbi[142]
  PIN xbi[143]
    DIRECTION INPUT ;
    USE SIGNAL ;
    PORT
      LAYER M5 ;
        RECT  132.96 0 132.984 0.192 ;
    END
  END xbi[143]
  PIN xbi[144]
    DIRECTION INPUT ;
    USE SIGNAL ;
    PORT
      LAYER M3 ;
        RECT  133.236 0 133.254 0.144 ;
    END
  END xbi[144]
  PIN xbi[145]
    DIRECTION INPUT ;
    USE SIGNAL ;
    PORT
      LAYER M5 ;
        RECT  133.536 0 133.56 0.192 ;
    END
  END xbi[145]
  PIN xbi[146]
    DIRECTION INPUT ;
    USE SIGNAL ;
    PORT
      LAYER M3 ;
        RECT  133.812 0 133.83 0.144 ;
    END
  END xbi[146]
  PIN xbi[147]
    DIRECTION INPUT ;
    USE SIGNAL ;
    PORT
      LAYER M5 ;
        RECT  134.112 0 134.136 0.192 ;
    END
  END xbi[147]
  PIN xbi[148]
    DIRECTION INPUT ;
    USE SIGNAL ;
    PORT
      LAYER M3 ;
        RECT  134.388 0 134.406 0.144 ;
    END
  END xbi[148]
  PIN xbi[149]
    DIRECTION INPUT ;
    USE SIGNAL ;
    PORT
      LAYER M5 ;
        RECT  134.688 0 134.712 0.192 ;
    END
  END xbi[149]
  PIN xbi[14]
    DIRECTION INPUT ;
    USE SIGNAL ;
    PORT
      LAYER M3 ;
        RECT  95.544 0 95.562 0.144 ;
    END
  END xbi[14]
  PIN xbi[150]
    DIRECTION INPUT ;
    USE SIGNAL ;
    PORT
      LAYER M3 ;
        RECT  134.964 0 134.982 0.144 ;
    END
  END xbi[150]
  PIN xbi[151]
    DIRECTION INPUT ;
    USE SIGNAL ;
    PORT
      LAYER M5 ;
        RECT  135.264 0 135.288 0.192 ;
    END
  END xbi[151]
  PIN xbi[152]
    DIRECTION INPUT ;
    USE SIGNAL ;
    PORT
      LAYER M3 ;
        RECT  135.54 0 135.558 0.144 ;
    END
  END xbi[152]
  PIN xbi[153]
    DIRECTION INPUT ;
    USE SIGNAL ;
    PORT
      LAYER M5 ;
        RECT  135.84 0 135.864 0.192 ;
    END
  END xbi[153]
  PIN xbi[154]
    DIRECTION INPUT ;
    USE SIGNAL ;
    PORT
      LAYER M3 ;
        RECT  136.116 0 136.134 0.144 ;
    END
  END xbi[154]
  PIN xbi[155]
    DIRECTION INPUT ;
    USE SIGNAL ;
    PORT
      LAYER M5 ;
        RECT  136.416 0 136.44 0.192 ;
    END
  END xbi[155]
  PIN xbi[156]
    DIRECTION INPUT ;
    USE SIGNAL ;
    PORT
      LAYER M3 ;
        RECT  136.728 0 136.746 0.144 ;
    END
  END xbi[156]
  PIN xbi[157]
    DIRECTION INPUT ;
    USE SIGNAL ;
    PORT
      LAYER M5 ;
        RECT  136.992 0 137.016 0.192 ;
    END
  END xbi[157]
  PIN xbi[158]
    DIRECTION INPUT ;
    USE SIGNAL ;
    PORT
      LAYER M3 ;
        RECT  137.304 0 137.322 0.144 ;
    END
  END xbi[158]
  PIN xbi[159]
    DIRECTION INPUT ;
    USE SIGNAL ;
    PORT
      LAYER M5 ;
        RECT  137.568 0 137.592 0.192 ;
    END
  END xbi[159]
  PIN xbi[15]
    DIRECTION INPUT ;
    USE SIGNAL ;
    PORT
      LAYER M5 ;
        RECT  95.808 0 95.832 0.192 ;
    END
  END xbi[15]
  PIN xbi[160]
    DIRECTION INPUT ;
    USE SIGNAL ;
    PORT
      LAYER M3 ;
        RECT  137.88 0 137.898 0.144 ;
    END
  END xbi[160]
  PIN xbi[161]
    DIRECTION INPUT ;
    USE SIGNAL ;
    PORT
      LAYER M5 ;
        RECT  138.144 0 138.168 0.192 ;
    END
  END xbi[161]
  PIN xbi[162]
    DIRECTION INPUT ;
    USE SIGNAL ;
    PORT
      LAYER M3 ;
        RECT  138.456 0 138.474 0.144 ;
    END
  END xbi[162]
  PIN xbi[163]
    DIRECTION INPUT ;
    USE SIGNAL ;
    PORT
      LAYER M5 ;
        RECT  138.72 0 138.744 0.192 ;
    END
  END xbi[163]
  PIN xbi[164]
    DIRECTION INPUT ;
    USE SIGNAL ;
    PORT
      LAYER M3 ;
        RECT  139.032 0 139.05 0.144 ;
    END
  END xbi[164]
  PIN xbi[165]
    DIRECTION INPUT ;
    USE SIGNAL ;
    PORT
      LAYER M5 ;
        RECT  139.296 0 139.32 0.192 ;
    END
  END xbi[165]
  PIN xbi[166]
    DIRECTION INPUT ;
    USE SIGNAL ;
    PORT
      LAYER M3 ;
        RECT  139.608 0 139.626 0.144 ;
    END
  END xbi[166]
  PIN xbi[167]
    DIRECTION INPUT ;
    USE SIGNAL ;
    PORT
      LAYER M5 ;
        RECT  139.92 0 139.944 0.192 ;
    END
  END xbi[167]
  PIN xbi[168]
    DIRECTION INPUT ;
    USE SIGNAL ;
    PORT
      LAYER M3 ;
        RECT  140.184 0 140.202 0.144 ;
    END
  END xbi[168]
  PIN xbi[169]
    DIRECTION INPUT ;
    USE SIGNAL ;
    PORT
      LAYER M5 ;
        RECT  140.496 0 140.52 0.192 ;
    END
  END xbi[169]
  PIN xbi[16]
    DIRECTION INPUT ;
    USE SIGNAL ;
    PORT
      LAYER M3 ;
        RECT  96.12 0 96.138 0.144 ;
    END
  END xbi[16]
  PIN xbi[170]
    DIRECTION INPUT ;
    USE SIGNAL ;
    PORT
      LAYER M3 ;
        RECT  140.76 0 140.778 0.144 ;
    END
  END xbi[170]
  PIN xbi[171]
    DIRECTION INPUT ;
    USE SIGNAL ;
    PORT
      LAYER M5 ;
        RECT  141.072 0 141.096 0.192 ;
    END
  END xbi[171]
  PIN xbi[172]
    DIRECTION INPUT ;
    USE SIGNAL ;
    PORT
      LAYER M3 ;
        RECT  141.336 0 141.354 0.144 ;
    END
  END xbi[172]
  PIN xbi[173]
    DIRECTION INPUT ;
    USE SIGNAL ;
    PORT
      LAYER M5 ;
        RECT  141.648 0 141.672 0.192 ;
    END
  END xbi[173]
  PIN xbi[174]
    DIRECTION INPUT ;
    USE SIGNAL ;
    PORT
      LAYER M3 ;
        RECT  141.948 0 141.966 0.144 ;
    END
  END xbi[174]
  PIN xbi[175]
    DIRECTION INPUT ;
    USE SIGNAL ;
    PORT
      LAYER M5 ;
        RECT  142.224 0 142.248 0.192 ;
    END
  END xbi[175]
  PIN xbi[176]
    DIRECTION INPUT ;
    USE SIGNAL ;
    PORT
      LAYER M3 ;
        RECT  142.524 0 142.542 0.144 ;
    END
  END xbi[176]
  PIN xbi[177]
    DIRECTION INPUT ;
    USE SIGNAL ;
    PORT
      LAYER M5 ;
        RECT  142.8 0 142.824 0.192 ;
    END
  END xbi[177]
  PIN xbi[178]
    DIRECTION INPUT ;
    USE SIGNAL ;
    PORT
      LAYER M3 ;
        RECT  143.1 0 143.118 0.144 ;
    END
  END xbi[178]
  PIN xbi[179]
    DIRECTION INPUT ;
    USE SIGNAL ;
    PORT
      LAYER M5 ;
        RECT  143.376 0 143.4 0.192 ;
    END
  END xbi[179]
  PIN xbi[17]
    DIRECTION INPUT ;
    USE SIGNAL ;
    PORT
      LAYER M5 ;
        RECT  96.384 0 96.408 0.192 ;
    END
  END xbi[17]
  PIN xbi[180]
    DIRECTION INPUT ;
    USE SIGNAL ;
    PORT
      LAYER M3 ;
        RECT  143.676 0 143.694 0.144 ;
    END
  END xbi[180]
  PIN xbi[181]
    DIRECTION INPUT ;
    USE SIGNAL ;
    PORT
      LAYER M5 ;
        RECT  143.952 0 143.976 0.192 ;
    END
  END xbi[181]
  PIN xbi[182]
    DIRECTION INPUT ;
    USE SIGNAL ;
    PORT
      LAYER M3 ;
        RECT  144.252 0 144.27 0.144 ;
    END
  END xbi[182]
  PIN xbi[183]
    DIRECTION INPUT ;
    USE SIGNAL ;
    PORT
      LAYER M5 ;
        RECT  144.528 0 144.552 0.192 ;
    END
  END xbi[183]
  PIN xbi[184]
    DIRECTION INPUT ;
    USE SIGNAL ;
    PORT
      LAYER M3 ;
        RECT  144.828 0 144.846 0.144 ;
    END
  END xbi[184]
  PIN xbi[185]
    DIRECTION INPUT ;
    USE SIGNAL ;
    PORT
      LAYER M5 ;
        RECT  145.104 0 145.128 0.192 ;
    END
  END xbi[185]
  PIN xbi[186]
    DIRECTION INPUT ;
    USE SIGNAL ;
    PORT
      LAYER M3 ;
        RECT  145.404 0 145.422 0.144 ;
    END
  END xbi[186]
  PIN xbi[187]
    DIRECTION INPUT ;
    USE SIGNAL ;
    PORT
      LAYER M5 ;
        RECT  145.68 0 145.704 0.192 ;
    END
  END xbi[187]
  PIN xbi[188]
    DIRECTION INPUT ;
    USE SIGNAL ;
    PORT
      LAYER M3 ;
        RECT  145.98 0 145.998 0.144 ;
    END
  END xbi[188]
  PIN xbi[189]
    DIRECTION INPUT ;
    USE SIGNAL ;
    PORT
      LAYER M5 ;
        RECT  146.304 0 146.328 0.192 ;
    END
  END xbi[189]
  PIN xbi[18]
    DIRECTION INPUT ;
    USE SIGNAL ;
    PORT
      LAYER M3 ;
        RECT  96.696 0 96.714 0.144 ;
    END
  END xbi[18]
  PIN xbi[190]
    DIRECTION INPUT ;
    USE SIGNAL ;
    PORT
      LAYER M3 ;
        RECT  146.556 0 146.574 0.144 ;
    END
  END xbi[190]
  PIN xbi[191]
    DIRECTION INPUT ;
    USE SIGNAL ;
    PORT
      LAYER M5 ;
        RECT  146.88 0 146.904 0.192 ;
    END
  END xbi[191]
  PIN xbi[192]
    DIRECTION INPUT ;
    USE SIGNAL ;
    PORT
      LAYER M3 ;
        RECT  147.168 0 147.186 0.144 ;
    END
  END xbi[192]
  PIN xbi[193]
    DIRECTION INPUT ;
    USE SIGNAL ;
    PORT
      LAYER M5 ;
        RECT  147.456 0 147.48 0.192 ;
    END
  END xbi[193]
  PIN xbi[194]
    DIRECTION INPUT ;
    USE SIGNAL ;
    PORT
      LAYER M3 ;
        RECT  147.744 0 147.762 0.144 ;
    END
  END xbi[194]
  PIN xbi[195]
    DIRECTION INPUT ;
    USE SIGNAL ;
    PORT
      LAYER M5 ;
        RECT  148.032 0 148.056 0.192 ;
    END
  END xbi[195]
  PIN xbi[196]
    DIRECTION INPUT ;
    USE SIGNAL ;
    PORT
      LAYER M3 ;
        RECT  148.32 0 148.338 0.144 ;
    END
  END xbi[196]
  PIN xbi[197]
    DIRECTION INPUT ;
    USE SIGNAL ;
    PORT
      LAYER M5 ;
        RECT  148.608 0 148.632 0.192 ;
    END
  END xbi[197]
  PIN xbi[198]
    DIRECTION INPUT ;
    USE SIGNAL ;
    PORT
      LAYER M3 ;
        RECT  148.896 0 148.914 0.144 ;
    END
  END xbi[198]
  PIN xbi[199]
    DIRECTION INPUT ;
    USE SIGNAL ;
    PORT
      LAYER M5 ;
        RECT  149.184 0 149.208 0.192 ;
    END
  END xbi[199]
  PIN xbi[19]
    DIRECTION INPUT ;
    USE SIGNAL ;
    PORT
      LAYER M5 ;
        RECT  96.96 0 96.984 0.192 ;
    END
  END xbi[19]
  PIN xbi[1]
    DIRECTION INPUT ;
    USE SIGNAL ;
    PORT
      LAYER M5 ;
        RECT  91.776 0 91.8 0.192 ;
    END
  END xbi[1]
  PIN xbi[200]
    DIRECTION INPUT ;
    USE SIGNAL ;
    PORT
      LAYER M3 ;
        RECT  149.472 0 149.49 0.144 ;
    END
  END xbi[200]
  PIN xbi[201]
    DIRECTION INPUT ;
    USE SIGNAL ;
    PORT
      LAYER M5 ;
        RECT  149.76 0 149.784 0.192 ;
    END
  END xbi[201]
  PIN xbi[202]
    DIRECTION INPUT ;
    USE SIGNAL ;
    PORT
      LAYER M3 ;
        RECT  150.048 0 150.066 0.144 ;
    END
  END xbi[202]
  PIN xbi[203]
    DIRECTION INPUT ;
    USE SIGNAL ;
    PORT
      LAYER M5 ;
        RECT  150.336 0 150.36 0.192 ;
    END
  END xbi[203]
  PIN xbi[204]
    DIRECTION INPUT ;
    USE SIGNAL ;
    PORT
      LAYER M3 ;
        RECT  150.624 0 150.642 0.144 ;
    END
  END xbi[204]
  PIN xbi[205]
    DIRECTION INPUT ;
    USE SIGNAL ;
    PORT
      LAYER M5 ;
        RECT  150.912 0 150.936 0.192 ;
    END
  END xbi[205]
  PIN xbi[206]
    DIRECTION INPUT ;
    USE SIGNAL ;
    PORT
      LAYER M3 ;
        RECT  151.2 0 151.218 0.144 ;
    END
  END xbi[206]
  PIN xbi[207]
    DIRECTION INPUT ;
    USE SIGNAL ;
    PORT
      LAYER M5 ;
        RECT  151.488 0 151.512 0.192 ;
    END
  END xbi[207]
  PIN xbi[208]
    DIRECTION INPUT ;
    USE SIGNAL ;
    PORT
      LAYER M3 ;
        RECT  151.776 0 151.794 0.144 ;
    END
  END xbi[208]
  PIN xbi[209]
    DIRECTION INPUT ;
    USE SIGNAL ;
    PORT
      LAYER M5 ;
        RECT  152.064 0 152.088 0.192 ;
    END
  END xbi[209]
  PIN xbi[20]
    DIRECTION INPUT ;
    USE SIGNAL ;
    PORT
      LAYER M3 ;
        RECT  97.272 0 97.29 0.144 ;
    END
  END xbi[20]
  PIN xbi[210]
    DIRECTION INPUT ;
    USE SIGNAL ;
    PORT
      LAYER M3 ;
        RECT  152.388 0 152.406 0.144 ;
    END
  END xbi[210]
  PIN xbi[211]
    DIRECTION INPUT ;
    USE SIGNAL ;
    PORT
      LAYER M5 ;
        RECT  152.64 0 152.664 0.192 ;
    END
  END xbi[211]
  PIN xbi[212]
    DIRECTION INPUT ;
    USE SIGNAL ;
    PORT
      LAYER M3 ;
        RECT  152.964 0 152.982 0.144 ;
    END
  END xbi[212]
  PIN xbi[213]
    DIRECTION INPUT ;
    USE SIGNAL ;
    PORT
      LAYER M5 ;
        RECT  153.264 0 153.288 0.192 ;
    END
  END xbi[213]
  PIN xbi[214]
    DIRECTION INPUT ;
    USE SIGNAL ;
    PORT
      LAYER M3 ;
        RECT  153.54 0 153.558 0.144 ;
    END
  END xbi[214]
  PIN xbi[215]
    DIRECTION INPUT ;
    USE SIGNAL ;
    PORT
      LAYER M5 ;
        RECT  153.84 0 153.864 0.192 ;
    END
  END xbi[215]
  PIN xbi[216]
    DIRECTION INPUT ;
    USE SIGNAL ;
    PORT
      LAYER M3 ;
        RECT  154.116 0 154.134 0.144 ;
    END
  END xbi[216]
  PIN xbi[217]
    DIRECTION INPUT ;
    USE SIGNAL ;
    PORT
      LAYER M5 ;
        RECT  154.416 0 154.44 0.192 ;
    END
  END xbi[217]
  PIN xbi[218]
    DIRECTION INPUT ;
    USE SIGNAL ;
    PORT
      LAYER M3 ;
        RECT  154.692 0 154.71 0.144 ;
    END
  END xbi[218]
  PIN xbi[219]
    DIRECTION INPUT ;
    USE SIGNAL ;
    PORT
      LAYER M5 ;
        RECT  154.992 0 155.016 0.192 ;
    END
  END xbi[219]
  PIN xbi[21]
    DIRECTION INPUT ;
    USE SIGNAL ;
    PORT
      LAYER M5 ;
        RECT  97.536 0 97.56 0.192 ;
    END
  END xbi[21]
  PIN xbi[220]
    DIRECTION INPUT ;
    USE SIGNAL ;
    PORT
      LAYER M3 ;
        RECT  155.268 0 155.286 0.144 ;
    END
  END xbi[220]
  PIN xbi[221]
    DIRECTION INPUT ;
    USE SIGNAL ;
    PORT
      LAYER M5 ;
        RECT  155.568 0 155.592 0.192 ;
    END
  END xbi[221]
  PIN xbi[222]
    DIRECTION INPUT ;
    USE SIGNAL ;
    PORT
      LAYER M3 ;
        RECT  155.844 0 155.862 0.144 ;
    END
  END xbi[222]
  PIN xbi[223]
    DIRECTION INPUT ;
    USE SIGNAL ;
    PORT
      LAYER M5 ;
        RECT  156.144 0 156.168 0.192 ;
    END
  END xbi[223]
  PIN xbi[224]
    DIRECTION INPUT ;
    USE SIGNAL ;
    PORT
      LAYER M3 ;
        RECT  156.42 0 156.438 0.144 ;
    END
  END xbi[224]
  PIN xbi[225]
    DIRECTION INPUT ;
    USE SIGNAL ;
    PORT
      LAYER M5 ;
        RECT  156.72 0 156.744 0.192 ;
    END
  END xbi[225]
  PIN xbi[226]
    DIRECTION INPUT ;
    USE SIGNAL ;
    PORT
      LAYER M3 ;
        RECT  157.032 0 157.05 0.144 ;
    END
  END xbi[226]
  PIN xbi[227]
    DIRECTION INPUT ;
    USE SIGNAL ;
    PORT
      LAYER M5 ;
        RECT  157.296 0 157.32 0.192 ;
    END
  END xbi[227]
  PIN xbi[228]
    DIRECTION INPUT ;
    USE SIGNAL ;
    PORT
      LAYER M3 ;
        RECT  157.608 0 157.626 0.144 ;
    END
  END xbi[228]
  PIN xbi[229]
    DIRECTION INPUT ;
    USE SIGNAL ;
    PORT
      LAYER M5 ;
        RECT  157.872 0 157.896 0.192 ;
    END
  END xbi[229]
  PIN xbi[22]
    DIRECTION INPUT ;
    USE SIGNAL ;
    PORT
      LAYER M3 ;
        RECT  97.848 0 97.866 0.144 ;
    END
  END xbi[22]
  PIN xbi[230]
    DIRECTION INPUT ;
    USE SIGNAL ;
    PORT
      LAYER M3 ;
        RECT  158.184 0 158.202 0.144 ;
    END
  END xbi[230]
  PIN xbi[231]
    DIRECTION INPUT ;
    USE SIGNAL ;
    PORT
      LAYER M5 ;
        RECT  158.448 0 158.472 0.192 ;
    END
  END xbi[231]
  PIN xbi[232]
    DIRECTION INPUT ;
    USE SIGNAL ;
    PORT
      LAYER M3 ;
        RECT  158.76 0 158.778 0.144 ;
    END
  END xbi[232]
  PIN xbi[233]
    DIRECTION INPUT ;
    USE SIGNAL ;
    PORT
      LAYER M5 ;
        RECT  159.024 0 159.048 0.192 ;
    END
  END xbi[233]
  PIN xbi[234]
    DIRECTION INPUT ;
    USE SIGNAL ;
    PORT
      LAYER M3 ;
        RECT  159.336 0 159.354 0.144 ;
    END
  END xbi[234]
  PIN xbi[235]
    DIRECTION INPUT ;
    USE SIGNAL ;
    PORT
      LAYER M5 ;
        RECT  159.6 0 159.624 0.192 ;
    END
  END xbi[235]
  PIN xbi[236]
    DIRECTION INPUT ;
    USE SIGNAL ;
    PORT
      LAYER M3 ;
        RECT  159.912 0 159.93 0.144 ;
    END
  END xbi[236]
  PIN xbi[237]
    DIRECTION INPUT ;
    USE SIGNAL ;
    PORT
      LAYER M5 ;
        RECT  160.224 0 160.248 0.192 ;
    END
  END xbi[237]
  PIN xbi[238]
    DIRECTION INPUT ;
    USE SIGNAL ;
    PORT
      LAYER M3 ;
        RECT  160.488 0 160.506 0.144 ;
    END
  END xbi[238]
  PIN xbi[239]
    DIRECTION INPUT ;
    USE SIGNAL ;
    PORT
      LAYER M5 ;
        RECT  160.8 0 160.824 0.192 ;
    END
  END xbi[239]
  PIN xbi[23]
    DIRECTION INPUT ;
    USE SIGNAL ;
    PORT
      LAYER M5 ;
        RECT  98.112 0 98.136 0.192 ;
    END
  END xbi[23]
  PIN xbi[240]
    DIRECTION INPUT ;
    USE SIGNAL ;
    PORT
      LAYER M3 ;
        RECT  161.064 0 161.082 0.144 ;
    END
  END xbi[240]
  PIN xbi[241]
    DIRECTION INPUT ;
    USE SIGNAL ;
    PORT
      LAYER M5 ;
        RECT  161.376 0 161.4 0.192 ;
    END
  END xbi[241]
  PIN xbi[242]
    DIRECTION INPUT ;
    USE SIGNAL ;
    PORT
      LAYER M3 ;
        RECT  161.64 0 161.658 0.144 ;
    END
  END xbi[242]
  PIN xbi[243]
    DIRECTION INPUT ;
    USE SIGNAL ;
    PORT
      LAYER M5 ;
        RECT  161.952 0 161.976 0.192 ;
    END
  END xbi[243]
  PIN xbi[244]
    DIRECTION INPUT ;
    USE SIGNAL ;
    PORT
      LAYER M3 ;
        RECT  162.252 0 162.27 0.144 ;
    END
  END xbi[244]
  PIN xbi[245]
    DIRECTION INPUT ;
    USE SIGNAL ;
    PORT
      LAYER M5 ;
        RECT  162.528 0 162.552 0.192 ;
    END
  END xbi[245]
  PIN xbi[246]
    DIRECTION INPUT ;
    USE SIGNAL ;
    PORT
      LAYER M3 ;
        RECT  162.828 0 162.846 0.144 ;
    END
  END xbi[246]
  PIN xbi[247]
    DIRECTION INPUT ;
    USE SIGNAL ;
    PORT
      LAYER M5 ;
        RECT  163.104 0 163.128 0.192 ;
    END
  END xbi[247]
  PIN xbi[248]
    DIRECTION INPUT ;
    USE SIGNAL ;
    PORT
      LAYER M3 ;
        RECT  163.404 0 163.422 0.144 ;
    END
  END xbi[248]
  PIN xbi[249]
    DIRECTION INPUT ;
    USE SIGNAL ;
    PORT
      LAYER M5 ;
        RECT  163.68 0 163.704 0.192 ;
    END
  END xbi[249]
  PIN xbi[24]
    DIRECTION INPUT ;
    USE SIGNAL ;
    PORT
      LAYER M3 ;
        RECT  98.424 0 98.442 0.144 ;
    END
  END xbi[24]
  PIN xbi[250]
    DIRECTION INPUT ;
    USE SIGNAL ;
    PORT
      LAYER M3 ;
        RECT  163.98 0 163.998 0.144 ;
    END
  END xbi[250]
  PIN xbi[251]
    DIRECTION INPUT ;
    USE SIGNAL ;
    PORT
      LAYER M5 ;
        RECT  164.256 0 164.28 0.192 ;
    END
  END xbi[251]
  PIN xbi[252]
    DIRECTION INPUT ;
    USE SIGNAL ;
    PORT
      LAYER M3 ;
        RECT  164.556 0 164.574 0.144 ;
    END
  END xbi[252]
  PIN xbi[253]
    DIRECTION INPUT ;
    USE SIGNAL ;
    PORT
      LAYER M5 ;
        RECT  164.832 0 164.856 0.192 ;
    END
  END xbi[253]
  PIN xbi[254]
    DIRECTION INPUT ;
    USE SIGNAL ;
    PORT
      LAYER M3 ;
        RECT  165.132 0 165.15 0.144 ;
    END
  END xbi[254]
  PIN xbi[255]
    DIRECTION INPUT ;
    USE SIGNAL ;
    PORT
      LAYER M5 ;
        RECT  165.408 0 165.432 0.192 ;
    END
  END xbi[255]
  PIN xbi[256]
    DIRECTION INPUT ;
    USE SIGNAL ;
    PORT
      LAYER M3 ;
        RECT  165.708 0 165.726 0.144 ;
    END
  END xbi[256]
  PIN xbi[257]
    DIRECTION INPUT ;
    USE SIGNAL ;
    PORT
      LAYER M5 ;
        RECT  165.984 0 166.008 0.192 ;
    END
  END xbi[257]
  PIN xbi[258]
    DIRECTION INPUT ;
    USE SIGNAL ;
    PORT
      LAYER M3 ;
        RECT  166.284 0 166.302 0.144 ;
    END
  END xbi[258]
  PIN xbi[259]
    DIRECTION INPUT ;
    USE SIGNAL ;
    PORT
      LAYER M5 ;
        RECT  166.56 0 166.584 0.192 ;
    END
  END xbi[259]
  PIN xbi[25]
    DIRECTION INPUT ;
    USE SIGNAL ;
    PORT
      LAYER M5 ;
        RECT  98.736 0 98.76 0.192 ;
    END
  END xbi[25]
  PIN xbi[260]
    DIRECTION INPUT ;
    USE SIGNAL ;
    PORT
      LAYER M3 ;
        RECT  166.86 0 166.878 0.144 ;
    END
  END xbi[260]
  PIN xbi[261]
    DIRECTION INPUT ;
    USE SIGNAL ;
    PORT
      LAYER M5 ;
        RECT  167.184 0 167.208 0.192 ;
    END
  END xbi[261]
  PIN xbi[262]
    DIRECTION INPUT ;
    USE SIGNAL ;
    PORT
      LAYER M3 ;
        RECT  167.472 0 167.49 0.144 ;
    END
  END xbi[262]
  PIN xbi[263]
    DIRECTION INPUT ;
    USE SIGNAL ;
    PORT
      LAYER M5 ;
        RECT  167.76 0 167.784 0.192 ;
    END
  END xbi[263]
  PIN xbi[264]
    DIRECTION INPUT ;
    USE SIGNAL ;
    PORT
      LAYER M3 ;
        RECT  168.048 0 168.066 0.144 ;
    END
  END xbi[264]
  PIN xbi[265]
    DIRECTION INPUT ;
    USE SIGNAL ;
    PORT
      LAYER M5 ;
        RECT  168.336 0 168.36 0.192 ;
    END
  END xbi[265]
  PIN xbi[26]
    DIRECTION INPUT ;
    USE SIGNAL ;
    PORT
      LAYER M3 ;
        RECT  99 0 99.018 0.144 ;
    END
  END xbi[26]
  PIN xbi[27]
    DIRECTION INPUT ;
    USE SIGNAL ;
    PORT
      LAYER M5 ;
        RECT  99.312 0 99.336 0.192 ;
    END
  END xbi[27]
  PIN xbi[28]
    DIRECTION INPUT ;
    USE SIGNAL ;
    PORT
      LAYER M3 ;
        RECT  99.576 0 99.594 0.144 ;
    END
  END xbi[28]
  PIN xbi[29]
    DIRECTION INPUT ;
    USE SIGNAL ;
    PORT
      LAYER M5 ;
        RECT  99.888 0 99.912 0.192 ;
    END
  END xbi[29]
  PIN xbi[2]
    DIRECTION INPUT ;
    USE SIGNAL ;
    PORT
      LAYER M3 ;
        RECT  92.052 0 92.07 0.144 ;
    END
  END xbi[2]
  PIN xbi[30]
    DIRECTION INPUT ;
    USE SIGNAL ;
    PORT
      LAYER M3 ;
        RECT  100.152 0 100.17 0.144 ;
    END
  END xbi[30]
  PIN xbi[31]
    DIRECTION INPUT ;
    USE SIGNAL ;
    PORT
      LAYER M5 ;
        RECT  100.464 0 100.488 0.192 ;
    END
  END xbi[31]
  PIN xbi[32]
    DIRECTION INPUT ;
    USE SIGNAL ;
    PORT
      LAYER M3 ;
        RECT  100.764 0 100.782 0.144 ;
    END
  END xbi[32]
  PIN xbi[33]
    DIRECTION INPUT ;
    USE SIGNAL ;
    PORT
      LAYER M5 ;
        RECT  101.04 0 101.064 0.192 ;
    END
  END xbi[33]
  PIN xbi[34]
    DIRECTION INPUT ;
    USE SIGNAL ;
    PORT
      LAYER M3 ;
        RECT  101.34 0 101.358 0.144 ;
    END
  END xbi[34]
  PIN xbi[35]
    DIRECTION INPUT ;
    USE SIGNAL ;
    PORT
      LAYER M5 ;
        RECT  101.616 0 101.64 0.192 ;
    END
  END xbi[35]
  PIN xbi[36]
    DIRECTION INPUT ;
    USE SIGNAL ;
    PORT
      LAYER M3 ;
        RECT  101.916 0 101.934 0.144 ;
    END
  END xbi[36]
  PIN xbi[37]
    DIRECTION INPUT ;
    USE SIGNAL ;
    PORT
      LAYER M5 ;
        RECT  102.192 0 102.216 0.192 ;
    END
  END xbi[37]
  PIN xbi[38]
    DIRECTION INPUT ;
    USE SIGNAL ;
    PORT
      LAYER M3 ;
        RECT  102.492 0 102.51 0.144 ;
    END
  END xbi[38]
  PIN xbi[39]
    DIRECTION INPUT ;
    USE SIGNAL ;
    PORT
      LAYER M5 ;
        RECT  102.768 0 102.792 0.192 ;
    END
  END xbi[39]
  PIN xbi[3]
    DIRECTION INPUT ;
    USE SIGNAL ;
    PORT
      LAYER M5 ;
        RECT  92.352 0 92.376 0.192 ;
    END
  END xbi[3]
  PIN xbi[40]
    DIRECTION INPUT ;
    USE SIGNAL ;
    PORT
      LAYER M3 ;
        RECT  103.068 0 103.086 0.144 ;
    END
  END xbi[40]
  PIN xbi[41]
    DIRECTION INPUT ;
    USE SIGNAL ;
    PORT
      LAYER M5 ;
        RECT  103.344 0 103.368 0.192 ;
    END
  END xbi[41]
  PIN xbi[42]
    DIRECTION INPUT ;
    USE SIGNAL ;
    PORT
      LAYER M3 ;
        RECT  103.644 0 103.662 0.144 ;
    END
  END xbi[42]
  PIN xbi[43]
    DIRECTION INPUT ;
    USE SIGNAL ;
    PORT
      LAYER M5 ;
        RECT  103.92 0 103.944 0.192 ;
    END
  END xbi[43]
  PIN xbi[44]
    DIRECTION INPUT ;
    USE SIGNAL ;
    PORT
      LAYER M3 ;
        RECT  104.22 0 104.238 0.144 ;
    END
  END xbi[44]
  PIN xbi[45]
    DIRECTION INPUT ;
    USE SIGNAL ;
    PORT
      LAYER M5 ;
        RECT  104.496 0 104.52 0.192 ;
    END
  END xbi[45]
  PIN xbi[46]
    DIRECTION INPUT ;
    USE SIGNAL ;
    PORT
      LAYER M3 ;
        RECT  104.796 0 104.814 0.144 ;
    END
  END xbi[46]
  PIN xbi[47]
    DIRECTION INPUT ;
    USE SIGNAL ;
    PORT
      LAYER M5 ;
        RECT  105.072 0 105.096 0.192 ;
    END
  END xbi[47]
  PIN xbi[48]
    DIRECTION INPUT ;
    USE SIGNAL ;
    PORT
      LAYER M3 ;
        RECT  105.372 0 105.39 0.144 ;
    END
  END xbi[48]
  PIN xbi[49]
    DIRECTION INPUT ;
    USE SIGNAL ;
    PORT
      LAYER M5 ;
        RECT  105.696 0 105.72 0.192 ;
    END
  END xbi[49]
  PIN xbi[4]
    DIRECTION INPUT ;
    USE SIGNAL ;
    PORT
      LAYER M3 ;
        RECT  92.628 0 92.646 0.144 ;
    END
  END xbi[4]
  PIN xbi[50]
    DIRECTION INPUT ;
    USE SIGNAL ;
    PORT
      LAYER M3 ;
        RECT  105.984 0 106.002 0.144 ;
    END
  END xbi[50]
  PIN xbi[51]
    DIRECTION INPUT ;
    USE SIGNAL ;
    PORT
      LAYER M5 ;
        RECT  106.272 0 106.296 0.192 ;
    END
  END xbi[51]
  PIN xbi[52]
    DIRECTION INPUT ;
    USE SIGNAL ;
    PORT
      LAYER M3 ;
        RECT  106.56 0 106.578 0.144 ;
    END
  END xbi[52]
  PIN xbi[53]
    DIRECTION INPUT ;
    USE SIGNAL ;
    PORT
      LAYER M5 ;
        RECT  106.848 0 106.872 0.192 ;
    END
  END xbi[53]
  PIN xbi[54]
    DIRECTION INPUT ;
    USE SIGNAL ;
    PORT
      LAYER M3 ;
        RECT  107.136 0 107.154 0.144 ;
    END
  END xbi[54]
  PIN xbi[55]
    DIRECTION INPUT ;
    USE SIGNAL ;
    PORT
      LAYER M5 ;
        RECT  107.424 0 107.448 0.192 ;
    END
  END xbi[55]
  PIN xbi[56]
    DIRECTION INPUT ;
    USE SIGNAL ;
    PORT
      LAYER M3 ;
        RECT  107.712 0 107.73 0.144 ;
    END
  END xbi[56]
  PIN xbi[57]
    DIRECTION INPUT ;
    USE SIGNAL ;
    PORT
      LAYER M5 ;
        RECT  108 0 108.024 0.192 ;
    END
  END xbi[57]
  PIN xbi[58]
    DIRECTION INPUT ;
    USE SIGNAL ;
    PORT
      LAYER M3 ;
        RECT  108.288 0 108.306 0.144 ;
    END
  END xbi[58]
  PIN xbi[59]
    DIRECTION INPUT ;
    USE SIGNAL ;
    PORT
      LAYER M5 ;
        RECT  108.576 0 108.6 0.192 ;
    END
  END xbi[59]
  PIN xbi[5]
    DIRECTION INPUT ;
    USE SIGNAL ;
    PORT
      LAYER M5 ;
        RECT  92.928 0 92.952 0.192 ;
    END
  END xbi[5]
  PIN xbi[60]
    DIRECTION INPUT ;
    USE SIGNAL ;
    PORT
      LAYER M3 ;
        RECT  108.864 0 108.882 0.144 ;
    END
  END xbi[60]
  PIN xbi[61]
    DIRECTION INPUT ;
    USE SIGNAL ;
    PORT
      LAYER M5 ;
        RECT  109.152 0 109.176 0.192 ;
    END
  END xbi[61]
  PIN xbi[62]
    DIRECTION INPUT ;
    USE SIGNAL ;
    PORT
      LAYER M3 ;
        RECT  109.44 0 109.458 0.144 ;
    END
  END xbi[62]
  PIN xbi[63]
    DIRECTION INPUT ;
    USE SIGNAL ;
    PORT
      LAYER M5 ;
        RECT  109.728 0 109.752 0.192 ;
    END
  END xbi[63]
  PIN xbi[64]
    DIRECTION INPUT ;
    USE SIGNAL ;
    PORT
      LAYER M3 ;
        RECT  110.016 0 110.034 0.144 ;
    END
  END xbi[64]
  PIN xbi[65]
    DIRECTION INPUT ;
    USE SIGNAL ;
    PORT
      LAYER M5 ;
        RECT  110.304 0 110.328 0.192 ;
    END
  END xbi[65]
  PIN xbi[66]
    DIRECTION INPUT ;
    USE SIGNAL ;
    PORT
      LAYER M3 ;
        RECT  110.592 0 110.61 0.144 ;
    END
  END xbi[66]
  PIN xbi[67]
    DIRECTION INPUT ;
    USE SIGNAL ;
    PORT
      LAYER M5 ;
        RECT  110.88 0 110.904 0.192 ;
    END
  END xbi[67]
  PIN xbi[68]
    DIRECTION INPUT ;
    USE SIGNAL ;
    PORT
      LAYER M3 ;
        RECT  111.204 0 111.222 0.144 ;
    END
  END xbi[68]
  PIN xbi[69]
    DIRECTION INPUT ;
    USE SIGNAL ;
    PORT
      LAYER M5 ;
        RECT  111.456 0 111.48 0.192 ;
    END
  END xbi[69]
  PIN xbi[6]
    DIRECTION INPUT ;
    USE SIGNAL ;
    PORT
      LAYER M3 ;
        RECT  93.204 0 93.222 0.144 ;
    END
  END xbi[6]
  PIN xbi[70]
    DIRECTION INPUT ;
    USE SIGNAL ;
    PORT
      LAYER M3 ;
        RECT  111.78 0 111.798 0.144 ;
    END
  END xbi[70]
  PIN xbi[71]
    DIRECTION INPUT ;
    USE SIGNAL ;
    PORT
      LAYER M5 ;
        RECT  112.08 0 112.104 0.192 ;
    END
  END xbi[71]
  PIN xbi[72]
    DIRECTION INPUT ;
    USE SIGNAL ;
    PORT
      LAYER M3 ;
        RECT  112.356 0 112.374 0.144 ;
    END
  END xbi[72]
  PIN xbi[73]
    DIRECTION INPUT ;
    USE SIGNAL ;
    PORT
      LAYER M5 ;
        RECT  112.656 0 112.68 0.192 ;
    END
  END xbi[73]
  PIN xbi[74]
    DIRECTION INPUT ;
    USE SIGNAL ;
    PORT
      LAYER M3 ;
        RECT  112.932 0 112.95 0.144 ;
    END
  END xbi[74]
  PIN xbi[75]
    DIRECTION INPUT ;
    USE SIGNAL ;
    PORT
      LAYER M5 ;
        RECT  113.232 0 113.256 0.192 ;
    END
  END xbi[75]
  PIN xbi[76]
    DIRECTION INPUT ;
    USE SIGNAL ;
    PORT
      LAYER M3 ;
        RECT  113.508 0 113.526 0.144 ;
    END
  END xbi[76]
  PIN xbi[77]
    DIRECTION INPUT ;
    USE SIGNAL ;
    PORT
      LAYER M5 ;
        RECT  113.808 0 113.832 0.192 ;
    END
  END xbi[77]
  PIN xbi[78]
    DIRECTION INPUT ;
    USE SIGNAL ;
    PORT
      LAYER M3 ;
        RECT  114.084 0 114.102 0.144 ;
    END
  END xbi[78]
  PIN xbi[79]
    DIRECTION INPUT ;
    USE SIGNAL ;
    PORT
      LAYER M5 ;
        RECT  114.384 0 114.408 0.192 ;
    END
  END xbi[79]
  PIN xbi[7]
    DIRECTION INPUT ;
    USE SIGNAL ;
    PORT
      LAYER M5 ;
        RECT  93.504 0 93.528 0.192 ;
    END
  END xbi[7]
  PIN xbi[80]
    DIRECTION INPUT ;
    USE SIGNAL ;
    PORT
      LAYER M3 ;
        RECT  114.66 0 114.678 0.144 ;
    END
  END xbi[80]
  PIN xbi[81]
    DIRECTION INPUT ;
    USE SIGNAL ;
    PORT
      LAYER M5 ;
        RECT  114.96 0 114.984 0.192 ;
    END
  END xbi[81]
  PIN xbi[82]
    DIRECTION INPUT ;
    USE SIGNAL ;
    PORT
      LAYER M3 ;
        RECT  115.236 0 115.254 0.144 ;
    END
  END xbi[82]
  PIN xbi[83]
    DIRECTION INPUT ;
    USE SIGNAL ;
    PORT
      LAYER M5 ;
        RECT  115.536 0 115.56 0.192 ;
    END
  END xbi[83]
  PIN xbi[84]
    DIRECTION INPUT ;
    USE SIGNAL ;
    PORT
      LAYER M3 ;
        RECT  115.812 0 115.83 0.144 ;
    END
  END xbi[84]
  PIN xbi[85]
    DIRECTION INPUT ;
    USE SIGNAL ;
    PORT
      LAYER M5 ;
        RECT  116.112 0 116.136 0.192 ;
    END
  END xbi[85]
  PIN xbi[86]
    DIRECTION INPUT ;
    USE SIGNAL ;
    PORT
      LAYER M3 ;
        RECT  116.424 0 116.442 0.144 ;
    END
  END xbi[86]
  PIN xbi[87]
    DIRECTION INPUT ;
    USE SIGNAL ;
    PORT
      LAYER M5 ;
        RECT  116.688 0 116.712 0.192 ;
    END
  END xbi[87]
  PIN xbi[88]
    DIRECTION INPUT ;
    USE SIGNAL ;
    PORT
      LAYER M3 ;
        RECT  117 0 117.018 0.144 ;
    END
  END xbi[88]
  PIN xbi[89]
    DIRECTION INPUT ;
    USE SIGNAL ;
    PORT
      LAYER M5 ;
        RECT  117.264 0 117.288 0.192 ;
    END
  END xbi[89]
  PIN xbi[8]
    DIRECTION INPUT ;
    USE SIGNAL ;
    PORT
      LAYER M3 ;
        RECT  93.78 0 93.798 0.144 ;
    END
  END xbi[8]
  PIN xbi[90]
    DIRECTION INPUT ;
    USE SIGNAL ;
    PORT
      LAYER M3 ;
        RECT  117.576 0 117.594 0.144 ;
    END
  END xbi[90]
  PIN xbi[91]
    DIRECTION INPUT ;
    USE SIGNAL ;
    PORT
      LAYER M5 ;
        RECT  117.84 0 117.864 0.192 ;
    END
  END xbi[91]
  PIN xbi[92]
    DIRECTION INPUT ;
    USE SIGNAL ;
    PORT
      LAYER M3 ;
        RECT  118.152 0 118.17 0.144 ;
    END
  END xbi[92]
  PIN xbi[93]
    DIRECTION INPUT ;
    USE SIGNAL ;
    PORT
      LAYER M5 ;
        RECT  118.416 0 118.44 0.192 ;
    END
  END xbi[93]
  PIN xbi[94]
    DIRECTION INPUT ;
    USE SIGNAL ;
    PORT
      LAYER M3 ;
        RECT  118.728 0 118.746 0.144 ;
    END
  END xbi[94]
  PIN xbi[95]
    DIRECTION INPUT ;
    USE SIGNAL ;
    PORT
      LAYER M5 ;
        RECT  119.04 0 119.064 0.192 ;
    END
  END xbi[95]
  PIN xbi[96]
    DIRECTION INPUT ;
    USE SIGNAL ;
    PORT
      LAYER M3 ;
        RECT  119.304 0 119.322 0.144 ;
    END
  END xbi[96]
  PIN xbi[97]
    DIRECTION INPUT ;
    USE SIGNAL ;
    PORT
      LAYER M5 ;
        RECT  119.616 0 119.64 0.192 ;
    END
  END xbi[97]
  PIN xbi[98]
    DIRECTION INPUT ;
    USE SIGNAL ;
    PORT
      LAYER M3 ;
        RECT  119.88 0 119.898 0.144 ;
    END
  END xbi[98]
  PIN xbi[99]
    DIRECTION INPUT ;
    USE SIGNAL ;
    PORT
      LAYER M5 ;
        RECT  120.192 0 120.216 0.192 ;
    END
  END xbi[99]
  PIN xbi[9]
    DIRECTION INPUT ;
    USE SIGNAL ;
    PORT
      LAYER M5 ;
        RECT  94.08 0 94.104 0.192 ;
    END
  END xbi[9]
  PIN VDD
    DIRECTION INOUT ;
    USE POWER ;
    PORT
      LAYER M5 ;
        RECT  169.992 2.151 170.112 28.089 ;
        RECT  167.292 2.151 167.412 28.089 ;
        RECT  164.592 2.151 164.712 28.089 ;
        RECT  161.892 2.151 162.012 28.089 ;
        RECT  159.192 2.151 159.312 28.089 ;
        RECT  156.492 2.151 156.612 28.089 ;
        RECT  153.792 2.151 153.912 28.089 ;
        RECT  151.092 2.151 151.212 28.089 ;
        RECT  148.392 2.151 148.512 28.089 ;
        RECT  145.692 2.151 145.812 28.089 ;
        RECT  142.992 2.151 143.112 28.089 ;
        RECT  140.292 2.151 140.412 28.089 ;
        RECT  137.592 2.151 137.712 28.089 ;
        RECT  134.892 2.151 135.012 28.089 ;
        RECT  132.192 2.151 132.312 28.089 ;
        RECT  129.492 2.151 129.612 28.089 ;
        RECT  126.792 2.151 126.912 28.089 ;
        RECT  124.092 2.151 124.212 28.089 ;
        RECT  121.392 2.151 121.512 28.089 ;
        RECT  118.692 2.151 118.812 28.089 ;
        RECT  115.992 2.151 116.112 28.089 ;
        RECT  113.292 2.151 113.412 28.089 ;
        RECT  110.592 2.151 110.712 28.089 ;
        RECT  107.892 2.151 108.012 28.089 ;
        RECT  105.192 2.151 105.312 28.089 ;
        RECT  102.492 2.151 102.612 28.089 ;
        RECT  99.792 2.151 99.912 28.089 ;
        RECT  97.092 2.151 97.212 28.089 ;
        RECT  94.392 2.151 94.512 28.089 ;
        RECT  91.692 2.151 91.812 28.089 ;
        RECT  88.992 2.151 89.112 28.089 ;
        RECT  86.292 2.151 86.412 28.089 ;
        RECT  83.592 2.151 83.712 28.089 ;
        RECT  80.892 2.151 81.012 28.089 ;
        RECT  78.192 2.151 78.312 28.089 ;
        RECT  75.492 2.151 75.612 28.089 ;
        RECT  72.792 2.151 72.912 28.089 ;
        RECT  70.092 2.151 70.212 28.089 ;
        RECT  67.392 2.151 67.512 28.089 ;
        RECT  64.692 2.151 64.812 28.089 ;
        RECT  61.992 2.151 62.112 28.089 ;
        RECT  59.292 2.151 59.412 28.089 ;
        RECT  56.592 2.151 56.712 28.089 ;
        RECT  53.892 2.151 54.012 28.089 ;
        RECT  51.192 2.151 51.312 28.089 ;
        RECT  48.492 2.151 48.612 28.089 ;
        RECT  45.792 2.151 45.912 28.089 ;
        RECT  43.092 2.151 43.212 28.089 ;
        RECT  40.392 2.151 40.512 28.089 ;
        RECT  37.692 2.151 37.812 28.089 ;
        RECT  34.992 2.151 35.112 28.089 ;
        RECT  32.292 2.151 32.412 28.089 ;
        RECT  29.592 2.151 29.712 28.089 ;
        RECT  26.892 2.151 27.012 28.089 ;
        RECT  24.192 2.151 24.312 28.089 ;
        RECT  21.492 2.151 21.612 28.089 ;
        RECT  18.792 2.151 18.912 28.089 ;
        RECT  16.092 2.151 16.212 28.089 ;
        RECT  13.392 2.151 13.512 28.089 ;
        RECT  10.692 2.151 10.812 28.089 ;
        RECT  7.992 2.151 8.112 28.089 ;
        RECT  5.292 2.151 5.412 28.089 ;
        RECT  2.592 2.151 2.712 28.089 ;
    END
  END VDD
  PIN VSS
    DIRECTION INOUT ;
    USE GROUND ;
    PORT
      LAYER M5 ;
        RECT  169.8 2.137 169.92 28.103 ;
        RECT  167.1 2.137 167.22 28.103 ;
        RECT  164.4 2.137 164.52 28.103 ;
        RECT  161.7 2.137 161.82 28.103 ;
        RECT  159 2.137 159.12 28.103 ;
        RECT  156.3 2.137 156.42 28.103 ;
        RECT  153.6 2.137 153.72 28.103 ;
        RECT  150.9 2.137 151.02 28.103 ;
        RECT  148.2 2.137 148.32 28.103 ;
        RECT  145.5 2.137 145.62 28.103 ;
        RECT  142.8 2.137 142.92 28.103 ;
        RECT  140.1 2.137 140.22 28.103 ;
        RECT  137.4 2.137 137.52 28.103 ;
        RECT  134.7 2.137 134.82 28.103 ;
        RECT  132 2.137 132.12 28.103 ;
        RECT  129.3 2.137 129.42 28.103 ;
        RECT  126.6 2.137 126.72 28.103 ;
        RECT  123.9 2.137 124.02 28.103 ;
        RECT  121.2 2.137 121.32 28.103 ;
        RECT  118.5 2.137 118.62 28.103 ;
        RECT  115.8 2.137 115.92 28.103 ;
        RECT  113.1 2.137 113.22 28.103 ;
        RECT  110.4 2.137 110.52 28.103 ;
        RECT  107.7 2.137 107.82 28.103 ;
        RECT  105 2.137 105.12 28.103 ;
        RECT  102.3 2.137 102.42 28.103 ;
        RECT  99.6 2.137 99.72 28.103 ;
        RECT  96.9 2.137 97.02 28.103 ;
        RECT  94.2 2.137 94.32 28.103 ;
        RECT  91.5 2.137 91.62 28.103 ;
        RECT  88.8 2.137 88.92 28.103 ;
        RECT  86.1 2.137 86.22 28.103 ;
        RECT  83.4 2.137 83.52 28.103 ;
        RECT  80.7 2.137 80.82 28.103 ;
        RECT  78 2.137 78.12 28.103 ;
        RECT  75.3 2.137 75.42 28.103 ;
        RECT  72.6 2.137 72.72 28.103 ;
        RECT  69.9 2.137 70.02 28.103 ;
        RECT  67.2 2.137 67.32 28.103 ;
        RECT  64.5 2.137 64.62 28.103 ;
        RECT  61.8 2.137 61.92 28.103 ;
        RECT  59.1 2.137 59.22 28.103 ;
        RECT  56.4 2.137 56.52 28.103 ;
        RECT  53.7 2.137 53.82 28.103 ;
        RECT  51 2.137 51.12 28.103 ;
        RECT  48.3 2.137 48.42 28.103 ;
        RECT  45.6 2.137 45.72 28.103 ;
        RECT  42.9 2.137 43.02 28.103 ;
        RECT  40.2 2.137 40.32 28.103 ;
        RECT  37.5 2.137 37.62 28.103 ;
        RECT  34.8 2.137 34.92 28.103 ;
        RECT  32.1 2.137 32.22 28.103 ;
        RECT  29.4 2.137 29.52 28.103 ;
        RECT  26.7 2.137 26.82 28.103 ;
        RECT  24 2.137 24.12 28.103 ;
        RECT  21.3 2.137 21.42 28.103 ;
        RECT  18.6 2.137 18.72 28.103 ;
        RECT  15.9 2.137 16.02 28.103 ;
        RECT  13.2 2.137 13.32 28.103 ;
        RECT  10.5 2.137 10.62 28.103 ;
        RECT  7.8 2.137 7.92 28.103 ;
        RECT  5.1 2.137 5.22 28.103 ;
        RECT  2.4 2.137 2.52 28.103 ;
    END
  END VSS
  # OT_OBS_CLOSED layer=M5 d_um=1.536 added=302
  OBS
    LAYER RVTN ;
     RECT  2.16 2.16 170.64 2.295 ;
     RECT  2.16 2.565 170.64 2.835 ;
     RECT  2.16 3.105 170.64 3.375 ;
     RECT  2.16 3.645 170.64 3.915 ;
     RECT  2.16 4.185 170.64 4.455 ;
     RECT  2.16 4.725 170.64 4.995 ;
     RECT  2.16 5.265 170.64 5.535 ;
     RECT  2.16 5.805 170.64 6.075 ;
     RECT  2.16 6.345 170.64 6.615 ;
     RECT  2.16 6.885 170.64 7.155 ;
     RECT  2.16 7.425 170.64 7.695 ;
     RECT  2.16 7.965 170.64 8.235 ;
     RECT  2.16 8.505 170.64 8.775 ;
     RECT  2.16 9.045 170.64 9.315 ;
     RECT  2.16 9.585 170.64 9.855 ;
     RECT  2.16 10.125 170.64 10.395 ;
     RECT  2.16 10.665 170.64 10.935 ;
     RECT  2.16 11.205 170.64 11.475 ;
     RECT  2.16 11.745 170.64 12.015 ;
     RECT  2.16 12.285 170.64 12.555 ;
     RECT  2.16 12.825 170.64 13.095 ;
     RECT  2.16 13.365 170.64 13.635 ;
     RECT  2.16 13.905 170.64 14.175 ;
     RECT  2.16 14.445 170.64 14.715 ;
     RECT  2.16 14.985 170.64 15.255 ;
     RECT  2.16 15.525 170.64 15.795 ;
     RECT  2.16 16.065 170.64 16.335 ;
     RECT  2.16 16.605 170.64 16.875 ;
     RECT  2.16 17.145 170.64 17.415 ;
     RECT  2.16 17.685 170.64 17.955 ;
     RECT  2.16 18.225 170.64 18.495 ;
     RECT  2.16 18.765 170.64 19.035 ;
     RECT  2.16 19.305 170.64 19.575 ;
     RECT  2.16 19.845 170.64 20.115 ;
     RECT  2.16 20.385 170.64 20.655 ;
     RECT  2.16 20.925 170.64 21.195 ;
     RECT  2.16 21.465 170.64 21.735 ;
     RECT  2.16 22.005 170.64 22.275 ;
     RECT  2.16 22.545 170.64 22.815 ;
     RECT  2.16 23.085 170.64 23.355 ;
     RECT  2.16 23.625 170.64 23.895 ;
     RECT  2.16 24.165 170.64 24.435 ;
     RECT  2.16 24.705 170.64 24.975 ;
     RECT  2.16 25.245 170.64 25.515 ;
     RECT  2.16 25.785 170.64 26.055 ;
     RECT  2.16 26.325 170.64 26.595 ;
     RECT  2.16 26.865 170.64 27.135 ;
     RECT  2.16 27.405 170.64 27.675 ;
     RECT  2.16 27.945 170.64 28.08 ;
    LAYER RVTP ;
     RECT  2.16 2.295 170.64 2.565 ;
     RECT  2.16 2.835 170.64 3.105 ;
     RECT  2.16 3.375 170.64 3.645 ;
     RECT  2.16 3.915 170.64 4.185 ;
     RECT  2.16 4.455 170.64 4.725 ;
     RECT  2.16 4.995 170.64 5.265 ;
     RECT  2.16 5.535 170.64 5.805 ;
     RECT  2.16 6.075 170.64 6.345 ;
     RECT  2.16 6.615 170.64 6.885 ;
     RECT  2.16 7.155 170.64 7.425 ;
     RECT  2.16 7.695 170.64 7.965 ;
     RECT  2.16 8.235 170.64 8.505 ;
     RECT  2.16 8.775 170.64 9.045 ;
     RECT  2.16 9.315 170.64 9.585 ;
     RECT  2.16 9.855 170.64 10.125 ;
     RECT  2.16 10.395 170.64 10.665 ;
     RECT  2.16 10.935 170.64 11.205 ;
     RECT  2.16 11.475 170.64 11.745 ;
     RECT  2.16 12.015 170.64 12.285 ;
     RECT  2.16 12.555 170.64 12.825 ;
     RECT  2.16 13.095 170.64 13.365 ;
     RECT  2.16 13.635 170.64 13.905 ;
     RECT  2.16 14.175 170.64 14.445 ;
     RECT  2.16 14.715 170.64 14.985 ;
     RECT  2.16 15.255 170.64 15.525 ;
     RECT  2.16 15.795 170.64 16.065 ;
     RECT  2.16 16.335 170.64 16.605 ;
     RECT  2.16 16.875 170.64 17.145 ;
     RECT  2.16 17.415 170.64 17.685 ;
     RECT  2.16 17.955 170.64 18.225 ;
     RECT  2.16 18.495 170.64 18.765 ;
     RECT  2.16 19.035 170.64 19.305 ;
     RECT  2.16 19.575 170.64 19.845 ;
     RECT  2.16 20.115 170.64 20.385 ;
     RECT  2.16 20.655 170.64 20.925 ;
     RECT  2.16 21.195 170.64 21.465 ;
     RECT  2.16 21.735 170.64 22.005 ;
     RECT  2.16 22.275 170.64 22.545 ;
     RECT  2.16 22.815 170.64 23.085 ;
     RECT  2.16 23.355 170.64 23.625 ;
     RECT  2.16 23.895 170.64 24.165 ;
     RECT  2.16 24.435 170.64 24.705 ;
     RECT  2.16 24.975 170.64 25.245 ;
     RECT  2.16 25.515 170.64 25.785 ;
     RECT  2.16 26.055 170.64 26.325 ;
     RECT  2.16 26.595 170.64 26.865 ;
     RECT  2.16 27.135 170.64 27.405 ;
     RECT  2.16 27.675 170.64 27.945 ;
    LAYER M1 ;
     RECT  2.16 2.151 170.64 28.089 ;
    LAYER M2 ;
     RECT  2.16 2.151 4.243 28.089 ;
     RECT  4.243 1.728 5.063 28.089 ;
     RECT  6.115 0.144 6.215 0.162 ;
     RECT  5.063 2.151 7.591 28.089 ;
     RECT  7.771 0.144 7.943 0.162 ;
     RECT  7.591 2.151 7.943 28.17 ;
     RECT  9.319 29.034 9.455 29.052 ;
     RECT  11.767 29.034 11.975 29.052 ;
     RECT  15.403 28.962 15.475 28.98 ;
     RECT  15.475 28.962 15.503 29.052 ;
     RECT  15.503 29.034 15.575 29.052 ;
     RECT  7.943 2.151 15.979 28.089 ;
     RECT  15.979 2.151 16.295 28.17 ;
     RECT  16.555 29.034 16.799 29.052 ;
     RECT  16.295 2.151 19.543 28.089 ;
     RECT  19.543 1.728 19.715 28.089 ;
     RECT  19.435 29.034 19.715 29.052 ;
     RECT  20.587 29.034 20.831 29.052 ;
     RECT  21.739 29.034 21.911 29.052 ;
     RECT  23.467 29.034 24.071 29.052 ;
     RECT  29.335 0.144 29.435 0.162 ;
     RECT  19.715 2.151 30.271 28.089 ;
     RECT  30.271 1.728 30.587 28.089 ;
     RECT  29.803 29.034 31.199 29.052 ;
     RECT  30.587 2.151 31.999 28.089 ;
     RECT  31.999 1.728 32.107 28.089 ;
     RECT  32.107 1.728 32.315 28.476 ;
     RECT  32.315 2.151 32.675 28.476 ;
     RECT  37.435 0.144 37.535 0.162 ;
     RECT  41.215 29.034 41.315 29.052 ;
     RECT  32.675 2.151 41.935 28.089 ;
     RECT  41.935 1.728 42.179 28.089 ;
     RECT  42.835 29.034 43.079 29.052 ;
     RECT  42.179 2.151 43.843 28.089 ;
     RECT  43.843 2.106 43.879 28.089 ;
     RECT  43.879 1.728 44.051 28.089 ;
     RECT  44.051 2.106 44.735 28.089 ;
     RECT  44.779 29.034 44.879 29.052 ;
     RECT  44.735 2.151 45.643 28.089 ;
     RECT  45.643 1.728 45.779 28.089 ;
     RECT  45.779 2.151 47.407 28.089 ;
     RECT  47.407 2.106 47.759 28.089 ;
     RECT  48.091 29.034 48.263 29.052 ;
     RECT  47.759 2.151 49.099 28.089 ;
     RECT  49.099 1.728 49.235 28.089 ;
     RECT  49.235 2.151 51.115 28.089 ;
     RECT  51.115 2.151 51.611 28.17 ;
     RECT  51.611 2.151 53.455 28.089 ;
     RECT  53.455 2.106 53.671 28.089 ;
     RECT  53.671 1.728 53.771 28.089 ;
     RECT  53.995 30.078 54.031 30.096 ;
     RECT  54.031 30.078 54.131 30.168 ;
     RECT  53.771 2.106 54.563 28.089 ;
     RECT  54.571 29.034 55.175 29.052 ;
     RECT  54.563 2.151 59.179 28.089 ;
     RECT  59.179 2.151 59.279 28.17 ;
     RECT  61.879 0.144 61.979 0.162 ;
     RECT  59.279 2.151 65.083 28.089 ;
     RECT  65.083 2.106 65.363 28.089 ;
     RECT  65.363 2.151 67.099 28.089 ;
     RECT  67.099 2.151 67.271 28.17 ;
     RECT  68.683 29.034 68.891 29.052 ;
     RECT  67.271 2.151 69.151 28.089 ;
     RECT  69.151 1.728 69.431 28.089 ;
     RECT  69.871 0.144 70.619 0.162 ;
     RECT  69.431 2.151 72.175 28.089 ;
     RECT  72.175 1.728 72.347 28.089 ;
     RECT  72.427 30.078 72.463 30.096 ;
     RECT  72.463 30.078 72.563 30.168 ;
     RECT  73.219 29.034 73.751 29.052 ;
     RECT  74.731 29.034 74.831 29.052 ;
     RECT  72.347 2.151 75.307 28.089 ;
     RECT  75.307 2.151 75.479 28.17 ;
     RECT  75.883 29.034 76.091 29.052 ;
     RECT  78.115 0.144 78.359 0.162 ;
     RECT  79.915 29.034 81.311 29.052 ;
     RECT  82.219 30.078 82.255 30.096 ;
     RECT  82.255 30.078 82.355 30.168 ;
     RECT  75.479 2.151 83.911 28.089 ;
     RECT  83.911 1.728 84.083 28.089 ;
     RECT  83.947 29.034 84.155 29.052 ;
     RECT  86.827 29.034 87.071 29.052 ;
     RECT  84.083 2.151 87.403 28.089 ;
     RECT  87.403 1.728 87.539 28.089 ;
     RECT  88.555 29.034 88.655 29.052 ;
     RECT  87.539 2.151 90.895 28.089 ;
     RECT  90.895 1.728 90.995 28.089 ;
     RECT  93.163 29.034 93.839 29.052 ;
     RECT  90.995 2.151 94.171 28.089 ;
     RECT  94.171 2.151 94.343 28.17 ;
     RECT  94.343 2.151 95.935 28.089 ;
     RECT  95.935 2.106 96.395 28.089 ;
     RECT  96.395 2.151 98.995 28.089 ;
     RECT  98.923 29.034 99.059 29.052 ;
     RECT  98.995 2.106 99.203 28.089 ;
     RECT  99.203 2.151 100.759 28.089 ;
     RECT  100.759 2.106 100.967 28.089 ;
     RECT  100.075 29.034 101.327 29.052 ;
     RECT  100.967 2.151 102.091 28.089 ;
     RECT  102.091 2.151 102.407 28.17 ;
     RECT  102.883 29.034 102.983 29.052 ;
     RECT  102.407 2.151 103.639 28.089 ;
     RECT  103.639 2.106 103.847 28.089 ;
     RECT  104.611 29.034 105.395 29.052 ;
     RECT  106.411 30.078 106.447 30.096 ;
     RECT  106.447 30.078 106.547 30.168 ;
     RECT  107.599 0.144 107.735 0.162 ;
     RECT  108.427 29.034 108.743 29.052 ;
     RECT  103.847 2.151 108.859 28.089 ;
     RECT  108.859 1.728 109.031 28.089 ;
     RECT  109.031 2.151 110.443 28.089 ;
     RECT  110.443 2.151 111.019 28.17 ;
     RECT  111.019 2.151 111.119 28.278 ;
     RECT  111.119 2.151 112.351 28.089 ;
     RECT  112.351 1.728 112.487 28.089 ;
     RECT  112.747 29.736 112.847 29.754 ;
     RECT  113.755 29.034 113.927 29.052 ;
     RECT  112.487 2.151 114.079 28.089 ;
     RECT  114.079 1.728 114.215 28.089 ;
     RECT  114.907 29.034 115.079 29.052 ;
     RECT  114.215 2.151 115.807 28.089 ;
     RECT  115.807 1.728 115.979 28.089 ;
     RECT  116.707 29.034 116.807 29.052 ;
     RECT  117.571 0.144 117.671 0.162 ;
     RECT  115.979 2.151 118.183 28.089 ;
     RECT  118.183 2.151 118.535 28.17 ;
     RECT  118.535 2.151 120.343 28.089 ;
     RECT  120.343 1.728 120.479 28.089 ;
     RECT  123.871 0.144 123.971 0.162 ;
     RECT  122.539 29.034 124.079 29.052 ;
     RECT  120.479 2.151 128.587 28.089 ;
     RECT  128.587 1.728 128.795 28.089 ;
     RECT  129.451 29.034 130.235 29.052 ;
     RECT  128.795 2.151 131.899 28.089 ;
     RECT  131.899 1.728 132.107 28.089 ;
     RECT  132.107 2.106 132.791 28.089 ;
     RECT  132.907 29.034 133.331 29.052 ;
     RECT  134.311 0.144 134.411 0.162 ;
     RECT  135.787 29.034 137.795 29.052 ;
     RECT  139.243 29.034 139.559 29.052 ;
     RECT  140.071 0.144 140.207 0.162 ;
     RECT  141.979 29.034 142.151 29.052 ;
     RECT  132.791 2.151 142.519 28.089 ;
     RECT  142.519 1.728 142.619 28.089 ;
     RECT  142.619 2.151 144.247 28.089 ;
     RECT  144.247 1.728 144.347 28.089 ;
     RECT  144.347 2.151 145.579 28.089 ;
     RECT  145.579 2.151 145.975 28.17 ;
     RECT  145.975 1.728 146.039 28.17 ;
     RECT  146.039 1.728 146.075 28.089 ;
     RECT  148.315 0.144 148.415 0.162 ;
     RECT  146.075 2.151 148.891 28.089 ;
     RECT  148.891 1.728 149.099 28.089 ;
     RECT  150.187 29.034 150.287 29.052 ;
     RECT  149.099 2.151 150.619 28.089 ;
     RECT  150.619 1.728 150.827 28.089 ;
     RECT  151.339 29.196 151.375 29.214 ;
     RECT  151.375 29.034 151.583 29.214 ;
     RECT  152.383 0.144 152.483 0.162 ;
     RECT  153.643 29.034 153.779 29.052 ;
     RECT  150.827 2.151 155.263 28.089 ;
     RECT  155.263 1.728 155.471 28.089 ;
     RECT  155.371 29.034 155.471 29.052 ;
     RECT  156.415 0.144 156.659 0.162 ;
     RECT  155.471 2.151 157.027 28.089 ;
     RECT  157.027 1.728 157.199 28.089 ;
     RECT  157.199 2.151 158.755 28.089 ;
     RECT  158.683 29.196 158.855 29.214 ;
     RECT  158.755 1.728 158.927 28.089 ;
     RECT  158.927 2.151 159.115 28.089 ;
     RECT  159.115 2.151 159.503 28.17 ;
     RECT  160.483 29.034 162.283 29.052 ;
     RECT  162.283 29.034 162.419 29.214 ;
     RECT  164.371 29.034 164.615 29.052 ;
     RECT  165.739 30.078 165.775 30.096 ;
     RECT  165.775 30.078 165.875 30.168 ;
     RECT  159.503 2.151 170.64 28.089 ;
     RECT  170.64 15.228 171.023 15.246 ;
    LAYER M3 ;
     RECT  4.464 0.108 168.066 0.167 ;
     RECT  4.464 0.167 7.794 1.723 ;
     RECT  8.532 0.167 77.562 1.723 ;
     RECT  78.336 0.167 155.862 1.723 ;
     RECT  156.636 0.167 168.066 1.723 ;
     RECT  4.248 1.723 168.426 2.263 ;
     RECT  4.176 2.263 168.426 2.371 ;
     RECT  2.415 2.143 2.505 2.413 ;
     RECT  169.815 2.143 169.905 2.413 ;
     RECT  4.176 2.371 168.534 2.489 ;
     RECT  5.04 2.489 168.534 2.641 ;
     RECT  5.04 2.641 168.894 2.759 ;
     RECT  5.04 2.759 124.614 2.795 ;
     RECT  125.352 2.759 168.894 2.795 ;
     RECT  28.368 2.795 51.426 2.861 ;
     RECT  82.476 2.795 91.797 2.861 ;
     RECT  92.52 2.795 93.078 2.861 ;
     RECT  93.888 2.795 124.614 2.861 ;
     RECT  125.352 2.795 141.858 2.861 ;
     RECT  142.596 2.795 168.894 2.861 ;
     RECT  5.04 2.795 6.894 12.325 ;
     RECT  7.632 2.795 27.63 12.325 ;
     RECT  28.368 2.861 32.742 13.099 ;
     RECT  82.476 2.861 87.03 13.099 ;
     RECT  88.02 2.861 89.097 13.099 ;
     RECT  28.368 13.099 33.426 13.531 ;
     RECT  28.368 13.531 33.57 13.661 ;
     RECT  34.815 2.861 35.097 13.675 ;
     RECT  36.36 2.861 37.854 13.675 ;
     RECT  38.88 2.861 51.426 13.675 ;
     RECT  90.9 2.861 91.797 13.675 ;
     RECT  94.215 2.861 95.202 13.675 ;
     RECT  96.192 2.861 124.614 13.675 ;
     RECT  125.352 2.861 137.754 13.675 ;
     RECT  34.524 13.675 35.097 13.723 ;
     RECT  89.82 13.675 93.15 13.865 ;
     RECT  36.324 13.675 37.854 13.981 ;
     RECT  94.215 13.675 124.614 13.981 ;
     RECT  125.352 13.675 138.762 13.981 ;
     RECT  139.572 2.861 141.678 13.981 ;
     RECT  90 13.865 93.15 14.071 ;
     RECT  90 14.071 93.294 14.237 ;
     RECT  5.04 12.325 27.63 14.251 ;
     RECT  28.368 13.661 32.994 14.251 ;
     RECT  33.984 13.723 35.097 14.251 ;
     RECT  38.844 13.675 51.426 14.251 ;
     RECT  94.104 13.981 124.614 14.251 ;
     RECT  125.352 13.981 141.678 14.251 ;
     RECT  142.596 2.861 143.73 14.251 ;
     RECT  145.116 2.861 151.83 14.251 ;
     RECT  152.568 2.861 168.894 14.251 ;
     RECT  82.476 13.099 89.097 14.395 ;
     RECT  38.808 14.251 51.426 14.405 ;
     RECT  93.564 14.251 124.614 14.405 ;
     RECT  145.116 14.251 168.894 14.405 ;
     RECT  5.04 14.251 32.994 14.521 ;
     RECT  33.984 14.251 35.514 14.521 ;
     RECT  36.324 13.981 37.89 14.521 ;
     RECT  52.164 2.795 81.738 14.521 ;
     RECT  82.476 14.395 89.154 14.521 ;
     RECT  4.176 2.489 4.194 14.675 ;
     RECT  5.004 14.521 32.994 14.675 ;
     RECT  11.592 14.675 32.994 14.747 ;
     RECT  11.736 14.747 32.994 14.779 ;
     RECT  52.164 14.521 89.154 14.779 ;
     RECT  125.352 14.251 144.054 14.779 ;
     RECT  5.004 14.675 5.397 14.791 ;
     RECT  33.984 14.521 37.89 14.791 ;
     RECT  33.984 14.791 38.106 14.813 ;
     RECT  93.708 14.405 124.614 14.813 ;
     RECT  11.736 14.779 33.102 14.819 ;
     RECT  33.984 14.813 35.298 14.819 ;
     RECT  52.164 14.779 89.37 14.819 ;
     RECT  90.252 14.237 92.826 14.819 ;
     RECT  94.032 14.813 124.614 14.819 ;
     RECT  125.352 14.779 144.234 14.819 ;
     RECT  142.596 14.819 144.234 14.827 ;
     RECT  145.116 14.405 147.258 14.827 ;
     RECT  33.984 14.819 34.002 14.875 ;
     RECT  33.768 14.875 34.002 14.945 ;
     RECT  34.776 14.819 35.262 14.945 ;
     RECT  90.252 14.819 91.797 14.945 ;
     RECT  94.032 14.819 95.202 14.945 ;
     RECT  148.104 14.405 168.858 14.945 ;
     RECT  92.7 14.819 92.826 15.061 ;
     RECT  138.528 14.819 141.678 15.089 ;
     RECT  92.7 15.061 92.934 15.215 ;
     RECT  171 15.115 171.018 15.251 ;
     RECT  92.844 15.215 92.934 15.359 ;
     RECT  33.984 14.945 34.002 15.389 ;
     RECT  34.815 14.945 35.262 15.389 ;
     RECT  88.02 14.819 89.37 15.389 ;
     RECT  90.468 14.945 91.797 15.389 ;
     RECT  92.916 15.359 92.934 15.389 ;
     RECT  139.068 15.089 141.678 15.389 ;
     RECT  142.596 14.827 147.258 15.389 ;
     RECT  94.104 14.945 95.202 16.013 ;
     RECT  90.9 15.389 91.797 20.191 ;
     RECT  2.415 2.413 2.697 20.425 ;
     RECT  4.284 14.791 5.397 20.461 ;
     RECT  2.415 20.425 2.862 20.539 ;
     RECT  2.304 20.539 2.862 20.579 ;
     RECT  2.304 20.579 2.697 20.615 ;
     RECT  4.14 20.461 5.397 20.615 ;
     RECT  96.192 14.819 124.614 22.819 ;
     RECT  125.352 14.819 137.754 22.819 ;
     RECT  146.592 15.389 147.258 22.819 ;
     RECT  38.88 14.405 51.426 24.331 ;
     RECT  52.164 14.819 87.03 24.331 ;
     RECT  11.736 14.819 32.958 24.523 ;
     RECT  34.815 15.389 35.097 24.523 ;
     RECT  36.36 14.813 38.106 24.523 ;
     RECT  38.88 24.331 87.03 24.523 ;
     RECT  88.02 15.389 89.097 24.523 ;
     RECT  90.9 20.191 92.286 24.523 ;
     RECT  94.215 16.013 95.202 24.523 ;
     RECT  96.192 22.819 137.754 24.523 ;
     RECT  36.36 24.523 87.03 24.715 ;
     RECT  87.768 24.523 92.538 24.715 ;
     RECT  11.736 24.523 33.642 24.781 ;
     RECT  34.488 24.523 35.097 24.781 ;
     RECT  94.215 24.523 137.754 24.781 ;
     RECT  138.636 24.523 138.654 24.781 ;
     RECT  139.572 15.389 141.678 24.781 ;
     RECT  142.596 15.389 143.097 24.781 ;
     RECT  143.928 15.389 143.946 24.781 ;
     RECT  11.736 24.781 35.586 24.871 ;
     RECT  36.36 24.715 92.79 24.871 ;
     RECT  148.14 14.945 168.858 24.941 ;
     RECT  143.928 24.781 144.378 25.015 ;
     RECT  145.116 15.389 145.797 25.015 ;
     RECT  11.736 24.871 92.79 25.051 ;
     RECT  94.215 24.781 138.654 25.051 ;
     RECT  139.572 24.781 143.097 25.051 ;
     RECT  146.52 22.819 147.258 25.099 ;
     RECT  148.14 24.941 152.01 25.099 ;
     RECT  143.928 25.015 145.797 25.147 ;
     RECT  146.52 25.099 152.01 25.147 ;
     RECT  94.215 25.051 143.097 25.285 ;
     RECT  143.928 25.147 152.01 25.285 ;
     RECT  11.736 25.051 93.438 25.321 ;
     RECT  94.215 25.285 152.01 25.321 ;
     RECT  152.748 24.941 168.858 25.411 ;
     RECT  6.12 14.675 10.797 25.591 ;
     RECT  11.736 25.321 152.01 25.591 ;
     RECT  152.748 25.411 168.894 25.591 ;
     RECT  169.815 2.413 170.097 25.591 ;
     RECT  4.284 20.615 5.397 25.681 ;
     RECT  6.12 25.591 152.01 25.681 ;
     RECT  152.748 25.591 170.097 25.681 ;
     RECT  4.284 25.681 170.097 26.293 ;
     RECT  3.852 26.293 170.097 26.591 ;
     RECT  2.415 20.615 2.697 27.827 ;
     RECT  4.464 26.591 170.097 27.827 ;
     RECT  4.464 27.827 169.905 27.869 ;
     RECT  4.464 27.869 168.75 27.917 ;
     RECT  169.524 27.869 169.905 27.941 ;
     RECT  4.464 27.917 168.714 27.965 ;
     RECT  169.596 27.941 169.905 27.965 ;
     RECT  23.652 27.965 108.522 28.013 ;
     RECT  122.796 27.965 135.954 28.013 ;
     RECT  139.536 27.965 168.714 28.013 ;
     RECT  4.464 27.965 22.914 28.049 ;
     RECT  139.536 28.013 168.606 28.061 ;
     RECT  2.415 27.827 2.505 28.097 ;
     RECT  23.652 28.013 108.45 28.097 ;
     RECT  122.796 28.013 132.354 28.097 ;
     RECT  139.536 28.061 168.066 28.097 ;
     RECT  169.815 27.965 169.905 28.097 ;
     RECT  29.988 28.097 104.634 28.175 ;
     RECT  76.068 28.175 104.634 28.205 ;
     RECT  76.068 28.205 83.394 28.253 ;
     RECT  4.464 28.049 18.882 29.029 ;
     RECT  19.692 28.049 22.914 29.029 ;
     RECT  23.652 28.097 29.25 29.029 ;
     RECT  29.988 28.175 75.33 29.029 ;
     RECT  76.068 28.253 80.442 29.029 ;
     RECT  81.288 28.253 83.394 29.029 ;
     RECT  84.132 28.205 104.634 29.029 ;
     RECT  105.372 28.097 107.01 29.029 ;
     RECT  108.072 28.097 108.45 29.029 ;
     RECT  109.296 27.965 121.986 29.029 ;
     RECT  122.796 28.097 123.282 29.029 ;
     RECT  124.056 28.097 132.354 29.029 ;
     RECT  133.2 28.013 135.954 29.029 ;
     RECT  136.764 27.965 138.69 29.029 ;
     RECT  139.536 28.097 161.046 29.029 ;
     RECT  161.856 28.097 164.394 29.029 ;
     RECT  165.168 28.097 168.066 29.029 ;
     RECT  4.464 29.029 107.01 29.659 ;
     RECT  108.072 29.029 168.066 29.659 ;
     RECT  4.464 29.659 168.066 30.108 ;
     RECT  54.036 30.108 54.126 30.173 ;
     RECT  72.468 30.108 72.558 30.173 ;
     RECT  82.26 30.108 82.35 30.173 ;
     RECT  106.452 30.108 106.542 30.173 ;
     RECT  165.78 30.108 165.87 30.173 ;
    LAYER M4 ;
     RECT  0.229 24.72 2.408 24.744 ;
     RECT  2.408 2.148 2.512 28.092 ;
     RECT  2.512 2.418 2.704 27.822 ;
     RECT  4.633 26.112 4.813 26.136 ;
     RECT  4.741 1.728 5.108 1.752 ;
     RECT  2.704 24.72 5.108 24.744 ;
     RECT  4.813 26.112 5.108 26.616 ;
     RECT  4.741 27.936 5.108 27.96 ;
     RECT  5.108 1.728 5.317 28.092 ;
     RECT  5.317 1.728 5.404 28.536 ;
     RECT  5.404 28.512 5.465 28.536 ;
     RECT  5.404 26.112 5.897 26.232 ;
     RECT  5.569 29.664 5.939 29.688 ;
     RECT  5.897 26.208 6.865 26.232 ;
     RECT  5.404 24.72 7.429 24.744 ;
     RECT  6.865 25.872 7.429 26.328 ;
     RECT  7.388 23.328 7.477 23.352 ;
     RECT  7.429 24.72 7.477 26.328 ;
     RECT  6.469 27.36 7.477 27.384 ;
     RECT  5.404 1.728 7.808 1.752 ;
     RECT  7.477 3.6 7.808 3.624 ;
     RECT  7.477 23.136 7.808 23.352 ;
     RECT  7.477 24.72 7.808 27.384 ;
     RECT  7.808 1.728 7.912 28.092 ;
     RECT  7.912 1.728 8.104 27.96 ;
     RECT  7.621 29.664 8.284 29.688 ;
     RECT  8.773 0.192 8.993 0.216 ;
     RECT  8.104 3.6 9.245 3.624 ;
     RECT  8.104 24.72 9.385 26.664 ;
     RECT  8.104 27.936 9.385 27.96 ;
     RECT  9.385 24.72 9.395 27.96 ;
     RECT  8.104 1.728 10.508 1.752 ;
     RECT  9.395 24.72 10.508 27.336 ;
     RECT  10.508 1.728 10.612 28.092 ;
     RECT  10.612 1.728 10.804 27.822 ;
     RECT  10.804 26.208 10.937 26.616 ;
     RECT  9.313 29.664 11.123 29.688 ;
     RECT  11.653 27.936 11.945 27.96 ;
     RECT  10.937 26.208 12.017 26.232 ;
     RECT  12.229 29.664 12.449 29.688 ;
     RECT  12.764 29.088 12.851 29.112 ;
     RECT  10.804 24.72 13.093 25.176 ;
     RECT  10.804 1.728 13.208 1.752 ;
     RECT  13.093 24.72 13.208 26.088 ;
     RECT  13.093 27.648 13.208 27.672 ;
     RECT  13.208 1.728 13.381 28.092 ;
     RECT  13.381 1.728 13.504 28.2 ;
     RECT  13.504 24.72 13.565 26.328 ;
     RECT  13.504 28.176 13.619 28.2 ;
     RECT  13.957 29.664 14.105 29.688 ;
     RECT  14.525 28.464 15.221 28.488 ;
     RECT  15.469 29.088 15.731 29.112 ;
     RECT  13.504 1.728 15.908 1.752 ;
     RECT  13.565 24.72 15.908 26.232 ;
     RECT  15.908 1.728 16.204 28.092 ;
     RECT  16.225 28.512 16.309 28.824 ;
     RECT  16.204 24.72 16.697 26.136 ;
     RECT  16.309 28.512 17.021 28.536 ;
     RECT  17.413 27.936 17.597 27.96 ;
     RECT  16.697 24.72 18.469 25.272 ;
     RECT  17.989 28.464 18.469 28.488 ;
     RECT  16.204 1.728 18.608 1.752 ;
     RECT  18.469 24.72 18.608 25.848 ;
     RECT  18.469 28.464 18.608 29.064 ;
     RECT  18.608 1.728 18.611 29.064 ;
     RECT  18.611 1.728 18.712 28.092 ;
     RECT  18.712 1.728 18.904 27.96 ;
     RECT  18.904 27.936 19.649 27.96 ;
     RECT  19.717 28.464 19.901 28.488 ;
     RECT  18.904 24.72 20.189 26.232 ;
     RECT  20.293 29.04 20.441 29.064 ;
     RECT  20.189 24.72 21.157 25.272 ;
     RECT  20.869 27.936 21.157 27.96 ;
     RECT  18.904 1.728 21.308 1.752 ;
     RECT  21.157 24.72 21.308 26.04 ;
     RECT  21.157 27.936 21.308 28.248 ;
     RECT  21.308 1.728 21.491 28.248 ;
     RECT  21.491 1.728 21.604 27.822 ;
     RECT  21.604 24.72 21.971 25.944 ;
     RECT  21.913 29.664 22.067 29.688 ;
     RECT  21.971 24.72 23.461 25.272 ;
     RECT  22.597 27.936 23.893 27.96 ;
     RECT  21.604 1.728 24.008 1.752 ;
     RECT  23.461 24.72 24.008 26.328 ;
     RECT  23.893 27.408 24.008 27.96 ;
     RECT  24.008 1.728 24.304 28.092 ;
     RECT  24.304 24.72 24.325 28.092 ;
     RECT  24.325 24.72 24.473 28.488 ;
     RECT  24.473 24.72 24.689 26.76 ;
     RECT  24.304 1.728 25.667 1.752 ;
     RECT  26.197 0.192 26.281 0.216 ;
     RECT  24.473 27.936 26.629 27.96 ;
     RECT  24.689 24.72 26.708 25.464 ;
     RECT  24.689 26.736 26.708 26.76 ;
     RECT  26.629 27.936 26.708 28.248 ;
     RECT  26.708 2.148 26.716 28.248 ;
     RECT  26.716 2.148 26.773 28.092 ;
     RECT  26.773 1.728 26.812 28.092 ;
     RECT  26.812 1.728 26.885 27.96 ;
     RECT  26.885 2.256 27.004 27.96 ;
     RECT  27.004 2.256 27.925 2.28 ;
     RECT  27.925 1.728 27.929 2.28 ;
     RECT  27.004 24.72 28.285 26.136 ;
     RECT  27.004 14.832 28.361 14.856 ;
     RECT  27.277 0.192 28.547 0.216 ;
     RECT  28.285 24.72 29.18 26.856 ;
     RECT  27.004 27.936 29.18 27.96 ;
     RECT  29.18 24.72 29.221 27.96 ;
     RECT  27.929 1.728 29.408 1.752 ;
     RECT  28.421 15.36 29.408 15.384 ;
     RECT  29.221 24.72 29.408 28.248 ;
     RECT  29.408 1.728 29.704 28.248 ;
     RECT  29.704 27.072 30.085 28.248 ;
     RECT  30.085 27.072 30.197 28.488 ;
     RECT  30.197 27.072 30.233 27.96 ;
     RECT  29.704 2.832 30.665 2.856 ;
     RECT  29.704 24.72 30.841 25.464 ;
     RECT  29.704 1.728 30.925 1.752 ;
     RECT  29.704 14.832 30.949 14.856 ;
     RECT  30.949 2.256 31.033 2.28 ;
     RECT  30.949 14.256 31.033 15.384 ;
     RECT  31.417 0.576 31.501 0.6 ;
     RECT  30.233 27.936 31.805 27.96 ;
     RECT  31.805 27.936 31.889 28.488 ;
     RECT  30.841 24.72 31.957 26.232 ;
     RECT  31.885 0.192 32.051 0.216 ;
     RECT  31.033 14.256 32.108 14.808 ;
     RECT  31.957 24.72 32.108 26.568 ;
     RECT  31.889 27.936 32.108 28.2 ;
     RECT  32.108 2.148 32.404 28.2 ;
     RECT  32.404 27.936 32.435 28.2 ;
     RECT  32.404 2.148 32.569 2.856 ;
     RECT  32.404 24.528 33.041 26.856 ;
     RECT  32.404 13.104 33.437 14.904 ;
     RECT  33.437 13.632 33.625 14.904 ;
     RECT  32.569 1.728 33.797 2.856 ;
     RECT  33.797 2.256 33.805 2.856 ;
     RECT  33.625 13.68 33.973 14.904 ;
     RECT  34.153 0.192 34.355 0.216 ;
     RECT  33.041 24.528 34.585 26.76 ;
     RECT  34.765 1.728 34.808 1.752 ;
     RECT  33.805 2.832 34.808 2.856 ;
     RECT  33.973 13.68 34.808 15.384 ;
     RECT  34.585 24.528 34.808 26.808 ;
     RECT  32.435 27.936 34.808 27.96 ;
     RECT  34.808 1.728 34.912 28.092 ;
     RECT  34.912 1.728 35.104 27.96 ;
     RECT  35.104 24.72 35.201 26.568 ;
     RECT  35.104 13.68 35.273 15.384 ;
     RECT  35.104 1.728 35.461 2.856 ;
     RECT  35.461 1.728 35.525 1.752 ;
     RECT  35.461 2.832 35.893 2.856 ;
     RECT  35.881 0.192 36.083 0.216 ;
     RECT  35.201 24.72 36.205 26.328 ;
     RECT  36.205 24.72 36.421 26.76 ;
     RECT  35.104 27.936 36.508 27.96 ;
     RECT  36.613 1.728 36.673 1.752 ;
     RECT  36.673 1.728 36.997 2.28 ;
     RECT  36.997 1.728 37.508 2.856 ;
     RECT  35.273 13.68 37.508 14.808 ;
     RECT  36.421 24.528 37.508 26.76 ;
     RECT  37.393 28.224 37.508 28.248 ;
     RECT  37.508 1.728 37.619 28.248 ;
     RECT  37.619 1.728 37.804 27.96 ;
     RECT  37.804 1.728 37.901 2.856 ;
     RECT  37.804 26.64 38.189 26.808 ;
     RECT  38.257 0.576 38.435 0.6 ;
     RECT  37.901 2.256 38.665 2.856 ;
     RECT  38.581 29.664 38.771 29.688 ;
     RECT  37.804 24.528 38.797 25.272 ;
     RECT  37.804 13.68 38.905 14.28 ;
     RECT  38.905 13.68 38.989 14.808 ;
     RECT  38.189 26.64 39.697 26.664 ;
     RECT  38.797 24.528 39.769 25.464 ;
     RECT  39.697 26.64 39.769 26.76 ;
     RECT  38.965 1.728 40.208 1.752 ;
     RECT  38.665 2.832 40.208 2.856 ;
     RECT  38.989 13.68 40.208 14.232 ;
     RECT  39.769 24.528 40.208 26.76 ;
     RECT  37.804 27.936 40.208 27.96 ;
     RECT  40.208 1.728 40.453 28.092 ;
     RECT  40.453 1.728 40.504 28.2 ;
     RECT  40.504 26.256 40.853 26.664 ;
     RECT  40.853 26.544 41.033 26.664 ;
     RECT  40.504 28.176 41.033 28.2 ;
     RECT  41.029 29.664 41.605 29.688 ;
     RECT  41.605 29.088 41.753 29.688 ;
     RECT  40.504 1.728 42.613 1.752 ;
     RECT  41.753 29.664 42.617 29.688 ;
     RECT  41.033 26.544 42.685 26.568 ;
     RECT  42.685 26.544 42.749 26.904 ;
     RECT  42.749 26.544 42.757 27.144 ;
     RECT  42.613 1.728 42.908 2.28 ;
     RECT  40.504 24.72 42.908 25.272 ;
     RECT  42.757 26.256 42.908 27.144 ;
     RECT  42.865 0.576 43.043 0.6 ;
     RECT  42.908 1.728 43.204 28.092 ;
     RECT  43.204 24.72 43.298 26.28 ;
     RECT  43.333 28.464 43.589 28.488 ;
     RECT  43.204 1.728 43.625 1.752 ;
     RECT  43.909 28.8 44.057 28.824 ;
     RECT  43.765 0.192 44.243 0.216 ;
     RECT  44.485 29.04 44.777 29.064 ;
     RECT  45.061 29.088 45.353 29.112 ;
     RECT  43.298 24.72 45.457 26.232 ;
     RECT  44.773 1.728 45.608 1.752 ;
     RECT  44.917 2.784 45.608 2.808 ;
     RECT  45.457 24.72 45.608 26.664 ;
     RECT  45.608 1.728 45.712 28.092 ;
     RECT  45.712 1.728 45.904 27.96 ;
     RECT  45.637 29.664 46.001 29.688 ;
     RECT  45.904 2.784 46.019 2.808 ;
     RECT  45.904 24.72 46.019 27.96 ;
     RECT  46.019 24.72 46.045 26.76 ;
     RECT  46.045 26.304 46.06 26.76 ;
     RECT  46.06 26.64 46.469 26.76 ;
     RECT  46.019 27.936 46.789 27.96 ;
     RECT  46.469 26.736 47.045 26.76 ;
     RECT  45.904 1.728 47.153 1.752 ;
     RECT  46.789 27.936 47.189 28.536 ;
     RECT  47.257 0.192 47.699 0.216 ;
     RECT  47.941 29.664 48.089 29.688 ;
     RECT  48.221 1.728 48.308 1.752 ;
     RECT  46.045 24.72 48.308 25.272 ;
     RECT  47.833 26.64 48.308 26.664 ;
     RECT  47.189 27.936 48.308 27.96 ;
     RECT  48.308 1.728 48.517 28.092 ;
     RECT  48.517 1.728 48.604 28.2 ;
     RECT  48.604 24.72 48.737 28.2 ;
     RECT  48.737 24.72 48.851 27.48 ;
     RECT  48.851 24.72 48.953 27.096 ;
     RECT  48.953 24.72 49.709 26.664 ;
     RECT  49.093 28.512 50.141 28.536 ;
     RECT  49.709 26.64 50.281 26.664 ;
     RECT  50.281 26.64 50.461 26.808 ;
     RECT  50.461 26.64 50.749 26.904 ;
     RECT  50.245 27.936 50.749 28.092 ;
     RECT  48.604 1.728 51.008 1.752 ;
     RECT  49.709 24.72 51.008 25.272 ;
     RECT  50.749 26.64 51.008 28.092 ;
     RECT  51.008 1.728 51.112 28.092 ;
     RECT  51.112 1.728 51.304 27.96 ;
     RECT  51.304 24.48 51.869 25.272 ;
     RECT  51.304 27.936 52.229 27.96 ;
     RECT  52.549 28.512 52.697 28.536 ;
     RECT  51.869 24.48 53.413 25.08 ;
     RECT  51.304 1.728 53.708 1.752 ;
     RECT  53.413 24.48 53.708 25.272 ;
     RECT  51.304 26.64 53.708 26.808 ;
     RECT  53.708 1.728 53.812 28.092 ;
     RECT  53.812 1.728 54.004 27.96 ;
     RECT  54.004 26.64 54.101 26.856 ;
     RECT  53.125 29.664 54.101 29.688 ;
     RECT  54.101 26.64 54.605 26.664 ;
     RECT  54.004 1.728 54.749 2.232 ;
     RECT  54.004 27.936 55.217 27.96 ;
     RECT  54.004 24.624 56.293 25.272 ;
     RECT  54.749 1.728 56.408 1.752 ;
     RECT  56.293 24.624 56.408 25.32 ;
     RECT  55.573 26.736 56.408 26.76 ;
     RECT  56.408 1.728 56.512 28.092 ;
     RECT  55.429 29.664 56.581 29.688 ;
     RECT  56.512 1.728 56.704 27.822 ;
     RECT  56.581 29.04 56.819 29.688 ;
     RECT  56.819 29.664 57.305 29.688 ;
     RECT  56.704 24.624 57.635 26.76 ;
     RECT  57.635 26.736 58.309 26.76 ;
     RECT  58.309 26.736 58.741 26.856 ;
     RECT  56.704 1.728 58.817 1.752 ;
     RECT  57.635 24.624 59.108 25.272 ;
     RECT  58.741 26.64 59.108 26.856 ;
     RECT  57.733 27.936 59.108 27.96 ;
     RECT  59.065 0.24 59.315 0.264 ;
     RECT  59.108 2.148 59.404 28.092 ;
     RECT  59.404 27.936 59.461 28.092 ;
     RECT  59.461 27.936 59.548 28.2 ;
     RECT  59.548 27.936 59.581 28.104 ;
     RECT  59.404 24.624 59.897 26.664 ;
     RECT  59.897 24.72 59.933 26.664 ;
     RECT  59.845 1.728 60.005 1.752 ;
     RECT  60.181 0.192 60.467 0.216 ;
     RECT  59.933 26.64 60.721 26.664 ;
     RECT  59.581 27.936 60.833 27.96 ;
     RECT  61.189 28.224 61.337 28.536 ;
     RECT  60.997 1.728 61.808 1.752 ;
     RECT  59.933 24.72 61.808 25.272 ;
     RECT  60.721 26.64 61.808 26.808 ;
     RECT  61.337 28.224 61.808 28.248 ;
     RECT  61.808 1.728 62.104 28.248 ;
     RECT  62.104 1.728 62.201 1.752 ;
     RECT  62.104 27.936 62.333 28.248 ;
     RECT  62.333 27.936 62.417 28.488 ;
     RECT  62.104 26.64 63.101 26.664 ;
     RECT  62.104 24.72 63.241 25.272 ;
     RECT  62.664 0.192 63.277 0.216 ;
     RECT  62.417 27.936 63.281 27.96 ;
     RECT  63.277 0.192 63.361 0.6 ;
     RECT  63.485 28.464 63.569 28.488 ;
     RECT  63.361 0.192 63.923 0.216 ;
     RECT  64.028 29.664 64.115 29.688 ;
     RECT  63.241 24.72 64.141 25.848 ;
     RECT  64.141 24.72 64.357 26.664 ;
     RECT  63.781 2.256 64.501 2.28 ;
     RECT  64.501 1.728 64.508 2.28 ;
     RECT  64.357 24.624 64.508 26.664 ;
     RECT  64.508 1.728 64.645 28.092 ;
     RECT  64.645 1.728 64.804 28.248 ;
     RECT  64.804 27.936 64.931 28.248 ;
     RECT  64.804 24.624 65.189 26.664 ;
     RECT  65.189 24.624 65.441 26.232 ;
     RECT  64.931 27.936 65.981 27.96 ;
     RECT  64.804 1.728 66.305 1.752 ;
     RECT  66.373 29.664 66.46 29.688 ;
     RECT  66.733 0.576 66.851 0.6 ;
     RECT  65.441 24.72 66.949 26.232 ;
     RECT  66.949 24.72 67.208 26.328 ;
     RECT  67.208 2.148 67.345 28.092 ;
     RECT  67.345 1.728 67.504 28.092 ;
     RECT  67.504 1.728 67.667 2.856 ;
     RECT  67.525 29.664 67.673 29.688 ;
     RECT  67.667 1.728 68.033 2.712 ;
     RECT  68.093 28.464 68.177 28.488 ;
     RECT  67.504 24.72 68.465 26.664 ;
     RECT  68.033 2.688 68.675 2.712 ;
     RECT  68.465 24.72 68.689 26.232 ;
     RECT  68.636 29.664 68.723 29.688 ;
     RECT  68.533 0.576 69.731 0.6 ;
     RECT  69.788 29.664 69.875 29.688 ;
     RECT  69.109 1.728 69.908 1.752 ;
     RECT  68.689 24.72 69.908 25.272 ;
     RECT  69.541 26.64 69.908 26.664 ;
     RECT  69.253 27.936 69.908 27.96 ;
     RECT  69.908 1.728 70.012 28.092 ;
     RECT  70.012 1.728 70.204 27.96 ;
     RECT  70.981 29.664 71.201 29.688 ;
     RECT  70.204 24.72 71.593 25.272 ;
     RECT  70.204 27.936 71.603 27.96 ;
     RECT  72.092 29.088 72.179 29.112 ;
     RECT  71.593 24.624 72.385 25.272 ;
     RECT  70.204 26.64 72.385 26.664 ;
     RECT  70.204 1.728 72.608 1.752 ;
     RECT  72.385 24.624 72.608 26.664 ;
     RECT  72.608 1.728 72.659 28.092 ;
     RECT  72.659 2.148 72.712 28.092 ;
     RECT  72.712 2.418 72.904 27.822 ;
     RECT  72.904 26.496 73.037 26.664 ;
     RECT  72.997 0.576 73.235 0.6 ;
     RECT  73.82 27.936 73.907 27.96 ;
     RECT  72.385 29.664 74.585 29.688 ;
     RECT  73.037 26.496 74.677 26.52 ;
     RECT  72.904 24.624 75.116 25.272 ;
     RECT  75.116 24.624 75.157 25.368 ;
     RECT  74.677 26.496 75.157 26.616 ;
     RECT  73.745 1.728 75.308 1.752 ;
     RECT  75.157 24.624 75.308 26.616 ;
     RECT  74.977 28.464 75.308 28.488 ;
     RECT  75.308 1.728 75.412 28.488 ;
     RECT  75.412 1.728 75.539 27.822 ;
     RECT  75.539 2.418 75.604 27.822 ;
     RECT  75.604 24.624 75.665 27.336 ;
     RECT  75.589 29.04 75.731 29.064 ;
     RECT  75.665 27.072 75.737 27.336 ;
     RECT  75.665 24.624 75.917 26.04 ;
     RECT  75.769 0.192 76.115 0.216 ;
     RECT  75.737 27.312 76.313 27.336 ;
     RECT  75.917 24.72 77.16 26.04 ;
     RECT  76.165 29.664 77.465 29.688 ;
     RECT  76.645 1.728 78.008 1.752 ;
     RECT  77.16 24.72 78.008 26.232 ;
     RECT  77.821 27.936 78.008 27.96 ;
     RECT  78.008 1.728 78.304 28.092 ;
     RECT  79.045 28.464 79.805 28.488 ;
     RECT  78.304 24.72 79.916 26.52 ;
     RECT  80.156 29.664 80.243 29.688 ;
     RECT  79.916 24.72 80.413 26.808 ;
     RECT  78.304 1.728 80.708 1.752 ;
     RECT  80.413 24.72 80.708 27.096 ;
     RECT  80.629 28.224 80.708 28.248 ;
     RECT  80.708 1.728 81.004 28.248 ;
     RECT  81.004 24.72 81.137 26.616 ;
     RECT  81.004 27.936 81.349 28.248 ;
     RECT  81.349 27.936 81.461 28.488 ;
     RECT  81.137 24.72 83.257 26.52 ;
     RECT  81.461 27.936 83.257 27.96 ;
     RECT  81.004 1.728 83.408 1.752 ;
     RECT  83.257 24.72 83.408 27.96 ;
     RECT  83.408 1.728 83.653 28.092 ;
     RECT  83.653 1.728 83.704 28.2 ;
     RECT  83.704 24.72 83.801 26.664 ;
     RECT  83.704 28.176 84.053 28.2 ;
     RECT  84.229 29.664 84.341 29.688 ;
     RECT  83.801 26.64 84.805 26.664 ;
     RECT  84.805 26.352 84.845 26.664 ;
     RECT  83.801 24.72 85.957 25.08 ;
     RECT  84.845 26.352 85.957 26.568 ;
     RECT  83.704 1.728 86.108 1.752 ;
     RECT  85.813 2.832 86.108 2.856 ;
     RECT  85.813 14.64 86.108 14.664 ;
     RECT  85.957 24.72 86.108 26.568 ;
     RECT  84.805 27.936 86.108 27.96 ;
     RECT  86.108 1.728 86.404 28.092 ;
     RECT  86.404 13.68 86.545 14.808 ;
     RECT  86.404 24.72 86.627 26.76 ;
     RECT  86.404 27.744 86.645 28.092 ;
     RECT  86.533 29.664 86.645 29.688 ;
     RECT  87.109 28.464 87.193 28.488 ;
     RECT  86.404 1.728 87.433 1.752 ;
     RECT  86.404 2.832 87.433 2.856 ;
     RECT  86.545 13.68 87.445 14.28 ;
     RECT  87.445 13.104 87.473 14.28 ;
     RECT  87.433 1.728 87.517 2.856 ;
     RECT  87.473 13.104 87.653 13.704 ;
     RECT  86.627 24.72 87.713 25.128 ;
     RECT  86.627 26.208 87.731 26.76 ;
     RECT  87.649 14.784 87.733 14.808 ;
     RECT  87.713 24.528 88.189 25.128 ;
     RECT  87.613 27.936 88.585 27.96 ;
     RECT  87.653 13.632 88.597 13.704 ;
     RECT  87.517 1.728 88.685 1.752 ;
     RECT  87.517 2.832 88.685 2.856 ;
     RECT  88.597 13.632 88.693 14.424 ;
     RECT  88.685 1.728 88.808 2.856 ;
     RECT  88.693 13.104 88.808 14.424 ;
     RECT  88.189 24.528 88.808 25.272 ;
     RECT  87.731 26.64 88.808 26.76 ;
     RECT  88.585 27.936 88.808 28.248 ;
     RECT  88.808 1.728 88.883 28.248 ;
     RECT  88.883 1.728 88.912 28.092 ;
     RECT  88.912 1.728 89.104 27.96 ;
     RECT  89.104 24.528 89.363 27.96 ;
     RECT  89.104 13.68 89.381 15.384 ;
     RECT  89.363 26.352 89.417 27.96 ;
     RECT  89.104 1.728 90.349 1.752 ;
     RECT  89.104 2.832 90.349 2.856 ;
     RECT  89.417 26.352 90.421 26.664 ;
     RECT  89.381 13.68 90.457 14.856 ;
     RECT  89.363 24.528 90.467 25.272 ;
     RECT  90.467 24.72 90.524 25.272 ;
     RECT  90.421 26.256 90.524 26.76 ;
     RECT  90.457 13.68 90.541 15.384 ;
     RECT  90.524 24.72 91.045 26.76 ;
     RECT  89.417 27.936 91.285 27.96 ;
     RECT  90.349 1.728 91.508 2.856 ;
     RECT  90.541 13.68 91.508 14.808 ;
     RECT  91.045 24.72 91.508 26.808 ;
     RECT  91.285 27.936 91.508 28.2 ;
     RECT  91.508 1.728 91.763 28.2 ;
     RECT  91.763 1.728 91.804 27.96 ;
     RECT  91.804 1.728 91.865 2.856 ;
     RECT  91.865 2.256 92.377 2.856 ;
     RECT  92.077 0.192 92.387 0.216 ;
     RECT  91.804 24.528 92.627 26.808 ;
     RECT  92.627 24.72 92.765 26.808 ;
     RECT  91.804 13.68 92.789 14.904 ;
     RECT  92.789 13.68 92.905 15.336 ;
     RECT  92.905 13.68 92.989 15.384 ;
     RECT  92.897 1.728 93.481 1.752 ;
     RECT  92.377 2.832 93.481 2.856 ;
     RECT  92.989 13.68 93.973 14.856 ;
     RECT  93.973 13.68 94.093 15.24 ;
     RECT  93.481 1.728 94.133 2.856 ;
     RECT  94.133 2.148 94.208 2.856 ;
     RECT  94.093 13.68 94.208 16.008 ;
     RECT  92.765 24.72 94.208 26.664 ;
     RECT  91.804 27.936 94.208 27.96 ;
     RECT  94.208 2.148 94.312 28.092 ;
     RECT  94.312 2.148 94.504 27.822 ;
     RECT  94.504 15.984 94.673 16.008 ;
     RECT  94.504 19.872 94.673 20.088 ;
     RECT  94.504 23.904 94.673 25.272 ;
     RECT  94.504 18.768 94.684 18.888 ;
     RECT  94.504 22.704 94.684 22.824 ;
     RECT  94.561 0.192 94.691 0.216 ;
     RECT  94.597 30 94.961 30.024 ;
     RECT  94.673 24.528 95.468 25.272 ;
     RECT  94.504 26.64 95.468 26.664 ;
     RECT  94.504 13.68 95.573 14.232 ;
     RECT  95.468 24.528 95.617 26.664 ;
     RECT  95.573 14.016 95.653 14.232 ;
     RECT  95.617 24.72 95.725 26.664 ;
     RECT  95.653 14.016 95.789 14.808 ;
     RECT  95.789 14.784 95.861 14.808 ;
     RECT  95.221 1.728 95.897 1.752 ;
     RECT  95.173 29.664 96.185 29.688 ;
     RECT  95.725 26.208 96.325 26.664 ;
     RECT  96.361 0.576 96.445 0.6 ;
     RECT  94.504 2.832 96.677 2.856 ;
     RECT  95.725 24.72 96.685 25.176 ;
     RECT  96.709 13.104 96.757 13.128 ;
     RECT  96.685 24.672 96.757 25.176 ;
     RECT  96.677 2.256 96.908 2.856 ;
     RECT  96.757 13.104 96.908 13.656 ;
     RECT  96.277 14.832 96.908 15.384 ;
     RECT  96.757 24.528 96.908 25.176 ;
     RECT  96.325 26.208 96.908 26.808 ;
     RECT  96.901 29.04 96.908 29.064 ;
     RECT  96.908 2.148 96.949 29.064 ;
     RECT  96.949 1.728 97.012 29.064 ;
     RECT  97.012 1.728 97.204 27.822 ;
     RECT  97.204 24.528 97.301 26.808 ;
     RECT  97.301 24.528 97.379 26.76 ;
     RECT  97.012 29.04 97.477 29.064 ;
     RECT  97.379 24.528 97.481 26.664 ;
     RECT  97.204 13.68 97.553 15.096 ;
     RECT  97.333 0.192 97.571 0.216 ;
     RECT  97.477 29.04 97.661 29.688 ;
     RECT  97.204 2.832 97.993 2.856 ;
     RECT  97.553 13.68 98.021 14.232 ;
     RECT  97.481 24.528 98.051 25.272 ;
     RECT  98.021 14.112 98.093 14.232 ;
     RECT  98.093 14.208 98.129 14.232 ;
     RECT  97.661 29.04 98.273 29.064 ;
     RECT  98.051 24.72 98.449 25.272 ;
     RECT  97.481 26.64 98.449 26.664 ;
     RECT  98.449 24.72 98.489 26.664 ;
     RECT  98.489 24.72 99.061 26.232 ;
     RECT  97.204 1.728 99.608 1.752 ;
     RECT  99.061 24.48 99.608 26.232 ;
     RECT  99.205 27.936 99.608 27.96 ;
     RECT  99.608 1.728 99.712 28.092 ;
     RECT  99.712 1.728 99.904 27.96 ;
     RECT  99.904 24.48 100.019 25.272 ;
     RECT  99.904 27.936 100.901 27.96 ;
     RECT  100.019 24.48 100.973 25.176 ;
     RECT  98.629 29.664 101.693 29.688 ;
     RECT  100.973 24.72 101.717 25.176 ;
     RECT  99.904 26.64 101.717 26.664 ;
     RECT  102.085 29.088 102.197 29.112 ;
     RECT  99.904 1.728 102.308 1.752 ;
     RECT  101.717 24.72 102.308 26.664 ;
     RECT  102.308 1.728 102.412 28.092 ;
     RECT  102.412 1.728 102.604 27.822 ;
     RECT  102.604 24.72 102.665 25.176 ;
     RECT  102.604 26.448 103.241 26.664 ;
     RECT  102.661 29.04 103.321 29.064 ;
     RECT  102.665 24.96 104.101 25.176 ;
     RECT  103.241 26.448 104.101 26.472 ;
     RECT  102.604 1.728 104.285 1.752 ;
     RECT  104.101 24.96 104.317 26.472 ;
     RECT  104.317 24.96 104.389 26.664 ;
     RECT  103.813 27.936 104.389 27.96 ;
     RECT  104.425 0.576 104.531 0.6 ;
     RECT  104.389 24.96 104.869 27.96 ;
     RECT  104.869 24.96 105.008 28.248 ;
     RECT  105.008 2.148 105.112 28.248 ;
     RECT  105.112 2.418 105.304 28.248 ;
     RECT  105.304 26.64 105.437 26.664 ;
     RECT  105.469 28.512 105.587 28.536 ;
     RECT  104.821 0.192 105.731 0.216 ;
     RECT  106.117 28.8 106.265 28.824 ;
     RECT  105.304 24.96 106.693 25.464 ;
     RECT  106.693 24.96 107.305 26.04 ;
     RECT  107.305 24.96 107.701 26.568 ;
     RECT  106.261 1.728 107.708 1.752 ;
     RECT  107.701 24.96 107.708 26.808 ;
     RECT  107.269 27.936 107.708 27.96 ;
     RECT  107.708 1.728 107.812 28.092 ;
     RECT  107.557 29.664 107.845 29.688 ;
     RECT  107.812 1.728 108.004 27.822 ;
     RECT  107.845 29.664 108.101 29.736 ;
     RECT  108.004 1.728 108.145 2.28 ;
     RECT  108.101 29.664 108.179 29.688 ;
     RECT  108.004 24.96 108.181 27.384 ;
     RECT  108.181 26.304 108.713 27.384 ;
     RECT  108.713 26.304 108.821 26.808 ;
     RECT  108.821 26.784 109.361 26.808 ;
     RECT  108.145 1.728 110.245 1.752 ;
     RECT  108.181 24.96 110.245 25.272 ;
     RECT  110.185 26.64 110.245 26.664 ;
     RECT  110.245 1.728 110.408 2.28 ;
     RECT  110.245 24.96 110.408 26.664 ;
     RECT  108.997 27.936 110.408 27.96 ;
     RECT  110.408 1.728 110.704 28.092 ;
     RECT  110.725 28.176 111.301 28.2 ;
     RECT  111.301 28.176 111.701 28.536 ;
     RECT  110.704 24.96 111.917 26.664 ;
     RECT  111.917 26.64 112.085 26.664 ;
     RECT  110.704 1.728 112.337 1.752 ;
     RECT  112.453 29.664 112.781 29.688 ;
     RECT  111.877 27.936 112.988 27.96 ;
     RECT  112.988 27.936 113.075 28.248 ;
     RECT  112.337 1.728 113.108 2.28 ;
     RECT  111.917 24.96 113.108 25.656 ;
     RECT  112.085 26.64 113.108 26.808 ;
     RECT  113.075 27.936 113.108 28.092 ;
     RECT  113.108 1.728 113.212 28.092 ;
     RECT  113.212 1.728 113.404 27.96 ;
     RECT  113.404 26.592 113.717 26.712 ;
     RECT  113.404 27.936 113.861 27.96 ;
     RECT  114.181 28.512 114.401 28.536 ;
     RECT  113.717 26.688 114.757 26.712 ;
     RECT  114.757 26.688 115.693 26.808 ;
     RECT  115.693 26.352 115.729 26.808 ;
     RECT  113.404 1.728 115.808 1.752 ;
     RECT  113.404 24.96 115.808 25.272 ;
     RECT  115.729 26.256 115.808 26.808 ;
     RECT  115.292 27.936 115.808 27.96 ;
     RECT  115.808 1.728 115.912 28.092 ;
     RECT  115.912 1.728 116.104 27.822 ;
     RECT  116.104 1.728 116.243 2.28 ;
     RECT  116.104 24.96 116.243 27.822 ;
     RECT  115.909 29.088 116.273 29.112 ;
     RECT  116.243 24.96 116.291 25.56 ;
     RECT  116.243 26.64 116.317 27.48 ;
     RECT  116.485 29.664 116.572 29.688 ;
     RECT  117.061 28.512 117.245 28.536 ;
     RECT  116.291 24.96 117.313 25.272 ;
     RECT  116.243 1.728 118.508 1.752 ;
     RECT  117.313 24.864 118.508 25.272 ;
     RECT  116.317 26.64 118.508 26.664 ;
     RECT  117.637 27.936 118.508 27.96 ;
     RECT  118.508 1.728 118.612 28.092 ;
     RECT  118.612 1.728 118.804 27.822 ;
     RECT  118.804 27.168 118.937 27.192 ;
     RECT  118.213 29.664 119.549 29.688 ;
     RECT  119.941 27.36 120.161 27.384 ;
     RECT  118.804 24.96 120.517 25.656 ;
     RECT  120.517 24.96 120.769 26.04 ;
     RECT  121.052 29.088 121.139 29.112 ;
     RECT  118.804 1.728 121.208 1.752 ;
     RECT  120.769 24.96 121.208 26.568 ;
     RECT  121.208 1.728 121.312 28.092 ;
     RECT  121.312 1.728 121.493 28.056 ;
     RECT  121.493 1.728 121.504 27.96 ;
     RECT  121.661 29.04 121.745 29.064 ;
     RECT  121.504 24.96 122.105 25.272 ;
     RECT  121.504 27.936 122.357 27.96 ;
     RECT  122.78 29.664 123.443 29.688 ;
     RECT  122.105 25.2 123.733 25.272 ;
     RECT  121.504 26.544 123.733 26.568 ;
     RECT  121.504 1.728 123.908 1.752 ;
     RECT  123.733 25.2 123.908 27.096 ;
     RECT  123.781 29.04 123.908 29.064 ;
     RECT  123.908 1.728 124.019 29.064 ;
     RECT  124.019 1.728 124.204 28.488 ;
     RECT  124.204 28.464 124.733 28.488 ;
     RECT  124.204 24.96 124.841 26.664 ;
     RECT  125.084 29.088 125.171 29.112 ;
     RECT  124.841 25.056 125.237 26.664 ;
     RECT  125.701 29.664 125.813 29.688 ;
     RECT  125.237 25.056 126.349 26.232 ;
     RECT  126.349 25.008 126.493 26.232 ;
     RECT  126.493 25.008 126.565 26.376 ;
     RECT  126.277 27.936 126.565 27.96 ;
     RECT  124.204 1.728 126.608 1.752 ;
     RECT  126.565 25.008 126.608 27.96 ;
     RECT  126.608 1.728 126.712 28.092 ;
     RECT  126.712 1.728 126.904 27.96 ;
     RECT  126.853 29.088 127.001 29.112 ;
     RECT  126.904 25.008 127.145 25.272 ;
     RECT  126.904 26.352 127.145 26.856 ;
     RECT  126.904 1.728 127.649 1.752 ;
     RECT  127.145 26.832 127.685 26.856 ;
     RECT  127.717 0.576 127.801 0.6 ;
     RECT  126.904 27.936 128.261 27.96 ;
     RECT  128.149 0.192 128.339 0.216 ;
     RECT  128.509 29.088 128.627 29.112 ;
     RECT  127.145 25.248 128.725 25.272 ;
     RECT  128.689 26.832 128.869 26.856 ;
     RECT  129.049 29.664 129.203 29.688 ;
     RECT  128.861 1.728 129.308 1.752 ;
     RECT  128.725 25.056 129.308 25.272 ;
     RECT  128.869 26.304 129.308 26.856 ;
     RECT  129.308 1.728 129.604 28.092 ;
     RECT  129.604 1.728 129.731 2.28 ;
     RECT  129.604 25.2 129.731 27.192 ;
     RECT  129.769 0.192 130.067 0.216 ;
     RECT  129.725 28.464 130.385 28.488 ;
     RECT  129.731 25.2 130.444 25.992 ;
     RECT  129.731 1.728 130.781 1.752 ;
     RECT  129.731 27.168 131.461 27.192 ;
     RECT  130.444 25.2 131.749 25.272 ;
     RECT  131.461 27.168 131.749 27.96 ;
     RECT  131.065 0.192 131.795 0.216 ;
     RECT  131.893 2.832 132.008 2.856 ;
     RECT  131.749 25.2 132.008 27.96 ;
     RECT  130.885 29.664 132.083 29.688 ;
     RECT  132.008 2.148 132.112 28.092 ;
     RECT  132.112 2.148 132.304 27.822 ;
     RECT  132.304 25.008 132.365 26.76 ;
     RECT  132.365 25.008 132.905 25.656 ;
     RECT  132.905 25.152 132.941 25.656 ;
     RECT  133.189 28.464 133.273 28.488 ;
     RECT  133.297 0.192 133.571 0.216 ;
     RECT  132.365 26.736 134.161 26.76 ;
     RECT  132.941 25.152 134.305 25.272 ;
     RECT  134.161 26.256 134.305 26.76 ;
     RECT  134.197 14.256 134.333 14.28 ;
     RECT  132.325 1.728 134.377 1.752 ;
     RECT  134.197 2.832 134.377 2.856 ;
     RECT  134.305 25.152 134.521 26.76 ;
     RECT  133.765 27.936 134.521 27.96 ;
     RECT  134.521 25.152 134.593 27.96 ;
     RECT  134.377 1.728 134.708 2.856 ;
     RECT  134.333 14.256 134.708 14.808 ;
     RECT  134.593 25.152 134.708 28.2 ;
     RECT  134.708 1.728 134.749 28.2 ;
     RECT  134.749 2.148 134.812 28.2 ;
     RECT  134.812 2.418 134.963 28.2 ;
     RECT  134.963 2.418 135.004 27.96 ;
     RECT  135.061 0.192 135.299 0.216 ;
     RECT  135.004 24.528 135.347 26.664 ;
     RECT  135.004 13.68 135.361 14.808 ;
     RECT  135.347 24.528 135.641 25.272 ;
     RECT  135.817 1.728 136.357 1.752 ;
     RECT  135.004 2.832 136.357 2.856 ;
     RECT  135.347 26.64 136.433 26.664 ;
     RECT  136.357 1.728 136.441 2.856 ;
     RECT  135.641 25.008 137.141 25.272 ;
     RECT  135.004 27.936 137.185 27.96 ;
     RECT  137.141 24.576 137.249 25.272 ;
     RECT  137.185 27.936 137.269 28.488 ;
     RECT  136.441 1.728 137.408 1.752 ;
     RECT  136.441 2.832 137.408 2.856 ;
     RECT  135.361 13.68 137.408 14.232 ;
     RECT  137.249 24.528 137.408 25.272 ;
     RECT  136.825 26.688 137.408 26.712 ;
     RECT  137.269 27.936 137.408 28.092 ;
     RECT  137.408 1.728 137.512 28.092 ;
     RECT  137.512 1.728 137.704 27.96 ;
     RECT  137.704 24.528 137.939 26.904 ;
     RECT  137.704 1.728 138.305 2.856 ;
     RECT  137.939 24.528 138.701 26.712 ;
     RECT  137.704 13.68 138.709 14.808 ;
     RECT  138.305 2.256 138.737 2.856 ;
     RECT  138.709 13.68 138.773 14.856 ;
     RECT  138.701 24.528 138.947 26.28 ;
     RECT  138.773 14.208 138.953 14.856 ;
     RECT  138.953 14.256 139.013 14.856 ;
     RECT  138.481 0.192 139.331 0.216 ;
     RECT  138.947 24.912 139.669 26.28 ;
     RECT  138.737 2.832 139.813 2.856 ;
     RECT  139.813 2.256 139.909 2.856 ;
     RECT  137.704 27.936 140.06 27.96 ;
     RECT  139.669 24.912 140.065 26.664 ;
     RECT  140.06 27.936 140.065 28.248 ;
     RECT  139.909 1.728 140.108 2.856 ;
     RECT  139.013 14.256 140.108 15.384 ;
     RECT  140.065 24.912 140.108 28.248 ;
     RECT  140.108 1.728 140.147 28.248 ;
     RECT  140.147 1.728 140.212 28.092 ;
     RECT  140.212 1.728 140.404 27.96 ;
     RECT  140.404 24.768 140.723 27.96 ;
     RECT  140.723 24.768 140.933 27.144 ;
     RECT  140.933 24.768 140.969 26.664 ;
     RECT  140.969 24.768 141.155 26.28 ;
     RECT  141.253 28.848 141.365 28.872 ;
     RECT  140.404 14.832 141.373 15.384 ;
     RECT  141.685 14.784 141.829 14.808 ;
     RECT  141.155 25.248 142.117 26.28 ;
     RECT  141.685 27.936 142.369 27.96 ;
     RECT  140.404 1.728 142.405 1.752 ;
     RECT  140.404 2.832 142.405 2.856 ;
     RECT  142.369 27.936 142.453 28.488 ;
     RECT  142.117 25.248 142.549 26.76 ;
     RECT  142.549 25.248 142.621 26.856 ;
     RECT  142.405 1.728 142.808 2.856 ;
     RECT  141.829 14.256 142.808 14.808 ;
     RECT  142.621 25.104 142.808 26.856 ;
     RECT  142.453 27.936 142.808 28.2 ;
     RECT  142.808 1.728 143.027 28.2 ;
     RECT  143.027 1.728 143.104 27.822 ;
     RECT  143.104 14.256 144.109 15.384 ;
     RECT  144.125 28.464 144.209 28.488 ;
     RECT  144.109 14.784 144.245 15.384 ;
     RECT  143.104 25.056 144.245 26.664 ;
     RECT  143.104 1.728 144.281 2.856 ;
     RECT  144.245 25.248 144.529 26.664 ;
     RECT  144.565 29.664 144.755 29.688 ;
     RECT  144.245 14.832 145.381 15.384 ;
     RECT  144.281 1.728 145.508 1.752 ;
     RECT  144.281 2.832 145.508 2.856 ;
     RECT  145.381 14.736 145.508 15.384 ;
     RECT  144.529 25.248 145.508 26.856 ;
     RECT  145.033 27.936 145.508 27.96 ;
     RECT  145.508 1.728 145.715 28.092 ;
     RECT  145.715 2.256 145.804 28.092 ;
     RECT  145.804 27.936 145.82 28.092 ;
     RECT  145.82 27.936 145.907 28.2 ;
     RECT  145.804 14.256 146.051 15.384 ;
     RECT  145.804 2.256 146.053 2.856 ;
     RECT  146.051 14.736 146.081 15.384 ;
     RECT  146.081 14.832 146.233 15.384 ;
     RECT  145.861 0.192 146.339 0.216 ;
     RECT  146.053 2.832 146.873 2.856 ;
     RECT  145.804 25.152 147.107 26.856 ;
     RECT  146.233 14.832 147.197 15.096 ;
     RECT  147.107 25.152 147.661 26.76 ;
     RECT  146.861 1.728 147.769 1.752 ;
     RECT  147.761 13.68 147.941 13.704 ;
     RECT  147.197 14.832 147.941 15.048 ;
     RECT  147.769 1.728 148.069 2.28 ;
     RECT  145.907 27.936 148.093 27.96 ;
     RECT  148.069 1.728 148.208 2.856 ;
     RECT  147.941 13.68 148.208 15.048 ;
     RECT  147.661 25.104 148.208 26.76 ;
     RECT  148.093 27.936 148.208 28.248 ;
     RECT  148.208 1.728 148.211 28.248 ;
     RECT  148.211 1.728 148.312 28.092 ;
     RECT  148.312 1.728 148.504 27.822 ;
     RECT  148.504 1.728 148.673 1.752 ;
     RECT  148.741 0.192 149.219 0.216 ;
     RECT  148.504 25.248 149.401 26.76 ;
     RECT  149.401 25.248 150.001 26.232 ;
     RECT  150.469 29.664 150.553 29.688 ;
     RECT  150.001 24.912 150.613 26.232 ;
     RECT  149.845 14.784 150.685 14.808 ;
     RECT  149.741 1.728 150.721 1.752 ;
     RECT  150.721 1.728 150.908 2.28 ;
     RECT  150.685 14.256 150.908 14.808 ;
     RECT  150.613 24.912 150.908 26.328 ;
     RECT  149.893 27.888 150.908 27.912 ;
     RECT  150.908 1.728 151.045 28.092 ;
     RECT  151.045 1.728 151.204 28.248 ;
     RECT  151.204 14.736 151.265 14.76 ;
     RECT  151.204 27.936 151.331 28.248 ;
     RECT  151.204 24.912 152.197 25.56 ;
     RECT  152.189 14.832 152.233 14.856 ;
     RECT  152.197 24.912 152.233 26.232 ;
     RECT  152.197 2.832 152.281 2.856 ;
     RECT  151.204 1.728 152.341 1.752 ;
     RECT  152.233 14.256 152.387 14.856 ;
     RECT  152.387 14.784 152.405 14.856 ;
     RECT  152.341 1.728 152.425 2.28 ;
     RECT  152.233 24.528 152.483 26.232 ;
     RECT  152.405 14.784 152.489 15.384 ;
     RECT  153.349 29.088 153.497 29.112 ;
     RECT  152.425 1.728 153.608 1.752 ;
     RECT  152.489 14.784 153.608 14.808 ;
     RECT  152.483 25.008 153.608 26.232 ;
     RECT  151.331 27.936 153.608 27.96 ;
     RECT  153.608 1.728 153.875 28.092 ;
     RECT  153.875 2.208 153.904 28.092 ;
     RECT  153.904 25.008 154.325 25.992 ;
     RECT  153.925 28.176 154.397 28.2 ;
     RECT  153.904 2.208 154.512 2.232 ;
     RECT  154.325 25.248 155.437 25.992 ;
     RECT  154.501 29.664 155.699 29.688 ;
     RECT  155.077 28.464 156.229 28.488 ;
     RECT  154.961 1.728 156.308 1.752 ;
     RECT  155.437 25.056 156.308 25.992 ;
     RECT  156.229 28.464 156.308 29.064 ;
     RECT  156.308 1.728 156.412 29.064 ;
     RECT  156.412 1.728 156.604 27.96 ;
     RECT  156.412 29.04 156.755 29.064 ;
     RECT  156.604 26.736 156.773 27.96 ;
     RECT  156.773 26.736 156.809 26.808 ;
     RECT  157.34 29.664 157.427 29.688 ;
     RECT  156.604 25.248 157.777 25.272 ;
     RECT  156.773 27.936 158.044 27.96 ;
     RECT  157.777 25.248 158.065 25.656 ;
     RECT  156.809 26.736 158.065 26.76 ;
     RECT  158.437 0.192 158.579 0.216 ;
     RECT  158.533 29.088 158.861 29.112 ;
     RECT  156.604 1.728 159.008 1.752 ;
     RECT  158.065 25.248 159.008 26.76 ;
     RECT  159.008 1.728 159.112 28.092 ;
     RECT  159.068 29.664 159.155 29.688 ;
     RECT  159.112 1.728 159.304 27.822 ;
     RECT  159.304 27.36 159.797 27.384 ;
     RECT  159.304 25.056 160.165 25.992 ;
     RECT  160.261 29.664 160.445 29.688 ;
     RECT  160.837 27.936 161.089 27.96 ;
     RECT  159.304 1.728 161.708 1.752 ;
     RECT  160.165 25.248 161.708 25.992 ;
     RECT  161.089 27.936 161.708 28.056 ;
     RECT  161.593 0.528 161.987 0.552 ;
     RECT  161.708 1.728 162.004 28.092 ;
     RECT  161.989 29.088 162.317 29.112 ;
     RECT  162.565 28.512 162.857 28.536 ;
     RECT  163.141 29.664 163.228 29.688 ;
     RECT  162.004 1.728 163.729 1.752 ;
     RECT  162.004 25.248 164.077 25.272 ;
     RECT  163.537 26.352 164.077 26.376 ;
     RECT  164.077 25.248 164.293 26.376 ;
     RECT  163.717 27.936 164.293 27.96 ;
     RECT  164.293 29.664 164.38 29.688 ;
     RECT  164.245 2.148 164.408 2.28 ;
     RECT  164.293 25.248 164.408 27.96 ;
     RECT  164.408 2.148 164.704 28.092 ;
     RECT  164.704 27.936 164.869 28.092 ;
     RECT  164.704 25.056 166.129 26.232 ;
     RECT  164.869 27.936 166.309 28.488 ;
     RECT  166.129 25.056 166.921 26.664 ;
     RECT  166.309 27.888 166.921 28.488 ;
     RECT  166.921 25.056 166.961 28.488 ;
     RECT  164.821 1.728 167.108 1.752 ;
     RECT  166.961 25.056 167.108 28.248 ;
     RECT  167.108 1.728 167.404 28.248 ;
     RECT  167.404 26.64 167.645 28.248 ;
     RECT  167.645 26.64 167.753 28.056 ;
     RECT  167.404 1.728 168.437 1.752 ;
     RECT  167.753 27.072 168.617 28.056 ;
     RECT  168.617 27.072 168.725 28.008 ;
     RECT  168.725 27.072 168.833 27.96 ;
     RECT  168.833 27.936 169.808 27.96 ;
     RECT  169.808 2.148 169.912 28.092 ;
     RECT  169.912 2.418 170.104 27.822 ;
    LAYER M5 ;
     RECT  4.752 0.144 168.36 0.227 ;
     RECT  48.24 0.227 59.88 0.275 ;
     RECT  149.76 0.227 168.36 0.563 ;
     RECT  29.088 0.227 31.464 0.611 ;
     RECT  36.624 0.227 43.608 0.611 ;
     RECT  63.312 0.227 63.336 0.611 ;
     RECT  64.512 0.227 75.528 0.611 ;
     RECT  95.232 0.227 96.984 0.611 ;
     RECT  98.112 0.227 104.52 0.611 ;
     RECT  106.272 0.227 127.752 0.611 ;
     RECT  4.752 0.227 8.232 1.763 ;
     RECT  9.36 0.227 25.656 1.763 ;
     RECT  27.936 0.227 27.96 1.763 ;
     RECT  29.088 0.611 30.888 1.763 ;
     RECT  34.896 0.227 35.496 1.763 ;
     RECT  36.624 0.611 37.848 1.763 ;
     RECT  38.976 0.611 42.456 1.763 ;
     RECT  43.584 0.611 43.608 1.763 ;
     RECT  44.784 0.227 47.112 1.763 ;
     RECT  48.24 0.275 58.728 1.763 ;
     RECT  59.856 0.275 59.88 1.763 ;
     RECT  61.008 0.227 62.184 1.763 ;
     RECT  64.512 0.611 66.264 1.763 ;
     RECT  67.392 0.611 67.992 1.763 ;
     RECT  69.12 0.611 69.144 1.763 ;
     RECT  70.272 0.611 72.648 1.763 ;
     RECT  73.776 0.611 75.528 1.763 ;
     RECT  76.656 0.227 91.8 1.763 ;
     RECT  92.928 0.227 94.104 1.763 ;
     RECT  95.232 0.611 95.832 1.763 ;
     RECT  98.112 0.611 103.944 1.763 ;
     RECT  106.272 0.611 127.176 1.763 ;
     RECT  128.88 0.227 129.48 1.763 ;
     RECT  130.608 0.227 130.632 1.763 ;
     RECT  132.336 0.227 132.984 1.763 ;
     RECT  134.112 0.227 134.712 1.763 ;
     RECT  135.84 0.227 138.168 1.763 ;
     RECT  139.92 0.227 145.704 1.763 ;
     RECT  146.88 0.227 148.632 1.763 ;
     RECT  149.76 0.563 161.4 1.763 ;
     RECT  162.528 0.563 168.36 1.763 ;
     RECT  26.784 0.227 26.808 2.137 ;
     RECT  32.592 0.227 33.768 2.137 ;
     RECT  34.896 1.763 35.448 2.137 ;
     RECT  64.512 1.763 64.812 2.137 ;
     RECT  67.392 1.763 67.608 2.137 ;
     RECT  72.6 1.763 72.648 2.137 ;
     RECT  93.504 1.763 94.104 2.137 ;
     RECT  96.96 0.611 96.984 2.137 ;
     RECT  134.4 1.763 134.712 2.137 ;
     RECT  2.4 2.137 2.52 2.151 ;
     RECT  26.7 2.137 26.82 2.151 ;
     RECT  72.6 2.137 72.72 2.151 ;
     RECT  75.3 1.763 75.528 2.151 ;
     RECT  91.392 1.763 91.8 2.151 ;
     RECT  96.9 2.137 97.02 2.151 ;
     RECT  105 2.137 105.12 2.151 ;
     RECT  129.3 1.763 129.48 2.151 ;
     RECT  134.4 2.137 134.82 2.151 ;
     RECT  145.5 1.763 145.704 2.151 ;
     RECT  169.8 2.137 169.92 2.151 ;
     RECT  53.7 1.763 54.648 2.243 ;
     RECT  153.6 1.763 154.44 2.243 ;
     RECT  36.72 1.763 37.848 2.245 ;
     RECT  64.5 2.137 64.812 2.245 ;
     RECT  91.392 2.151 91.812 2.245 ;
     RECT  96.9 2.151 97.212 2.245 ;
     RECT  129.3 2.151 129.612 2.245 ;
     RECT  137.4 1.763 138.168 2.245 ;
     RECT  139.92 1.763 140.412 2.245 ;
     RECT  145.5 2.151 145.812 2.245 ;
     RECT  164.256 1.763 164.712 2.291 ;
     RECT  45.6 1.763 45.912 2.773 ;
     RECT  29.4 1.763 29.712 2.821 ;
     RECT  30.96 2.245 30.984 2.821 ;
     RECT  32.1 2.137 33.768 2.821 ;
     RECT  34.8 2.137 35.448 2.821 ;
     RECT  36.72 2.245 38.616 2.821 ;
     RECT  40.2 1.763 40.512 2.821 ;
     RECT  67.2 2.137 67.608 2.821 ;
     RECT  86.1 1.763 86.412 2.821 ;
     RECT  87.456 1.763 87.48 2.821 ;
     RECT  88.704 1.763 89.112 2.821 ;
     RECT  90.384 1.763 90.408 2.821 ;
     RECT  91.392 2.245 92.328 2.821 ;
     RECT  93.504 2.137 94.512 2.821 ;
     RECT  96.72 2.245 97.212 2.821 ;
     RECT  132 2.137 132.312 2.821 ;
     RECT  134.4 2.151 135.012 2.821 ;
     RECT  136.368 1.763 136.392 2.821 ;
     RECT  137.4 2.245 138.696 2.821 ;
     RECT  139.824 2.245 140.412 2.821 ;
     RECT  142.416 1.763 144.072 2.821 ;
     RECT  145.5 2.245 146.04 2.821 ;
     RECT  147.792 1.763 148.512 2.821 ;
     RECT  152.352 1.763 152.376 2.821 ;
     RECT  7.8 1.763 8.112 3.589 ;
     RECT  32.1 2.821 40.512 13.715 ;
     RECT  134.208 2.821 148.512 13.715 ;
     RECT  85.824 2.821 97.944 14.101 ;
     RECT  85.824 14.101 97.992 14.197 ;
     RECT  29.4 2.821 30.984 14.291 ;
     RECT  36.432 13.715 40.512 14.291 ;
     RECT  134.208 13.715 146.856 14.291 ;
     RECT  85.824 14.197 98.04 14.675 ;
     RECT  32.1 13.715 35.448 14.677 ;
     RECT  36.432 14.291 37.944 14.677 ;
     RECT  150.768 1.763 151.212 14.725 ;
     RECT  32.1 14.677 37.944 14.773 ;
     RECT  150.72 14.725 151.212 14.773 ;
     RECT  152.208 2.821 152.376 14.773 ;
     RECT  153.6 2.243 153.912 14.773 ;
     RECT  26.7 2.151 27.912 14.867 ;
     RECT  29.4 14.291 30.648 14.867 ;
     RECT  152.208 14.773 153.912 14.867 ;
     RECT  134.352 14.291 146.856 15.061 ;
     RECT  147.984 13.715 148.512 15.061 ;
     RECT  29.4 14.867 29.712 15.349 ;
     RECT  31.728 14.773 37.944 15.349 ;
     RECT  7.488 3.589 8.112 23.317 ;
     RECT  53.7 2.243 54.012 24.469 ;
     RECT  30.96 15.349 37.944 24.563 ;
     RECT  38.928 14.291 40.512 24.563 ;
     RECT  86.1 14.675 98.04 24.563 ;
     RECT  134.352 15.061 148.512 24.563 ;
     RECT  152.448 14.867 153.912 24.563 ;
     RECT  56.4 1.763 56.712 24.613 ;
     RECT  86.1 24.563 89.448 24.659 ;
     RECT  95.664 24.563 97.992 24.707 ;
     RECT  102.3 1.763 102.612 24.709 ;
     RECT  0.24 9.733 0.264 24.755 ;
     RECT  42.768 2.137 43.212 24.901 ;
     RECT  52.416 24.469 52.44 24.995 ;
     RECT  21.3 1.763 21.612 25.045 ;
     RECT  56.4 24.613 57.624 25.045 ;
     RECT  75.3 2.151 75.612 25.045 ;
     RECT  78 1.763 78.312 25.045 ;
     RECT  156.3 1.763 156.612 25.045 ;
     RECT  159 1.763 159.312 25.045 ;
     RECT  164.4 2.291 164.712 25.045 ;
     RECT  39.072 24.563 39.096 25.139 ;
     RECT  40.08 24.563 40.512 25.139 ;
     RECT  86.1 24.659 87.72 25.139 ;
     RECT  136.512 24.563 148.512 25.139 ;
     RECT  75.168 25.045 75.612 25.141 ;
     RECT  99.6 1.763 99.912 25.141 ;
     RECT  129.3 2.245 129.72 25.189 ;
     RECT  7.44 23.317 8.112 25.283 ;
     RECT  53.424 24.469 54.012 25.283 ;
     RECT  99.6 25.141 100.008 25.283 ;
     RECT  110.256 1.763 110.712 25.285 ;
     RECT  112.368 1.763 113.412 25.285 ;
     RECT  67.2 2.821 67.656 25.333 ;
     RECT  137.4 25.139 148.512 25.333 ;
     RECT  13.2 1.763 13.512 25.525 ;
     RECT  86.1 25.139 86.616 25.525 ;
     RECT  115.8 1.763 116.232 25.525 ;
     RECT  149.856 14.773 151.212 25.525 ;
     RECT  164.4 25.045 165.288 25.571 ;
     RECT  13.2 25.525 13.608 25.573 ;
     RECT  131.904 2.821 132.312 25.621 ;
     RECT  90.48 24.563 94.512 25.715 ;
     RECT  101.76 24.709 102.612 25.715 ;
     RECT  134.352 24.563 135.336 25.715 ;
     RECT  83.4 1.763 83.712 25.717 ;
     RECT  131.904 25.621 132.648 25.717 ;
     RECT  164.4 25.571 164.712 25.717 ;
     RECT  72.6 2.151 72.912 25.765 ;
     RECT  80.7 1.763 81.012 25.765 ;
     RECT  107.7 1.763 108.12 25.765 ;
     RECT  18.6 1.763 18.912 25.813 ;
     RECT  123.9 1.763 124.212 25.813 ;
     RECT  59.1 2.137 59.412 25.861 ;
     RECT  64.32 2.245 64.812 25.861 ;
     RECT  77.232 25.045 78.312 25.861 ;
     RECT  137.4 25.333 148.632 25.861 ;
     RECT  21.3 25.045 21.96 25.955 ;
     RECT  56.304 25.045 57.624 26.003 ;
     RECT  129.3 25.189 130.392 26.003 ;
     RECT  155.568 25.045 156.612 26.003 ;
     RECT  159 25.045 160.152 26.003 ;
     RECT  21.3 25.955 21.612 26.005 ;
     RECT  121.2 1.763 121.512 26.005 ;
     RECT  123.792 25.813 124.212 26.005 ;
     RECT  7.488 25.283 8.112 26.051 ;
     RECT  13.2 25.573 14.568 26.053 ;
     RECT  72.432 25.765 72.912 26.099 ;
     RECT  95.664 24.707 97.464 26.101 ;
     RECT  13.104 26.053 14.568 26.243 ;
     RECT  28.464 15.349 29.712 26.243 ;
     RECT  30.96 24.563 35.736 26.243 ;
     RECT  36.768 24.563 37.812 26.243 ;
     RECT  42.768 24.901 43.944 26.243 ;
     RECT  64.32 25.861 64.92 26.243 ;
     RECT  66.624 25.333 67.656 26.243 ;
     RECT  68.64 2.677 68.664 26.243 ;
     RECT  77.232 25.861 78.504 26.243 ;
     RECT  87.696 25.139 87.72 26.243 ;
     RECT  90.48 25.715 92.952 26.243 ;
     RECT  93.984 25.715 94.512 26.243 ;
     RECT  95.52 26.101 97.464 26.243 ;
     RECT  110.256 25.285 113.412 26.243 ;
     RECT  134.352 25.715 135.012 26.243 ;
     RECT  137.4 25.861 148.776 26.243 ;
     RECT  149.856 25.525 151.32 26.243 ;
     RECT  152.496 24.563 153.912 26.243 ;
     RECT  24 1.763 24.312 26.245 ;
     RECT  129.3 26.003 129.72 26.291 ;
     RECT  139.68 26.243 141.336 26.291 ;
     RECT  142.704 26.243 145.812 26.291 ;
     RECT  34.176 26.243 35.304 26.339 ;
     RECT  92.832 26.243 92.856 26.339 ;
     RECT  134.4 26.243 135.012 26.339 ;
     RECT  142.8 26.291 145.812 26.339 ;
     RECT  150.768 26.243 151.32 26.339 ;
     RECT  66.96 26.243 67.656 26.387 ;
     RECT  88.8 24.659 89.448 26.387 ;
     RECT  80.592 25.765 81.012 26.485 ;
     RECT  74.688 25.141 75.612 26.627 ;
     RECT  142.8 26.339 143.64 26.627 ;
     RECT  95.52 26.243 97.368 26.675 ;
     RECT  102.144 25.715 102.612 26.675 ;
     RECT  110.4 26.243 113.412 26.675 ;
     RECT  139.68 26.291 140.412 26.675 ;
     RECT  34.176 26.339 35.112 26.723 ;
     RECT  137.4 26.243 138.072 26.723 ;
     RECT  147.024 26.243 148.776 26.725 ;
     RECT  56.304 26.003 56.808 26.771 ;
     RECT  90.48 26.243 91.812 26.771 ;
     RECT  96.336 26.675 97.368 26.771 ;
     RECT  147.024 26.725 149.352 26.771 ;
     RECT  156.3 26.003 156.612 26.773 ;
     RECT  79.968 26.485 81.012 26.819 ;
     RECT  91.056 26.771 91.812 26.819 ;
     RECT  112.128 26.675 113.412 26.819 ;
     RECT  59.1 25.861 59.544 26.821 ;
     RECT  144.72 26.339 145.812 26.867 ;
     RECT  147.072 26.771 147.096 26.867 ;
     RECT  137.4 26.723 137.928 26.915 ;
     RECT  105 2.151 105.312 27.013 ;
     RECT  48.3 1.763 48.612 27.061 ;
     RECT  123.744 26.005 124.212 27.107 ;
     RECT  75.3 26.627 75.612 27.301 ;
     RECT  7.8 26.051 8.112 27.349 ;
     RECT  104.88 27.013 105.312 27.349 ;
     RECT  107.7 25.765 108.168 27.349 ;
     RECT  120.528 26.005 121.512 27.349 ;
     RECT  159 26.003 159.312 27.349 ;
     RECT  48.3 27.061 48.84 27.491 ;
     RECT  115.8 25.525 116.28 27.491 ;
     RECT  13.104 26.243 13.608 27.683 ;
     RECT  148.2 26.771 149.352 27.877 ;
     RECT  5.1 1.763 5.412 27.925 ;
     RECT  6.48 27.349 8.112 27.925 ;
     RECT  10.5 1.763 10.812 27.925 ;
     RECT  18.48 25.813 18.912 27.925 ;
     RECT  21.168 26.005 21.612 27.925 ;
     RECT  23.904 26.245 24.312 27.925 ;
     RECT  26.7 14.867 27.012 27.925 ;
     RECT  29.232 26.243 29.712 27.925 ;
     RECT  32.1 26.243 32.412 27.925 ;
     RECT  34.8 26.723 35.112 27.925 ;
     RECT  37.008 26.243 37.812 27.925 ;
     RECT  40.2 25.139 40.512 27.925 ;
     RECT  45.6 2.773 46.008 27.925 ;
     RECT  48.3 27.491 48.612 27.925 ;
     RECT  51 1.763 51.312 27.925 ;
     RECT  53.7 25.283 54.012 27.925 ;
     RECT  56.4 26.771 56.808 27.925 ;
     RECT  58.32 26.821 59.544 27.925 ;
     RECT  61.8 1.763 62.112 27.925 ;
     RECT  64.5 26.243 64.92 27.925 ;
     RECT  69.9 2.137 70.212 27.925 ;
     RECT  72.6 26.099 72.912 27.925 ;
     RECT  78 26.243 78.504 27.925 ;
     RECT  80.7 26.819 81.012 27.925 ;
     RECT  83.28 25.717 83.712 27.925 ;
     RECT  85.968 25.525 86.616 27.925 ;
     RECT  88.8 26.387 89.4 27.925 ;
     RECT  91.152 26.819 91.812 27.925 ;
     RECT  94.032 26.243 94.512 27.925 ;
     RECT  99.6 25.283 99.912 27.925 ;
     RECT  104.4 27.349 105.312 27.925 ;
     RECT  106.704 26.005 106.728 27.925 ;
     RECT  107.7 27.349 108.456 27.925 ;
     RECT  110.4 26.675 110.712 27.925 ;
     RECT  113.1 26.819 113.412 27.925 ;
     RECT  114.768 26.773 114.792 27.925 ;
     RECT  115.8 27.491 116.232 27.925 ;
     RECT  118.5 1.763 118.812 27.925 ;
     RECT  119.952 27.349 121.512 27.925 ;
     RECT  126.6 1.763 126.912 27.925 ;
     RECT  131.76 25.717 132.648 27.925 ;
     RECT  134.592 26.339 135.012 27.925 ;
     RECT  137.4 26.915 137.832 27.925 ;
     RECT  140.1 26.675 140.412 27.925 ;
     RECT  142.8 26.627 143.592 27.925 ;
     RECT  145.5 26.867 145.812 27.925 ;
     RECT  148.2 27.877 149.928 27.925 ;
     RECT  150.9 26.339 151.32 27.925 ;
     RECT  153.6 26.243 153.912 27.925 ;
     RECT  156.3 26.773 156.744 27.925 ;
     RECT  161.7 2.137 162.012 27.925 ;
     RECT  164.304 25.717 164.712 27.925 ;
     RECT  163.728 27.925 166.056 27.973 ;
     RECT  167.1 1.763 167.412 27.973 ;
     RECT  163.728 27.973 167.412 28.021 ;
     RECT  2.4 2.151 2.712 28.089 ;
     RECT  4.752 27.925 5.412 28.089 ;
     RECT  10.5 27.925 11.688 28.089 ;
     RECT  20.88 27.925 21.612 28.089 ;
     RECT  39.312 27.925 40.512 28.089 ;
     RECT  72.6 27.925 73.896 28.089 ;
     RECT  80.7 27.925 83.712 28.089 ;
     RECT  87.696 27.925 94.512 28.089 ;
     RECT  96.336 26.771 97.212 28.089 ;
     RECT  114.768 27.925 116.232 28.089 ;
     RECT  117.648 27.925 118.812 28.089 ;
     RECT  169.8 2.151 170.112 28.089 ;
     RECT  2.4 28.089 2.52 28.103 ;
     RECT  6.48 27.925 9.384 28.103 ;
     RECT  10.5 28.089 10.62 28.103 ;
     RECT  13.2 27.683 13.608 28.103 ;
     RECT  15.9 1.763 16.212 28.103 ;
     RECT  45.6 27.925 46.248 28.103 ;
     RECT  47.376 27.925 48.612 28.103 ;
     RECT  53.7 27.925 54.888 28.103 ;
     RECT  56.4 27.925 60.648 28.103 ;
     RECT  64.5 27.925 65.832 28.103 ;
     RECT  66.96 26.387 67.512 28.103 ;
     RECT  69.264 27.925 70.44 28.103 ;
     RECT  72.6 28.089 72.72 28.103 ;
     RECT  80.7 28.089 83.688 28.103 ;
     RECT  84.816 27.925 86.616 28.103 ;
     RECT  87.696 28.089 94.32 28.103 ;
     RECT  96.336 28.089 97.02 28.103 ;
     RECT  99.216 27.925 100.392 28.103 ;
     RECT  102.3 26.675 102.612 28.103 ;
     RECT  114.768 28.089 115.92 28.103 ;
     RECT  117.648 28.089 118.62 28.103 ;
     RECT  119.952 27.925 122.28 28.103 ;
     RECT  126.288 27.925 128.04 28.103 ;
     RECT  129.3 26.291 129.612 28.103 ;
     RECT  131.472 27.925 132.648 28.103 ;
     RECT  150.9 27.925 153.912 28.103 ;
     RECT  159 27.349 159.72 28.103 ;
     RECT  160.848 27.925 162.012 28.103 ;
     RECT  163.728 28.021 168.36 28.103 ;
     RECT  169.8 28.089 169.92 28.103 ;
     RECT  106.704 27.925 110.712 28.165 ;
     RECT  13.392 28.103 13.608 28.211 ;
     RECT  61.8 27.925 62.952 28.213 ;
     RECT  113.1 27.925 113.64 28.213 ;
     RECT  17.424 27.925 17.448 28.453 ;
     RECT  18.48 27.925 19.176 28.453 ;
     RECT  42.768 26.243 43.212 28.453 ;
     RECT  61.776 28.213 62.952 28.453 ;
     RECT  75.3 27.301 75.72 28.453 ;
     RECT  77.904 27.925 78.504 28.453 ;
     RECT  87.696 28.103 94.056 28.453 ;
     RECT  123.792 27.107 124.212 28.453 ;
     RECT  132.624 28.103 132.648 28.453 ;
     RECT  133.776 27.925 140.712 28.453 ;
     RECT  141.84 27.925 143.592 28.453 ;
     RECT  17.424 28.453 19.752 28.501 ;
     RECT  46.224 28.103 46.248 28.501 ;
     RECT  47.376 28.103 47.4 28.501 ;
     RECT  48.528 28.103 48.612 28.501 ;
     RECT  50.256 27.925 52.008 28.501 ;
     RECT  56.592 28.103 60.648 28.501 ;
     RECT  61.776 28.453 63.528 28.501 ;
     RECT  103.824 27.925 105.312 28.501 ;
     RECT  106.704 28.165 110.76 28.501 ;
     RECT  111.888 27.925 111.912 28.501 ;
     RECT  113.04 28.213 113.64 28.501 ;
     RECT  114.768 28.103 115.368 28.501 ;
     RECT  117.648 28.103 117.672 28.501 ;
     RECT  42.768 28.453 43.368 28.789 ;
     RECT  103.824 28.501 105.576 28.789 ;
     RECT  106.704 28.501 111.912 28.789 ;
     RECT  132.624 28.453 140.712 28.837 ;
     RECT  141.84 28.453 144.168 28.837 ;
     RECT  16.272 28.501 19.752 29.029 ;
     RECT  20.88 28.089 21.48 29.029 ;
     RECT  42.768 28.789 43.944 29.029 ;
     RECT  103.824 28.789 111.912 29.029 ;
     RECT  156.3 27.925 156.84 29.029 ;
     RECT  13.392 28.211 13.416 29.077 ;
     RECT  14.544 28.453 15.144 29.077 ;
     RECT  16.272 29.029 21.48 29.077 ;
     RECT  42.768 29.029 44.52 29.077 ;
     RECT  71.568 27.925 71.592 29.077 ;
     RECT  102.672 29.029 111.912 29.077 ;
     RECT  113.04 28.501 115.368 29.077 ;
     RECT  119.952 28.103 120.552 29.077 ;
     RECT  121.68 28.103 122.28 29.077 ;
     RECT  123.792 28.453 124.584 29.077 ;
     RECT  126.288 28.103 126.312 29.077 ;
     RECT  127.44 28.103 128.04 29.077 ;
     RECT  151.056 28.103 152.808 29.077 ;
     RECT  153.936 28.165 153.96 29.077 ;
     RECT  157.968 27.925 157.992 29.077 ;
     RECT  160.848 28.103 161.448 29.077 ;
     RECT  162.576 28.501 162.6 29.077 ;
     RECT  4.752 28.089 5.352 29.653 ;
     RECT  6.48 28.103 7.08 29.653 ;
     RECT  8.784 28.103 9.384 29.653 ;
     RECT  11.664 28.089 11.688 29.653 ;
     RECT  12.816 29.077 13.416 29.653 ;
     RECT  14.544 29.077 21.48 29.653 ;
     RECT  22.608 27.925 38.184 29.653 ;
     RECT  39.312 28.089 40.488 29.653 ;
     RECT  41.616 29.077 41.64 29.653 ;
     RECT  42.768 29.077 45.096 29.653 ;
     RECT  46.224 28.501 47.4 29.653 ;
     RECT  48.528 28.501 52.584 29.653 ;
     RECT  54.288 28.103 54.888 29.653 ;
     RECT  56.592 28.501 63.528 29.653 ;
     RECT  64.656 28.103 65.832 29.653 ;
     RECT  66.96 28.103 66.984 29.653 ;
     RECT  68.112 28.453 68.136 29.653 ;
     RECT  69.264 28.103 69.288 29.653 ;
     RECT  70.416 28.103 70.44 29.653 ;
     RECT  71.568 29.077 72.168 29.653 ;
     RECT  73.872 28.089 73.896 29.653 ;
     RECT  75.024 28.453 75.72 29.653 ;
     RECT  77.904 28.453 79.656 29.653 ;
     RECT  80.784 28.103 83.688 29.653 ;
     RECT  84.816 28.103 85.992 29.653 ;
     RECT  87.12 28.453 94.056 29.653 ;
     RECT  96.336 28.103 96.936 29.653 ;
     RECT  98.064 29.029 98.088 29.653 ;
     RECT  99.216 28.103 99.24 29.653 ;
     RECT  100.368 28.103 100.392 29.653 ;
     RECT  102.096 29.077 111.912 29.653 ;
     RECT  113.04 29.077 115.944 29.653 ;
     RECT  117.072 28.501 117.672 29.653 ;
     RECT  119.952 29.077 122.28 29.653 ;
     RECT  123.792 29.077 125.16 29.653 ;
     RECT  126.288 29.077 128.616 29.653 ;
     RECT  129.744 28.453 130.344 29.653 ;
     RECT  131.472 28.103 131.496 29.653 ;
     RECT  132.624 28.837 144.168 29.653 ;
     RECT  145.296 27.925 149.928 29.653 ;
     RECT  151.056 29.077 153.96 29.653 ;
     RECT  155.088 28.453 155.112 29.653 ;
     RECT  156.24 29.029 156.84 29.653 ;
     RECT  157.968 29.077 158.568 29.653 ;
     RECT  159.696 28.103 159.72 29.653 ;
     RECT  160.848 29.077 162.6 29.653 ;
     RECT  163.728 28.103 163.752 29.653 ;
     RECT  164.88 28.103 168.36 29.653 ;
     RECT  4.752 29.653 94.056 29.989 ;
     RECT  95.184 29.653 168.36 29.989 ;
     RECT  4.752 29.989 168.36 30.096 ;
     RECT  8.28 0.227 8.736 0.24 ;
     RECT  8.856 0.227 9.312 0.24 ;
     RECT  25.704 0.227 26.16 0.24 ;
     RECT  26.28 0.227 26.736 0.24 ;
     RECT  26.856 0.227 27.312 0.24 ;
     RECT  27.432 0.227 27.888 0.24 ;
     RECT  28.008 0.227 28.464 0.24 ;
     RECT  28.584 0.227 29.04 0.24 ;
     RECT  31.512 0.227 31.968 0.24 ;
     RECT  32.088 0.227 32.544 0.24 ;
     RECT  33.816 0.227 34.272 0.24 ;
     RECT  34.392 0.227 34.848 0.24 ;
     RECT  35.544 0.227 36 0.24 ;
     RECT  36.12 0.227 36.576 0.24 ;
     RECT  43.656 0.227 44.16 0.24 ;
     RECT  44.28 0.227 44.736 0.24 ;
     RECT  47.16 0.227 47.616 0.24 ;
     RECT  47.736 0.227 48.192 0.24 ;
     RECT  59.928 0.227 60.384 0.24 ;
     RECT  60.504 0.227 60.96 0.24 ;
     RECT  62.232 0.227 62.688 0.24 ;
     RECT  62.808 0.227 63.264 0.24 ;
     RECT  63.384 0.227 63.84 0.24 ;
     RECT  63.96 0.227 64.464 0.24 ;
     RECT  75.576 0.227 76.032 0.24 ;
     RECT  76.152 0.227 76.608 0.24 ;
     RECT  91.848 0.227 92.304 0.24 ;
     RECT  92.424 0.227 92.88 0.24 ;
     RECT  94.152 0.227 94.608 0.24 ;
     RECT  94.728 0.227 95.184 0.24 ;
     RECT  97.032 0.227 97.488 0.24 ;
     RECT  97.608 0.227 98.064 0.24 ;
     RECT  127.8 0.227 128.256 0.24 ;
     RECT  128.376 0.227 128.832 0.24 ;
     RECT  129.528 0.227 129.984 0.24 ;
     RECT  130.104 0.227 130.56 0.24 ;
     RECT  133.032 0.227 133.488 0.24 ;
     RECT  133.608 0.227 134.064 0.24 ;
     RECT  134.76 0.227 135.216 0.24 ;
     RECT  135.336 0.227 135.792 0.24 ;
     RECT  145.752 0.227 146.256 0.24 ;
     RECT  146.376 0.227 146.832 0.24 ;
     RECT  148.68 0.227 149.136 0.24 ;
     RECT  149.256 0.227 149.712 0.24 ;
     RECT  8.232 0.24 9.36 1.763 ;
     RECT  25.656 0.24 26.784 1.763 ;
     RECT  26.808 0.24 27.936 1.763 ;
     RECT  27.96 0.24 29.088 1.763 ;
     RECT  31.464 0.24 32.592 0.611 ;
     RECT  33.768 0.24 34.896 2.137 ;
     RECT  35.496 0.24 36.624 1.763 ;
     RECT  43.608 0.24 44.784 1.763 ;
     RECT  47.112 0.24 48.24 1.763 ;
     RECT  59.88 0.24 61.008 1.763 ;
     RECT  62.184 0.24 63.312 0.611 ;
     RECT  63.336 0.24 64.512 0.611 ;
     RECT  75.528 0.24 76.656 1.763 ;
     RECT  91.8 0.24 92.928 1.763 ;
     RECT  94.104 0.24 95.232 1.763 ;
     RECT  96.984 0.24 98.112 1.763 ;
     RECT  127.752 0.24 128.88 0.611 ;
     RECT  129.48 0.24 130.608 1.763 ;
     RECT  132.984 0.24 134.112 1.763 ;
     RECT  134.712 0.24 135.84 1.763 ;
     RECT  145.704 0.24 146.88 1.763 ;
     RECT  148.632 0.24 149.76 1.763 ;
     RECT  58.728 0.275 59.856 1.763 ;
     RECT  161.4 0.563 162.528 1.763 ;
     RECT  30.888 0.611 32.592 1.763 ;
     RECT  37.848 0.611 38.976 1.763 ;
     RECT  42.456 0.611 43.584 1.763 ;
     RECT  64.5 0.611 64.512 2.137 ;
     RECT  66.264 0.611 67.392 1.763 ;
     RECT  67.992 0.611 69.12 1.763 ;
     RECT  69.144 0.611 70.272 1.763 ;
     RECT  72.648 0.611 73.776 1.763 ;
     RECT  95.832 0.611 96.96 1.763 ;
     RECT  26.7 1.763 26.784 2.137 ;
     RECT  26.808 1.763 29.4 2.137 ;
     RECT  29.712 1.763 32.592 2.137 ;
     RECT  35.448 1.763 36.72 2.821 ;
     RECT  37.848 1.763 40.2 2.245 ;
     RECT  42.768 1.763 43.212 2.137 ;
     RECT  45.912 1.763 46.008 2.773 ;
     RECT  59.1 1.763 59.412 2.137 ;
     RECT  67.2 1.763 67.392 2.137 ;
     RECT  67.608 1.763 70.212 2.137 ;
     RECT  72.648 1.763 72.912 2.137 ;
     RECT  75.528 1.763 75.612 2.151 ;
     RECT  85.824 1.763 86.1 2.821 ;
     RECT  86.412 1.763 87.456 2.821 ;
     RECT  87.48 1.763 88.704 2.821 ;
     RECT  89.112 1.763 90.384 2.821 ;
     RECT  90.408 1.763 91.392 2.821 ;
     RECT  91.8 1.763 93.504 2.151 ;
     RECT  94.104 1.763 96.96 2.137 ;
     RECT  96.984 1.763 97.944 2.137 ;
     RECT  129.48 1.763 129.72 2.151 ;
     RECT  134.208 1.763 134.4 2.821 ;
     RECT  134.712 1.763 136.368 2.137 ;
     RECT  136.392 1.763 137.4 2.821 ;
     RECT  140.412 1.763 142.416 2.821 ;
     RECT  144.072 1.763 145.5 2.821 ;
     RECT  145.704 1.763 147.792 2.151 ;
     RECT  151.212 1.763 152.352 2.821 ;
     RECT  152.376 1.763 153.6 14.773 ;
     RECT  161.7 1.763 162.012 2.137 ;
     RECT  26.82 2.137 29.4 2.151 ;
     RECT  29.712 2.137 32.1 2.245 ;
     RECT  33.768 2.137 34.8 2.821 ;
     RECT  67.608 2.137 69.9 2.677 ;
     RECT  72.72 2.137 72.912 2.151 ;
     RECT  94.512 2.137 96.9 2.245 ;
     RECT  97.02 2.137 97.944 2.151 ;
     RECT  134.82 2.137 136.368 2.151 ;
     RECT  27.912 2.151 29.4 14.867 ;
     RECT  91.812 2.151 93.504 2.245 ;
     RECT  97.212 2.151 97.944 2.821 ;
     RECT  129.612 2.151 129.72 2.245 ;
     RECT  135.012 2.151 136.368 2.821 ;
     RECT  145.812 2.151 147.792 2.245 ;
     RECT  29.712 2.245 30.96 2.821 ;
     RECT  30.984 2.245 32.1 14.291 ;
     RECT  38.616 2.245 40.2 2.821 ;
     RECT  92.328 2.245 93.504 2.821 ;
     RECT  94.512 2.245 96.72 2.821 ;
     RECT  138.696 2.245 139.824 2.821 ;
     RECT  146.04 2.245 147.792 2.821 ;
     RECT  67.608 2.677 68.64 2.821 ;
     RECT  68.664 2.677 69.9 26.243 ;
     RECT  67.656 2.821 68.64 26.243 ;
     RECT  151.212 2.821 152.208 14.867 ;
     RECT  35.448 13.715 36.432 14.677 ;
     RECT  146.856 13.715 147.984 15.061 ;
     RECT  30.648 14.291 32.1 14.773 ;
     RECT  37.944 14.291 38.928 24.563 ;
     RECT  30.648 14.773 31.728 14.867 ;
     RECT  148.512 14.773 149.856 25.333 ;
     RECT  27.012 14.867 29.4 15.349 ;
     RECT  29.712 14.867 31.728 15.349 ;
     RECT  151.212 14.867 152.448 24.563 ;
     RECT  27.012 15.349 28.464 26.243 ;
     RECT  29.712 15.349 30.96 26.243 ;
     RECT  51.312 24.469 52.416 24.995 ;
     RECT  52.44 24.469 53.424 24.995 ;
     RECT  35.736 24.563 36.768 26.243 ;
     RECT  37.812 24.563 39.072 25.139 ;
     RECT  39.096 24.563 40.08 25.139 ;
     RECT  89.448 24.563 90.48 26.387 ;
     RECT  94.512 24.563 95.664 26.101 ;
     RECT  135.336 24.563 136.512 25.139 ;
     RECT  151.212 24.563 152.496 25.525 ;
     RECT  57.624 24.613 59.1 26.003 ;
     RECT  87.72 24.659 88.8 26.243 ;
     RECT  86.616 25.139 87.696 26.243 ;
     RECT  130.392 25.189 131.904 25.717 ;
     RECT  148.632 25.333 149.856 25.861 ;
     RECT  151.32 25.525 152.496 26.243 ;
     RECT  14.568 25.573 15.9 26.243 ;
     RECT  92.952 25.715 93.984 26.243 ;
     RECT  130.392 25.717 131.76 26.003 ;
     RECT  148.776 25.861 149.856 26.243 ;
     RECT  56.808 26.003 59.1 26.821 ;
     RECT  159.312 26.003 159.72 27.349 ;
     RECT  105.312 26.005 106.704 28.501 ;
     RECT  106.728 26.005 107.7 27.925 ;
     RECT  7.488 26.051 7.8 27.349 ;
     RECT  94.512 26.101 95.52 26.675 ;
     RECT  91.812 26.243 92.832 26.339 ;
     RECT  92.856 26.243 94.032 26.339 ;
     RECT  141.336 26.243 142.704 26.291 ;
     RECT  145.812 26.243 147.024 26.771 ;
     RECT  148.776 26.243 150.768 26.339 ;
     RECT  143.64 26.339 144.72 26.627 ;
     RECT  148.776 26.339 149.352 26.725 ;
     RECT  89.4 26.387 90.48 26.771 ;
     RECT  78.504 26.485 79.968 26.819 ;
     RECT  74.688 26.627 75.3 27.925 ;
     RECT  143.592 26.627 144.72 26.867 ;
     RECT  110.712 26.675 112.128 26.819 ;
     RECT  139.68 26.675 140.1 27.925 ;
     RECT  34.176 26.723 34.8 27.925 ;
     RECT  137.928 26.723 138.072 26.915 ;
     RECT  56.304 26.771 56.4 27.925 ;
     RECT  89.4 26.771 91.056 26.819 ;
     RECT  145.812 26.771 147.072 26.867 ;
     RECT  147.096 26.771 148.2 26.867 ;
     RECT  113.412 26.773 114.768 27.925 ;
     RECT  114.792 26.773 115.8 27.925 ;
     RECT  89.4 26.819 91.152 27.925 ;
     RECT  110.712 26.819 113.1 27.925 ;
     RECT  56.808 26.821 58.32 27.925 ;
     RECT  145.296 26.867 145.5 27.925 ;
     RECT  145.812 26.867 148.2 27.925 ;
     RECT  137.832 26.915 138.072 27.925 ;
     RECT  123.744 27.107 123.792 27.925 ;
     RECT  5.412 27.349 6.48 28.089 ;
     RECT  118.812 27.349 119.952 28.089 ;
     RECT  48.612 27.491 48.84 27.925 ;
     RECT  116.232 27.491 116.28 27.925 ;
     RECT  13.104 27.683 13.2 27.925 ;
     RECT  149.928 27.877 150.9 28.103 ;
     RECT  9.384 27.925 10.5 28.103 ;
     RECT  11.688 27.925 13.2 28.103 ;
     RECT  16.212 27.925 17.424 28.103 ;
     RECT  17.448 27.925 18.48 28.453 ;
     RECT  21.612 27.925 22.608 28.089 ;
     RECT  38.184 27.925 39.312 29.653 ;
     RECT  46.248 27.925 47.376 28.501 ;
     RECT  48.612 27.925 50.256 28.501 ;
     RECT  54.888 27.925 56.4 28.103 ;
     RECT  60.648 27.925 61.8 28.213 ;
     RECT  65.832 27.925 66.96 29.653 ;
     RECT  70.44 27.925 71.568 29.653 ;
     RECT  71.592 27.925 72.6 28.103 ;
     RECT  73.896 27.925 75.3 28.453 ;
     RECT  83.712 27.925 84.816 28.089 ;
     RECT  86.616 27.925 87.696 28.103 ;
     RECT  102.612 27.925 103.824 28.103 ;
     RECT  110.712 27.925 111.888 28.165 ;
     RECT  111.912 27.925 113.1 28.213 ;
     RECT  113.64 27.925 114.768 28.501 ;
     RECT  116.232 27.925 117.648 28.089 ;
     RECT  122.28 27.925 123.792 29.653 ;
     RECT  128.04 27.925 129.3 28.103 ;
     RECT  132.648 27.925 133.776 28.453 ;
     RECT  140.712 27.925 141.84 28.837 ;
     RECT  156.84 27.925 157.968 29.653 ;
     RECT  157.992 27.925 159 28.103 ;
     RECT  159.72 27.925 160.848 29.653 ;
     RECT  166.056 27.925 167.1 27.973 ;
     RECT  168.36 28.021 169.8 28.103 ;
     RECT  5.352 28.089 6.48 29.653 ;
     RECT  10.62 28.089 11.664 28.103 ;
     RECT  21.48 28.089 22.608 29.653 ;
     RECT  40.488 28.089 40.512 29.077 ;
     RECT  72.72 28.089 73.872 28.103 ;
     RECT  83.688 28.089 84.816 29.653 ;
     RECT  97.02 28.089 97.212 28.103 ;
     RECT  115.92 28.089 117.648 28.103 ;
     RECT  118.62 28.089 119.952 28.103 ;
     RECT  11.688 28.103 13.392 29.077 ;
     RECT  15.9 28.103 17.424 28.453 ;
     RECT  45.6 28.103 46.224 29.029 ;
     RECT  47.4 28.103 48.528 29.653 ;
     RECT  64.5 28.103 64.656 28.453 ;
     RECT  66.984 28.103 67.512 28.453 ;
     RECT  69.288 28.103 70.416 29.653 ;
     RECT  71.592 28.103 72.168 29.077 ;
     RECT  80.7 28.103 80.784 28.453 ;
     RECT  85.992 28.103 87.696 28.453 ;
     RECT  96.936 28.103 97.212 29.029 ;
     RECT  99.24 28.103 100.368 29.653 ;
     RECT  102.3 28.103 103.824 29.029 ;
     RECT  115.368 28.103 117.648 28.501 ;
     RECT  120.552 28.103 121.68 29.077 ;
     RECT  126.312 28.103 127.44 29.077 ;
     RECT  128.04 28.103 129.612 28.453 ;
     RECT  131.496 28.103 132.624 29.653 ;
     RECT  149.928 28.103 151.056 29.653 ;
     RECT  152.808 28.103 153.912 28.165 ;
     RECT  157.992 28.103 159.696 29.077 ;
     RECT  161.448 28.103 162.012 28.501 ;
     RECT  163.752 28.103 164.88 29.653 ;
     RECT  110.76 28.165 111.888 28.501 ;
     RECT  152.808 28.165 153.936 29.077 ;
     RECT  13.416 28.211 13.608 28.453 ;
     RECT  60.648 28.213 61.776 28.501 ;
     RECT  111.912 28.213 113.04 29.653 ;
     RECT  13.416 28.453 14.544 29.653 ;
     RECT  15.144 28.453 17.424 28.501 ;
     RECT  19.752 28.453 20.88 29.029 ;
     RECT  63.528 28.453 64.656 29.653 ;
     RECT  66.984 28.453 68.112 29.653 ;
     RECT  68.136 28.453 69.264 29.653 ;
     RECT  73.896 28.453 75.024 29.653 ;
     RECT  79.656 28.453 80.784 29.653 ;
     RECT  85.992 28.453 87.12 29.653 ;
     RECT  128.04 28.453 129.744 29.077 ;
     RECT  130.344 28.453 131.472 29.653 ;
     RECT  144.168 28.453 145.296 29.653 ;
     RECT  153.96 28.453 155.088 29.653 ;
     RECT  155.112 28.453 156.3 29.029 ;
     RECT  15.144 28.501 16.272 29.077 ;
     RECT  105.576 28.501 106.704 28.789 ;
     RECT  115.368 28.501 117.072 29.077 ;
     RECT  161.448 28.501 162.576 29.077 ;
     RECT  162.6 28.501 163.728 29.653 ;
     RECT  44.52 29.029 46.224 29.077 ;
     RECT  96.936 29.029 98.064 29.653 ;
     RECT  98.088 29.029 99.216 29.653 ;
     RECT  102.3 29.029 102.672 29.077 ;
     RECT  155.112 29.029 156.24 29.653 ;
     RECT  11.688 29.077 12.816 29.653 ;
     RECT  40.488 29.077 41.616 29.653 ;
     RECT  41.64 29.077 42.768 29.653 ;
     RECT  45.096 29.077 46.224 29.653 ;
     RECT  115.944 29.077 117.072 29.653 ;
     RECT  125.16 29.077 126.288 29.653 ;
     RECT  128.616 29.077 129.744 29.653 ;
     RECT  158.568 29.077 159.696 29.653 ;
     RECT  94.056 29.653 95.184 29.989 ;
  END
END dsfd_sstn_e0c0sinf
END LIBRARY
